VERSION 5.8 ;
BUSBITCHARS "[]" ;
DIVIDERCHAR "/" ;
UNITS
    DATABASE MICRONS 1000 ;
END UNITS

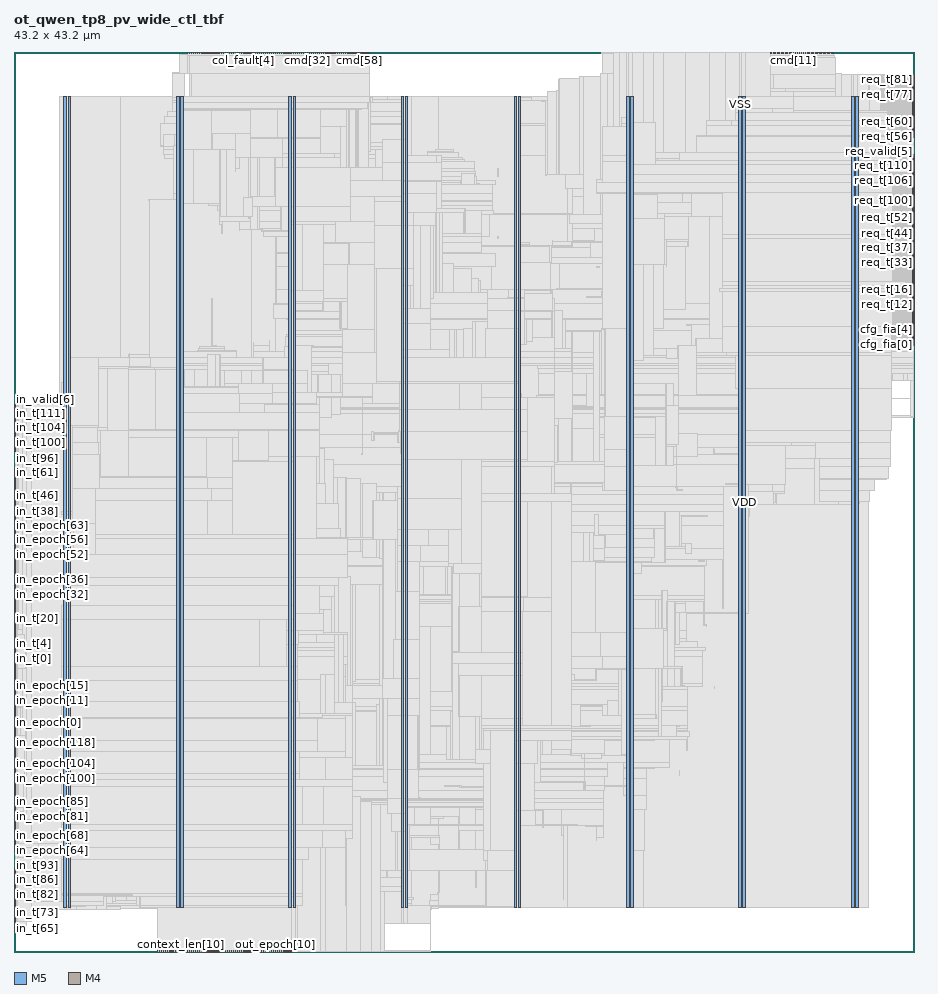
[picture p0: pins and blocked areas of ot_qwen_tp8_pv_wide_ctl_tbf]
MACRO ot_qwen_tp8_pv_wide_ctl_tbf
  FOREIGN ot_qwen_tp8_pv_wide_ctl_tbf 0 0 ;
  CLASS BLOCK ;
  SIZE 43.2 BY 43.2 ;
  PIN busy
    DIRECTION OUTPUT ;
    USE SIGNAL ;
    PORT
      LAYER M5 ;
        RECT  6.864 0 6.888 0.084 ;
    END
  END busy
  PIN cfg_fia[0]
    DIRECTION INPUT ;
    USE SIGNAL ;
    PORT
      LAYER M4 ;
        RECT  43.116 29.136 43.2 29.16 ;
    END
  END cfg_fia[0]
  PIN cfg_fia[1]
    DIRECTION INPUT ;
    USE SIGNAL ;
    PORT
      LAYER M4 ;
        RECT  43.116 29.232 43.2 29.256 ;
    END
  END cfg_fia[1]
  PIN cfg_fia[2]
    DIRECTION INPUT ;
    USE SIGNAL ;
    PORT
      LAYER M4 ;
        RECT  43.116 29.328 43.2 29.352 ;
    END
  END cfg_fia[2]
  PIN cfg_fia[3]
    DIRECTION INPUT ;
    USE SIGNAL ;
    PORT
      LAYER M4 ;
        RECT  43.116 29.424 43.2 29.448 ;
    END
  END cfg_fia[3]
  PIN cfg_fia[4]
    DIRECTION INPUT ;
    USE SIGNAL ;
    PORT
      LAYER M4 ;
        RECT  43.116 29.52 43.2 29.544 ;
    END
  END cfg_fia[4]
  PIN cfg_fia[5]
    DIRECTION INPUT ;
    USE SIGNAL ;
    PORT
      LAYER M4 ;
        RECT  43.116 29.616 43.2 29.64 ;
    END
  END cfg_fia[5]
  PIN cfg_fia[6]
    DIRECTION INPUT ;
    USE SIGNAL ;
    PORT
      LAYER M4 ;
        RECT  43.116 29.712 43.2 29.736 ;
    END
  END cfg_fia[6]
  PIN cfg_fia[7]
    DIRECTION INPUT ;
    USE SIGNAL ;
    PORT
      LAYER M4 ;
        RECT  43.116 29.808 43.2 29.832 ;
    END
  END cfg_fia[7]
  PIN clk
    DIRECTION INPUT ;
    USE SIGNAL ;
    PORT
      LAYER M5 ;
        RECT  6.96 0 6.984 0.084 ;
    END
  END clk
  PIN cmd[0]
    DIRECTION OUTPUT ;
    USE SIGNAL ;
    PORT
      LAYER M5 ;
        RECT  36.336 43.116 36.36 43.2 ;
    END
  END cmd[0]
  PIN cmd[10]
    DIRECTION OUTPUT ;
    USE SIGNAL ;
    PORT
      LAYER M5 ;
        RECT  37.296 43.116 37.32 43.2 ;
    END
  END cmd[10]
  PIN cmd[11]
    DIRECTION OUTPUT ;
    USE SIGNAL ;
    PORT
      LAYER M5 ;
        RECT  37.392 43.116 37.416 43.2 ;
    END
  END cmd[11]
  PIN cmd[12]
    DIRECTION OUTPUT ;
    USE SIGNAL ;
    PORT
      LAYER M5 ;
        RECT  37.488 43.116 37.512 43.2 ;
    END
  END cmd[12]
  PIN cmd[13]
    DIRECTION OUTPUT ;
    USE SIGNAL ;
    PORT
      LAYER M5 ;
        RECT  37.584 43.116 37.608 43.2 ;
    END
  END cmd[13]
  PIN cmd[14]
    DIRECTION OUTPUT ;
    USE SIGNAL ;
    PORT
      LAYER M5 ;
        RECT  37.68 43.116 37.704 43.2 ;
    END
  END cmd[14]
  PIN cmd[15]
    DIRECTION OUTPUT ;
    USE SIGNAL ;
    PORT
      LAYER M5 ;
        RECT  37.776 43.116 37.8 43.2 ;
    END
  END cmd[15]
  PIN cmd[16]
    DIRECTION OUTPUT ;
    USE SIGNAL ;
    PORT
      LAYER M5 ;
        RECT  37.872 43.116 37.896 43.2 ;
    END
  END cmd[16]
  PIN cmd[17]
    DIRECTION OUTPUT ;
    USE SIGNAL ;
    PORT
      LAYER M5 ;
        RECT  37.968 43.116 37.992 43.2 ;
    END
  END cmd[17]
  PIN cmd[18]
    DIRECTION OUTPUT ;
    USE SIGNAL ;
    PORT
      LAYER M5 ;
        RECT  38.064 43.116 38.088 43.2 ;
    END
  END cmd[18]
  PIN cmd[19]
    DIRECTION OUTPUT ;
    USE SIGNAL ;
    PORT
      LAYER M5 ;
        RECT  38.16 43.116 38.184 43.2 ;
    END
  END cmd[19]
  PIN cmd[1]
    DIRECTION OUTPUT ;
    USE SIGNAL ;
    PORT
      LAYER M5 ;
        RECT  36.432 43.116 36.456 43.2 ;
    END
  END cmd[1]
  PIN cmd[20]
    DIRECTION OUTPUT ;
    USE SIGNAL ;
    PORT
      LAYER M5 ;
        RECT  38.256 43.116 38.28 43.2 ;
    END
  END cmd[20]
  PIN cmd[21]
    DIRECTION OUTPUT ;
    USE SIGNAL ;
    PORT
      LAYER M5 ;
        RECT  38.352 43.116 38.376 43.2 ;
    END
  END cmd[21]
  PIN cmd[22]
    DIRECTION OUTPUT ;
    USE SIGNAL ;
    PORT
      LAYER M5 ;
        RECT  38.448 43.116 38.472 43.2 ;
    END
  END cmd[22]
  PIN cmd[23]
    DIRECTION OUTPUT ;
    USE SIGNAL ;
    PORT
      LAYER M5 ;
        RECT  38.544 43.116 38.568 43.2 ;
    END
  END cmd[23]
  PIN cmd[24]
    DIRECTION OUTPUT ;
    USE SIGNAL ;
    PORT
      LAYER M5 ;
        RECT  38.64 43.116 38.664 43.2 ;
    END
  END cmd[24]
  PIN cmd[25]
    DIRECTION OUTPUT ;
    USE SIGNAL ;
    PORT
      LAYER M5 ;
        RECT  38.736 43.116 38.76 43.2 ;
    END
  END cmd[25]
  PIN cmd[26]
    DIRECTION OUTPUT ;
    USE SIGNAL ;
    PORT
      LAYER M5 ;
        RECT  38.832 43.116 38.856 43.2 ;
    END
  END cmd[26]
  PIN cmd[27]
    DIRECTION OUTPUT ;
    USE SIGNAL ;
    PORT
      LAYER M5 ;
        RECT  38.928 43.116 38.952 43.2 ;
    END
  END cmd[27]
  PIN cmd[28]
    DIRECTION OUTPUT ;
    USE SIGNAL ;
    PORT
      LAYER M5 ;
        RECT  39.024 43.116 39.048 43.2 ;
    END
  END cmd[28]
  PIN cmd[29]
    DIRECTION OUTPUT ;
    USE SIGNAL ;
    PORT
      LAYER M5 ;
        RECT  39.12 43.116 39.144 43.2 ;
    END
  END cmd[29]
  PIN cmd[2]
    DIRECTION OUTPUT ;
    USE SIGNAL ;
    PORT
      LAYER M5 ;
        RECT  36.528 43.116 36.552 43.2 ;
    END
  END cmd[2]
  PIN cmd[30]
    DIRECTION OUTPUT ;
    USE SIGNAL ;
    PORT
      LAYER M5 ;
        RECT  39.216 43.116 39.24 43.2 ;
    END
  END cmd[30]
  PIN cmd[31]
    DIRECTION OUTPUT ;
    USE SIGNAL ;
    PORT
      LAYER M5 ;
        RECT  39.312 43.116 39.336 43.2 ;
    END
  END cmd[31]
  PIN cmd[32]
    DIRECTION OUTPUT ;
    USE SIGNAL ;
    PORT
      LAYER M5 ;
        RECT  14.064 43.116 14.088 43.2 ;
    END
  END cmd[32]
  PIN cmd[33]
    DIRECTION OUTPUT ;
    USE SIGNAL ;
    PORT
      LAYER M5 ;
        RECT  14.16 43.116 14.184 43.2 ;
    END
  END cmd[33]
  PIN cmd[34]
    DIRECTION OUTPUT ;
    USE SIGNAL ;
    PORT
      LAYER M5 ;
        RECT  14.256 43.116 14.28 43.2 ;
    END
  END cmd[34]
  PIN cmd[35]
    DIRECTION OUTPUT ;
    USE SIGNAL ;
    PORT
      LAYER M5 ;
        RECT  14.352 43.116 14.376 43.2 ;
    END
  END cmd[35]
  PIN cmd[36]
    DIRECTION OUTPUT ;
    USE SIGNAL ;
    PORT
      LAYER M5 ;
        RECT  14.448 43.116 14.472 43.2 ;
    END
  END cmd[36]
  PIN cmd[37]
    DIRECTION OUTPUT ;
    USE SIGNAL ;
    PORT
      LAYER M5 ;
        RECT  14.544 43.116 14.568 43.2 ;
    END
  END cmd[37]
  PIN cmd[38]
    DIRECTION OUTPUT ;
    USE SIGNAL ;
    PORT
      LAYER M5 ;
        RECT  14.64 43.116 14.664 43.2 ;
    END
  END cmd[38]
  PIN cmd[39]
    DIRECTION OUTPUT ;
    USE SIGNAL ;
    PORT
      LAYER M5 ;
        RECT  14.736 43.116 14.76 43.2 ;
    END
  END cmd[39]
  PIN cmd[3]
    DIRECTION OUTPUT ;
    USE SIGNAL ;
    PORT
      LAYER M5 ;
        RECT  36.624 43.116 36.648 43.2 ;
    END
  END cmd[3]
  PIN cmd[40]
    DIRECTION OUTPUT ;
    USE SIGNAL ;
    PORT
      LAYER M5 ;
        RECT  14.832 43.116 14.856 43.2 ;
    END
  END cmd[40]
  PIN cmd[41]
    DIRECTION OUTPUT ;
    USE SIGNAL ;
    PORT
      LAYER M5 ;
        RECT  14.928 43.116 14.952 43.2 ;
    END
  END cmd[41]
  PIN cmd[42]
    DIRECTION OUTPUT ;
    USE SIGNAL ;
    PORT
      LAYER M5 ;
        RECT  15.024 43.116 15.048 43.2 ;
    END
  END cmd[42]
  PIN cmd[43]
    DIRECTION OUTPUT ;
    USE SIGNAL ;
    PORT
      LAYER M5 ;
        RECT  15.12 43.116 15.144 43.2 ;
    END
  END cmd[43]
  PIN cmd[44]
    DIRECTION OUTPUT ;
    USE SIGNAL ;
    PORT
      LAYER M5 ;
        RECT  15.216 43.116 15.24 43.2 ;
    END
  END cmd[44]
  PIN cmd[45]
    DIRECTION OUTPUT ;
    USE SIGNAL ;
    PORT
      LAYER M5 ;
        RECT  15.312 43.116 15.336 43.2 ;
    END
  END cmd[45]
  PIN cmd[46]
    DIRECTION OUTPUT ;
    USE SIGNAL ;
    PORT
      LAYER M5 ;
        RECT  15.408 43.116 15.432 43.2 ;
    END
  END cmd[46]
  PIN cmd[47]
    DIRECTION OUTPUT ;
    USE SIGNAL ;
    PORT
      LAYER M5 ;
        RECT  15.504 43.116 15.528 43.2 ;
    END
  END cmd[47]
  PIN cmd[48]
    DIRECTION OUTPUT ;
    USE SIGNAL ;
    PORT
      LAYER M5 ;
        RECT  15.6 43.116 15.624 43.2 ;
    END
  END cmd[48]
  PIN cmd[49]
    DIRECTION OUTPUT ;
    USE SIGNAL ;
    PORT
      LAYER M5 ;
        RECT  15.696 43.116 15.72 43.2 ;
    END
  END cmd[49]
  PIN cmd[4]
    DIRECTION OUTPUT ;
    USE SIGNAL ;
    PORT
      LAYER M5 ;
        RECT  36.72 43.116 36.744 43.2 ;
    END
  END cmd[4]
  PIN cmd[50]
    DIRECTION OUTPUT ;
    USE SIGNAL ;
    PORT
      LAYER M5 ;
        RECT  15.792 43.116 15.816 43.2 ;
    END
  END cmd[50]
  PIN cmd[51]
    DIRECTION OUTPUT ;
    USE SIGNAL ;
    PORT
      LAYER M5 ;
        RECT  15.888 43.116 15.912 43.2 ;
    END
  END cmd[51]
  PIN cmd[52]
    DIRECTION OUTPUT ;
    USE SIGNAL ;
    PORT
      LAYER M5 ;
        RECT  15.984 43.116 16.008 43.2 ;
    END
  END cmd[52]
  PIN cmd[53]
    DIRECTION OUTPUT ;
    USE SIGNAL ;
    PORT
      LAYER M5 ;
        RECT  16.08 43.116 16.104 43.2 ;
    END
  END cmd[53]
  PIN cmd[54]
    DIRECTION OUTPUT ;
    USE SIGNAL ;
    PORT
      LAYER M5 ;
        RECT  16.176 43.116 16.2 43.2 ;
    END
  END cmd[54]
  PIN cmd[55]
    DIRECTION OUTPUT ;
    USE SIGNAL ;
    PORT
      LAYER M5 ;
        RECT  16.272 43.116 16.296 43.2 ;
    END
  END cmd[55]
  PIN cmd[56]
    DIRECTION OUTPUT ;
    USE SIGNAL ;
    PORT
      LAYER M5 ;
        RECT  16.368 43.116 16.392 43.2 ;
    END
  END cmd[56]
  PIN cmd[57]
    DIRECTION OUTPUT ;
    USE SIGNAL ;
    PORT
      LAYER M5 ;
        RECT  16.464 43.116 16.488 43.2 ;
    END
  END cmd[57]
  PIN cmd[58]
    DIRECTION OUTPUT ;
    USE SIGNAL ;
    PORT
      LAYER M5 ;
        RECT  16.56 43.116 16.584 43.2 ;
    END
  END cmd[58]
  PIN cmd[59]
    DIRECTION OUTPUT ;
    USE SIGNAL ;
    PORT
      LAYER M5 ;
        RECT  16.656 43.116 16.68 43.2 ;
    END
  END cmd[59]
  PIN cmd[5]
    DIRECTION OUTPUT ;
    USE SIGNAL ;
    PORT
      LAYER M5 ;
        RECT  36.816 43.116 36.84 43.2 ;
    END
  END cmd[5]
  PIN cmd[6]
    DIRECTION OUTPUT ;
    USE SIGNAL ;
    PORT
      LAYER M5 ;
        RECT  36.912 43.116 36.936 43.2 ;
    END
  END cmd[6]
  PIN cmd[7]
    DIRECTION OUTPUT ;
    USE SIGNAL ;
    PORT
      LAYER M5 ;
        RECT  37.008 43.116 37.032 43.2 ;
    END
  END cmd[7]
  PIN cmd[8]
    DIRECTION OUTPUT ;
    USE SIGNAL ;
    PORT
      LAYER M5 ;
        RECT  37.104 43.116 37.128 43.2 ;
    END
  END cmd[8]
  PIN cmd[9]
    DIRECTION OUTPUT ;
    USE SIGNAL ;
    PORT
      LAYER M5 ;
        RECT  37.2 43.116 37.224 43.2 ;
    END
  END cmd[9]
  PIN col_fault[0]
    DIRECTION INPUT ;
    USE SIGNAL ;
    PORT
      LAYER M5 ;
        RECT  16.752 43.116 16.776 43.2 ;
    END
  END col_fault[0]
  PIN col_fault[10]
    DIRECTION INPUT ;
    USE SIGNAL ;
    PORT
      LAYER M5 ;
        RECT  11.568 43.116 11.592 43.2 ;
    END
  END col_fault[10]
  PIN col_fault[11]
    DIRECTION INPUT ;
    USE SIGNAL ;
    PORT
      LAYER M5 ;
        RECT  11.664 43.116 11.688 43.2 ;
    END
  END col_fault[11]
  PIN col_fault[12]
    DIRECTION INPUT ;
    USE SIGNAL ;
    PORT
      LAYER M5 ;
        RECT  11.76 43.116 11.784 43.2 ;
    END
  END col_fault[12]
  PIN col_fault[13]
    DIRECTION INPUT ;
    USE SIGNAL ;
    PORT
      LAYER M5 ;
        RECT  11.856 43.116 11.88 43.2 ;
    END
  END col_fault[13]
  PIN col_fault[14]
    DIRECTION INPUT ;
    USE SIGNAL ;
    PORT
      LAYER M5 ;
        RECT  11.952 43.116 11.976 43.2 ;
    END
  END col_fault[14]
  PIN col_fault[15]
    DIRECTION INPUT ;
    USE SIGNAL ;
    PORT
      LAYER M5 ;
        RECT  12.048 43.116 12.072 43.2 ;
    END
  END col_fault[15]
  PIN col_fault[16]
    DIRECTION INPUT ;
    USE SIGNAL ;
    PORT
      LAYER M5 ;
        RECT  12.144 43.116 12.168 43.2 ;
    END
  END col_fault[16]
  PIN col_fault[17]
    DIRECTION INPUT ;
    USE SIGNAL ;
    PORT
      LAYER M5 ;
        RECT  12.24 43.116 12.264 43.2 ;
    END
  END col_fault[17]
  PIN col_fault[18]
    DIRECTION INPUT ;
    USE SIGNAL ;
    PORT
      LAYER M5 ;
        RECT  12.336 43.116 12.36 43.2 ;
    END
  END col_fault[18]
  PIN col_fault[19]
    DIRECTION INPUT ;
    USE SIGNAL ;
    PORT
      LAYER M5 ;
        RECT  12.432 43.116 12.456 43.2 ;
    END
  END col_fault[19]
  PIN col_fault[1]
    DIRECTION INPUT ;
    USE SIGNAL ;
    PORT
      LAYER M5 ;
        RECT  16.848 43.116 16.872 43.2 ;
    END
  END col_fault[1]
  PIN col_fault[20]
    DIRECTION INPUT ;
    USE SIGNAL ;
    PORT
      LAYER M5 ;
        RECT  12.528 43.116 12.552 43.2 ;
    END
  END col_fault[20]
  PIN col_fault[21]
    DIRECTION INPUT ;
    USE SIGNAL ;
    PORT
      LAYER M5 ;
        RECT  12.624 43.116 12.648 43.2 ;
    END
  END col_fault[21]
  PIN col_fault[22]
    DIRECTION INPUT ;
    USE SIGNAL ;
    PORT
      LAYER M5 ;
        RECT  12.72 43.116 12.744 43.2 ;
    END
  END col_fault[22]
  PIN col_fault[23]
    DIRECTION INPUT ;
    USE SIGNAL ;
    PORT
      LAYER M5 ;
        RECT  12.816 43.116 12.84 43.2 ;
    END
  END col_fault[23]
  PIN col_fault[24]
    DIRECTION INPUT ;
    USE SIGNAL ;
    PORT
      LAYER M5 ;
        RECT  12.912 43.116 12.936 43.2 ;
    END
  END col_fault[24]
  PIN col_fault[25]
    DIRECTION INPUT ;
    USE SIGNAL ;
    PORT
      LAYER M5 ;
        RECT  13.008 43.116 13.032 43.2 ;
    END
  END col_fault[25]
  PIN col_fault[26]
    DIRECTION INPUT ;
    USE SIGNAL ;
    PORT
      LAYER M5 ;
        RECT  13.104 43.116 13.128 43.2 ;
    END
  END col_fault[26]
  PIN col_fault[27]
    DIRECTION INPUT ;
    USE SIGNAL ;
    PORT
      LAYER M5 ;
        RECT  13.2 43.116 13.224 43.2 ;
    END
  END col_fault[27]
  PIN col_fault[28]
    DIRECTION INPUT ;
    USE SIGNAL ;
    PORT
      LAYER M5 ;
        RECT  13.296 43.116 13.32 43.2 ;
    END
  END col_fault[28]
  PIN col_fault[29]
    DIRECTION INPUT ;
    USE SIGNAL ;
    PORT
      LAYER M5 ;
        RECT  13.392 43.116 13.416 43.2 ;
    END
  END col_fault[29]
  PIN col_fault[2]
    DIRECTION INPUT ;
    USE SIGNAL ;
    PORT
      LAYER M5 ;
        RECT  16.944 43.116 16.968 43.2 ;
    END
  END col_fault[2]
  PIN col_fault[30]
    DIRECTION INPUT ;
    USE SIGNAL ;
    PORT
      LAYER M5 ;
        RECT  13.488 43.116 13.512 43.2 ;
    END
  END col_fault[30]
  PIN col_fault[31]
    DIRECTION INPUT ;
    USE SIGNAL ;
    PORT
      LAYER M5 ;
        RECT  13.584 43.116 13.608 43.2 ;
    END
  END col_fault[31]
  PIN col_fault[3]
    DIRECTION INPUT ;
    USE SIGNAL ;
    PORT
      LAYER M5 ;
        RECT  17.04 43.116 17.064 43.2 ;
    END
  END col_fault[3]
  PIN col_fault[4]
    DIRECTION INPUT ;
    USE SIGNAL ;
    PORT
      LAYER M5 ;
        RECT  10.992 43.116 11.016 43.2 ;
    END
  END col_fault[4]
  PIN col_fault[5]
    DIRECTION INPUT ;
    USE SIGNAL ;
    PORT
      LAYER M5 ;
        RECT  11.088 43.116 11.112 43.2 ;
    END
  END col_fault[5]
  PIN col_fault[6]
    DIRECTION INPUT ;
    USE SIGNAL ;
    PORT
      LAYER M5 ;
        RECT  11.184 43.116 11.208 43.2 ;
    END
  END col_fault[6]
  PIN col_fault[7]
    DIRECTION INPUT ;
    USE SIGNAL ;
    PORT
      LAYER M5 ;
        RECT  11.28 43.116 11.304 43.2 ;
    END
  END col_fault[7]
  PIN col_fault[8]
    DIRECTION INPUT ;
    USE SIGNAL ;
    PORT
      LAYER M5 ;
        RECT  11.376 43.116 11.4 43.2 ;
    END
  END col_fault[8]
  PIN col_fault[9]
    DIRECTION INPUT ;
    USE SIGNAL ;
    PORT
      LAYER M5 ;
        RECT  11.472 43.116 11.496 43.2 ;
    END
  END col_fault[9]
  PIN col_valid[0]
    DIRECTION INPUT ;
    USE SIGNAL ;
    PORT
      LAYER M5 ;
        RECT  13.68 43.116 13.704 43.2 ;
    END
  END col_valid[0]
  PIN col_valid[10]
    DIRECTION INPUT ;
    USE SIGNAL ;
    PORT
      LAYER M5 ;
        RECT  8.88 43.116 8.904 43.2 ;
    END
  END col_valid[10]
  PIN col_valid[11]
    DIRECTION INPUT ;
    USE SIGNAL ;
    PORT
      LAYER M5 ;
        RECT  8.976 43.116 9 43.2 ;
    END
  END col_valid[11]
  PIN col_valid[12]
    DIRECTION INPUT ;
    USE SIGNAL ;
    PORT
      LAYER M5 ;
        RECT  9.072 43.116 9.096 43.2 ;
    END
  END col_valid[12]
  PIN col_valid[13]
    DIRECTION INPUT ;
    USE SIGNAL ;
    PORT
      LAYER M5 ;
        RECT  9.168 43.116 9.192 43.2 ;
    END
  END col_valid[13]
  PIN col_valid[14]
    DIRECTION INPUT ;
    USE SIGNAL ;
    PORT
      LAYER M5 ;
        RECT  9.264 43.116 9.288 43.2 ;
    END
  END col_valid[14]
  PIN col_valid[15]
    DIRECTION INPUT ;
    USE SIGNAL ;
    PORT
      LAYER M5 ;
        RECT  9.36 43.116 9.384 43.2 ;
    END
  END col_valid[15]
  PIN col_valid[16]
    DIRECTION INPUT ;
    USE SIGNAL ;
    PORT
      LAYER M5 ;
        RECT  9.456 43.116 9.48 43.2 ;
    END
  END col_valid[16]
  PIN col_valid[17]
    DIRECTION INPUT ;
    USE SIGNAL ;
    PORT
      LAYER M5 ;
        RECT  9.552 43.116 9.576 43.2 ;
    END
  END col_valid[17]
  PIN col_valid[18]
    DIRECTION INPUT ;
    USE SIGNAL ;
    PORT
      LAYER M5 ;
        RECT  9.648 43.116 9.672 43.2 ;
    END
  END col_valid[18]
  PIN col_valid[19]
    DIRECTION INPUT ;
    USE SIGNAL ;
    PORT
      LAYER M5 ;
        RECT  9.744 43.116 9.768 43.2 ;
    END
  END col_valid[19]
  PIN col_valid[1]
    DIRECTION INPUT ;
    USE SIGNAL ;
    PORT
      LAYER M5 ;
        RECT  13.776 43.116 13.8 43.2 ;
    END
  END col_valid[1]
  PIN col_valid[20]
    DIRECTION INPUT ;
    USE SIGNAL ;
    PORT
      LAYER M5 ;
        RECT  9.84 43.116 9.864 43.2 ;
    END
  END col_valid[20]
  PIN col_valid[21]
    DIRECTION INPUT ;
    USE SIGNAL ;
    PORT
      LAYER M5 ;
        RECT  9.936 43.116 9.96 43.2 ;
    END
  END col_valid[21]
  PIN col_valid[22]
    DIRECTION INPUT ;
    USE SIGNAL ;
    PORT
      LAYER M5 ;
        RECT  10.032 43.116 10.056 43.2 ;
    END
  END col_valid[22]
  PIN col_valid[23]
    DIRECTION INPUT ;
    USE SIGNAL ;
    PORT
      LAYER M5 ;
        RECT  10.128 43.116 10.152 43.2 ;
    END
  END col_valid[23]
  PIN col_valid[24]
    DIRECTION INPUT ;
    USE SIGNAL ;
    PORT
      LAYER M5 ;
        RECT  10.224 43.116 10.248 43.2 ;
    END
  END col_valid[24]
  PIN col_valid[25]
    DIRECTION INPUT ;
    USE SIGNAL ;
    PORT
      LAYER M5 ;
        RECT  10.32 43.116 10.344 43.2 ;
    END
  END col_valid[25]
  PIN col_valid[26]
    DIRECTION INPUT ;
    USE SIGNAL ;
    PORT
      LAYER M5 ;
        RECT  10.416 43.116 10.44 43.2 ;
    END
  END col_valid[26]
  PIN col_valid[27]
    DIRECTION INPUT ;
    USE SIGNAL ;
    PORT
      LAYER M5 ;
        RECT  10.512 43.116 10.536 43.2 ;
    END
  END col_valid[27]
  PIN col_valid[28]
    DIRECTION INPUT ;
    USE SIGNAL ;
    PORT
      LAYER M5 ;
        RECT  10.608 43.116 10.632 43.2 ;
    END
  END col_valid[28]
  PIN col_valid[29]
    DIRECTION INPUT ;
    USE SIGNAL ;
    PORT
      LAYER M5 ;
        RECT  10.704 43.116 10.728 43.2 ;
    END
  END col_valid[29]
  PIN col_valid[2]
    DIRECTION INPUT ;
    USE SIGNAL ;
    PORT
      LAYER M5 ;
        RECT  13.872 43.116 13.896 43.2 ;
    END
  END col_valid[2]
  PIN col_valid[30]
    DIRECTION INPUT ;
    USE SIGNAL ;
    PORT
      LAYER M5 ;
        RECT  10.8 43.116 10.824 43.2 ;
    END
  END col_valid[30]
  PIN col_valid[31]
    DIRECTION INPUT ;
    USE SIGNAL ;
    PORT
      LAYER M5 ;
        RECT  10.896 43.116 10.92 43.2 ;
    END
  END col_valid[31]
  PIN col_valid[3]
    DIRECTION INPUT ;
    USE SIGNAL ;
    PORT
      LAYER M5 ;
        RECT  13.968 43.116 13.992 43.2 ;
    END
  END col_valid[3]
  PIN col_valid[4]
    DIRECTION INPUT ;
    USE SIGNAL ;
    PORT
      LAYER M5 ;
        RECT  8.304 43.116 8.328 43.2 ;
    END
  END col_valid[4]
  PIN col_valid[5]
    DIRECTION INPUT ;
    USE SIGNAL ;
    PORT
      LAYER M5 ;
        RECT  8.4 43.116 8.424 43.2 ;
    END
  END col_valid[5]
  PIN col_valid[6]
    DIRECTION INPUT ;
    USE SIGNAL ;
    PORT
      LAYER M5 ;
        RECT  8.496 43.116 8.52 43.2 ;
    END
  END col_valid[6]
  PIN col_valid[7]
    DIRECTION INPUT ;
    USE SIGNAL ;
    PORT
      LAYER M5 ;
        RECT  8.592 43.116 8.616 43.2 ;
    END
  END col_valid[7]
  PIN col_valid[8]
    DIRECTION INPUT ;
    USE SIGNAL ;
    PORT
      LAYER M5 ;
        RECT  8.688 43.116 8.712 43.2 ;
    END
  END col_valid[8]
  PIN col_valid[9]
    DIRECTION INPUT ;
    USE SIGNAL ;
    PORT
      LAYER M5 ;
        RECT  8.784 43.116 8.808 43.2 ;
    END
  END col_valid[9]
  PIN context_len[0]
    DIRECTION INPUT ;
    USE SIGNAL ;
    PORT
      LAYER M5 ;
        RECT  7.056 0 7.08 0.084 ;
    END
  END context_len[0]
  PIN context_len[10]
    DIRECTION INPUT ;
    USE SIGNAL ;
    PORT
      LAYER M5 ;
        RECT  8.016 0 8.04 0.084 ;
    END
  END context_len[10]
  PIN context_len[11]
    DIRECTION INPUT ;
    USE SIGNAL ;
    PORT
      LAYER M5 ;
        RECT  8.112 0 8.136 0.084 ;
    END
  END context_len[11]
  PIN context_len[12]
    DIRECTION INPUT ;
    USE SIGNAL ;
    PORT
      LAYER M5 ;
        RECT  8.208 0 8.232 0.084 ;
    END
  END context_len[12]
  PIN context_len[13]
    DIRECTION INPUT ;
    USE SIGNAL ;
    PORT
      LAYER M5 ;
        RECT  8.304 0 8.328 0.084 ;
    END
  END context_len[13]
  PIN context_len[1]
    DIRECTION INPUT ;
    USE SIGNAL ;
    PORT
      LAYER M5 ;
        RECT  7.152 0 7.176 0.084 ;
    END
  END context_len[1]
  PIN context_len[2]
    DIRECTION INPUT ;
    USE SIGNAL ;
    PORT
      LAYER M5 ;
        RECT  7.248 0 7.272 0.084 ;
    END
  END context_len[2]
  PIN context_len[3]
    DIRECTION INPUT ;
    USE SIGNAL ;
    PORT
      LAYER M5 ;
        RECT  7.344 0 7.368 0.084 ;
    END
  END context_len[3]
  PIN context_len[4]
    DIRECTION INPUT ;
    USE SIGNAL ;
    PORT
      LAYER M5 ;
        RECT  7.44 0 7.464 0.084 ;
    END
  END context_len[4]
  PIN context_len[5]
    DIRECTION INPUT ;
    USE SIGNAL ;
    PORT
      LAYER M5 ;
        RECT  7.536 0 7.56 0.084 ;
    END
  END context_len[5]
  PIN context_len[6]
    DIRECTION INPUT ;
    USE SIGNAL ;
    PORT
      LAYER M5 ;
        RECT  7.632 0 7.656 0.084 ;
    END
  END context_len[6]
  PIN context_len[7]
    DIRECTION INPUT ;
    USE SIGNAL ;
    PORT
      LAYER M5 ;
        RECT  7.728 0 7.752 0.084 ;
    END
  END context_len[7]
  PIN context_len[8]
    DIRECTION INPUT ;
    USE SIGNAL ;
    PORT
      LAYER M5 ;
        RECT  7.824 0 7.848 0.084 ;
    END
  END context_len[8]
  PIN context_len[9]
    DIRECTION INPUT ;
    USE SIGNAL ;
    PORT
      LAYER M5 ;
        RECT  7.92 0 7.944 0.084 ;
    END
  END context_len[9]
  PIN epoch[0]
    DIRECTION INPUT ;
    USE SIGNAL ;
    PORT
      LAYER M5 ;
        RECT  8.4 0 8.424 0.084 ;
    END
  END epoch[0]
  PIN epoch[10]
    DIRECTION INPUT ;
    USE SIGNAL ;
    PORT
      LAYER M5 ;
        RECT  9.36 0 9.384 0.084 ;
    END
  END epoch[10]
  PIN epoch[11]
    DIRECTION INPUT ;
    USE SIGNAL ;
    PORT
      LAYER M5 ;
        RECT  9.456 0 9.48 0.084 ;
    END
  END epoch[11]
  PIN epoch[12]
    DIRECTION INPUT ;
    USE SIGNAL ;
    PORT
      LAYER M5 ;
        RECT  9.552 0 9.576 0.084 ;
    END
  END epoch[12]
  PIN epoch[13]
    DIRECTION INPUT ;
    USE SIGNAL ;
    PORT
      LAYER M5 ;
        RECT  9.648 0 9.672 0.084 ;
    END
  END epoch[13]
  PIN epoch[14]
    DIRECTION INPUT ;
    USE SIGNAL ;
    PORT
      LAYER M5 ;
        RECT  9.744 0 9.768 0.084 ;
    END
  END epoch[14]
  PIN epoch[15]
    DIRECTION INPUT ;
    USE SIGNAL ;
    PORT
      LAYER M5 ;
        RECT  9.84 0 9.864 0.084 ;
    END
  END epoch[15]
  PIN epoch[1]
    DIRECTION INPUT ;
    USE SIGNAL ;
    PORT
      LAYER M5 ;
        RECT  8.496 0 8.52 0.084 ;
    END
  END epoch[1]
  PIN epoch[2]
    DIRECTION INPUT ;
    USE SIGNAL ;
    PORT
      LAYER M5 ;
        RECT  8.592 0 8.616 0.084 ;
    END
  END epoch[2]
  PIN epoch[3]
    DIRECTION INPUT ;
    USE SIGNAL ;
    PORT
      LAYER M5 ;
        RECT  8.688 0 8.712 0.084 ;
    END
  END epoch[3]
  PIN epoch[4]
    DIRECTION INPUT ;
    USE SIGNAL ;
    PORT
      LAYER M5 ;
        RECT  8.784 0 8.808 0.084 ;
    END
  END epoch[4]
  PIN epoch[5]
    DIRECTION INPUT ;
    USE SIGNAL ;
    PORT
      LAYER M5 ;
        RECT  8.88 0 8.904 0.084 ;
    END
  END epoch[5]
  PIN epoch[6]
    DIRECTION INPUT ;
    USE SIGNAL ;
    PORT
      LAYER M5 ;
        RECT  8.976 0 9 0.084 ;
    END
  END epoch[6]
  PIN epoch[7]
    DIRECTION INPUT ;
    USE SIGNAL ;
    PORT
      LAYER M5 ;
        RECT  9.072 0 9.096 0.084 ;
    END
  END epoch[7]
  PIN epoch[8]
    DIRECTION INPUT ;
    USE SIGNAL ;
    PORT
      LAYER M5 ;
        RECT  9.168 0 9.192 0.084 ;
    END
  END epoch[8]
  PIN epoch[9]
    DIRECTION INPUT ;
    USE SIGNAL ;
    PORT
      LAYER M5 ;
        RECT  9.264 0 9.288 0.084 ;
    END
  END epoch[9]
  PIN fault
    DIRECTION OUTPUT ;
    USE SIGNAL ;
    PORT
      LAYER M5 ;
        RECT  9.936 0 9.96 0.084 ;
    END
  END fault
  PIN in_epoch[0]
    DIRECTION INPUT ;
    USE SIGNAL ;
    PORT
      LAYER M4 ;
        RECT  0 10.992 0.084 11.016 ;
    END
  END in_epoch[0]
  PIN in_epoch[100]
    DIRECTION INPUT ;
    USE SIGNAL ;
    PORT
      LAYER M4 ;
        RECT  0 8.304 0.084 8.328 ;
    END
  END in_epoch[100]
  PIN in_epoch[101]
    DIRECTION INPUT ;
    USE SIGNAL ;
    PORT
      LAYER M4 ;
        RECT  0 8.4 0.084 8.424 ;
    END
  END in_epoch[101]
  PIN in_epoch[102]
    DIRECTION INPUT ;
    USE SIGNAL ;
    PORT
      LAYER M4 ;
        RECT  0 8.496 0.084 8.52 ;
    END
  END in_epoch[102]
  PIN in_epoch[103]
    DIRECTION INPUT ;
    USE SIGNAL ;
    PORT
      LAYER M4 ;
        RECT  0 8.592 0.084 8.616 ;
    END
  END in_epoch[103]
  PIN in_epoch[104]
    DIRECTION INPUT ;
    USE SIGNAL ;
    PORT
      LAYER M4 ;
        RECT  0 8.688 0.084 8.712 ;
    END
  END in_epoch[104]
  PIN in_epoch[105]
    DIRECTION INPUT ;
    USE SIGNAL ;
    PORT
      LAYER M4 ;
        RECT  0 8.784 0.084 8.808 ;
    END
  END in_epoch[105]
  PIN in_epoch[106]
    DIRECTION INPUT ;
    USE SIGNAL ;
    PORT
      LAYER M4 ;
        RECT  0 8.88 0.084 8.904 ;
    END
  END in_epoch[106]
  PIN in_epoch[107]
    DIRECTION INPUT ;
    USE SIGNAL ;
    PORT
      LAYER M4 ;
        RECT  0 8.976 0.084 9 ;
    END
  END in_epoch[107]
  PIN in_epoch[108]
    DIRECTION INPUT ;
    USE SIGNAL ;
    PORT
      LAYER M4 ;
        RECT  0 9.072 0.084 9.096 ;
    END
  END in_epoch[108]
  PIN in_epoch[109]
    DIRECTION INPUT ;
    USE SIGNAL ;
    PORT
      LAYER M4 ;
        RECT  0 9.168 0.084 9.192 ;
    END
  END in_epoch[109]
  PIN in_epoch[10]
    DIRECTION INPUT ;
    USE SIGNAL ;
    PORT
      LAYER M4 ;
        RECT  0 11.952 0.084 11.976 ;
    END
  END in_epoch[10]
  PIN in_epoch[110]
    DIRECTION INPUT ;
    USE SIGNAL ;
    PORT
      LAYER M4 ;
        RECT  0 9.264 0.084 9.288 ;
    END
  END in_epoch[110]
  PIN in_epoch[111]
    DIRECTION INPUT ;
    USE SIGNAL ;
    PORT
      LAYER M4 ;
        RECT  0 9.36 0.084 9.384 ;
    END
  END in_epoch[111]
  PIN in_epoch[112]
    DIRECTION INPUT ;
    USE SIGNAL ;
    PORT
      LAYER M4 ;
        RECT  0 9.456 0.084 9.48 ;
    END
  END in_epoch[112]
  PIN in_epoch[113]
    DIRECTION INPUT ;
    USE SIGNAL ;
    PORT
      LAYER M4 ;
        RECT  0 9.552 0.084 9.576 ;
    END
  END in_epoch[113]
  PIN in_epoch[114]
    DIRECTION INPUT ;
    USE SIGNAL ;
    PORT
      LAYER M4 ;
        RECT  0 9.648 0.084 9.672 ;
    END
  END in_epoch[114]
  PIN in_epoch[115]
    DIRECTION INPUT ;
    USE SIGNAL ;
    PORT
      LAYER M4 ;
        RECT  0 9.744 0.084 9.768 ;
    END
  END in_epoch[115]
  PIN in_epoch[116]
    DIRECTION INPUT ;
    USE SIGNAL ;
    PORT
      LAYER M4 ;
        RECT  0 9.84 0.084 9.864 ;
    END
  END in_epoch[116]
  PIN in_epoch[117]
    DIRECTION INPUT ;
    USE SIGNAL ;
    PORT
      LAYER M4 ;
        RECT  0 9.936 0.084 9.96 ;
    END
  END in_epoch[117]
  PIN in_epoch[118]
    DIRECTION INPUT ;
    USE SIGNAL ;
    PORT
      LAYER M4 ;
        RECT  0 10.032 0.084 10.056 ;
    END
  END in_epoch[118]
  PIN in_epoch[119]
    DIRECTION INPUT ;
    USE SIGNAL ;
    PORT
      LAYER M4 ;
        RECT  0 10.128 0.084 10.152 ;
    END
  END in_epoch[119]
  PIN in_epoch[11]
    DIRECTION INPUT ;
    USE SIGNAL ;
    PORT
      LAYER M4 ;
        RECT  0 12.048 0.084 12.072 ;
    END
  END in_epoch[11]
  PIN in_epoch[120]
    DIRECTION INPUT ;
    USE SIGNAL ;
    PORT
      LAYER M4 ;
        RECT  0 10.224 0.084 10.248 ;
    END
  END in_epoch[120]
  PIN in_epoch[121]
    DIRECTION INPUT ;
    USE SIGNAL ;
    PORT
      LAYER M4 ;
        RECT  0 10.32 0.084 10.344 ;
    END
  END in_epoch[121]
  PIN in_epoch[122]
    DIRECTION INPUT ;
    USE SIGNAL ;
    PORT
      LAYER M4 ;
        RECT  0 10.416 0.084 10.44 ;
    END
  END in_epoch[122]
  PIN in_epoch[123]
    DIRECTION INPUT ;
    USE SIGNAL ;
    PORT
      LAYER M4 ;
        RECT  0 10.512 0.084 10.536 ;
    END
  END in_epoch[123]
  PIN in_epoch[124]
    DIRECTION INPUT ;
    USE SIGNAL ;
    PORT
      LAYER M4 ;
        RECT  0 10.608 0.084 10.632 ;
    END
  END in_epoch[124]
  PIN in_epoch[125]
    DIRECTION INPUT ;
    USE SIGNAL ;
    PORT
      LAYER M4 ;
        RECT  0 10.704 0.084 10.728 ;
    END
  END in_epoch[125]
  PIN in_epoch[126]
    DIRECTION INPUT ;
    USE SIGNAL ;
    PORT
      LAYER M4 ;
        RECT  0 10.8 0.084 10.824 ;
    END
  END in_epoch[126]
  PIN in_epoch[127]
    DIRECTION INPUT ;
    USE SIGNAL ;
    PORT
      LAYER M4 ;
        RECT  0 10.896 0.084 10.92 ;
    END
  END in_epoch[127]
  PIN in_epoch[12]
    DIRECTION INPUT ;
    USE SIGNAL ;
    PORT
      LAYER M4 ;
        RECT  0 12.144 0.084 12.168 ;
    END
  END in_epoch[12]
  PIN in_epoch[13]
    DIRECTION INPUT ;
    USE SIGNAL ;
    PORT
      LAYER M4 ;
        RECT  0 12.24 0.084 12.264 ;
    END
  END in_epoch[13]
  PIN in_epoch[14]
    DIRECTION INPUT ;
    USE SIGNAL ;
    PORT
      LAYER M4 ;
        RECT  0 12.336 0.084 12.36 ;
    END
  END in_epoch[14]
  PIN in_epoch[15]
    DIRECTION INPUT ;
    USE SIGNAL ;
    PORT
      LAYER M4 ;
        RECT  0 12.432 0.084 12.456 ;
    END
  END in_epoch[15]
  PIN in_epoch[16]
    DIRECTION INPUT ;
    USE SIGNAL ;
    PORT
      LAYER M4 ;
        RECT  0 12.528 0.084 12.552 ;
    END
  END in_epoch[16]
  PIN in_epoch[17]
    DIRECTION INPUT ;
    USE SIGNAL ;
    PORT
      LAYER M4 ;
        RECT  0 12.624 0.084 12.648 ;
    END
  END in_epoch[17]
  PIN in_epoch[18]
    DIRECTION INPUT ;
    USE SIGNAL ;
    PORT
      LAYER M4 ;
        RECT  0 12.72 0.084 12.744 ;
    END
  END in_epoch[18]
  PIN in_epoch[19]
    DIRECTION INPUT ;
    USE SIGNAL ;
    PORT
      LAYER M4 ;
        RECT  0 12.816 0.084 12.84 ;
    END
  END in_epoch[19]
  PIN in_epoch[1]
    DIRECTION INPUT ;
    USE SIGNAL ;
    PORT
      LAYER M4 ;
        RECT  0 11.088 0.084 11.112 ;
    END
  END in_epoch[1]
  PIN in_epoch[20]
    DIRECTION INPUT ;
    USE SIGNAL ;
    PORT
      LAYER M4 ;
        RECT  0 12.912 0.084 12.936 ;
    END
  END in_epoch[20]
  PIN in_epoch[21]
    DIRECTION INPUT ;
    USE SIGNAL ;
    PORT
      LAYER M4 ;
        RECT  0 13.008 0.084 13.032 ;
    END
  END in_epoch[21]
  PIN in_epoch[22]
    DIRECTION INPUT ;
    USE SIGNAL ;
    PORT
      LAYER M4 ;
        RECT  0 13.104 0.084 13.128 ;
    END
  END in_epoch[22]
  PIN in_epoch[23]
    DIRECTION INPUT ;
    USE SIGNAL ;
    PORT
      LAYER M4 ;
        RECT  0 13.2 0.084 13.224 ;
    END
  END in_epoch[23]
  PIN in_epoch[24]
    DIRECTION INPUT ;
    USE SIGNAL ;
    PORT
      LAYER M4 ;
        RECT  0 13.296 0.084 13.32 ;
    END
  END in_epoch[24]
  PIN in_epoch[25]
    DIRECTION INPUT ;
    USE SIGNAL ;
    PORT
      LAYER M4 ;
        RECT  0 13.392 0.084 13.416 ;
    END
  END in_epoch[25]
  PIN in_epoch[26]
    DIRECTION INPUT ;
    USE SIGNAL ;
    PORT
      LAYER M4 ;
        RECT  0 13.488 0.084 13.512 ;
    END
  END in_epoch[26]
  PIN in_epoch[27]
    DIRECTION INPUT ;
    USE SIGNAL ;
    PORT
      LAYER M4 ;
        RECT  0 13.584 0.084 13.608 ;
    END
  END in_epoch[27]
  PIN in_epoch[28]
    DIRECTION INPUT ;
    USE SIGNAL ;
    PORT
      LAYER M4 ;
        RECT  0 13.68 0.084 13.704 ;
    END
  END in_epoch[28]
  PIN in_epoch[29]
    DIRECTION INPUT ;
    USE SIGNAL ;
    PORT
      LAYER M4 ;
        RECT  0 13.776 0.084 13.8 ;
    END
  END in_epoch[29]
  PIN in_epoch[2]
    DIRECTION INPUT ;
    USE SIGNAL ;
    PORT
      LAYER M4 ;
        RECT  0 11.184 0.084 11.208 ;
    END
  END in_epoch[2]
  PIN in_epoch[30]
    DIRECTION INPUT ;
    USE SIGNAL ;
    PORT
      LAYER M4 ;
        RECT  0 13.872 0.084 13.896 ;
    END
  END in_epoch[30]
  PIN in_epoch[31]
    DIRECTION INPUT ;
    USE SIGNAL ;
    PORT
      LAYER M4 ;
        RECT  0 13.968 0.084 13.992 ;
    END
  END in_epoch[31]
  PIN in_epoch[32]
    DIRECTION INPUT ;
    USE SIGNAL ;
    PORT
      LAYER M4 ;
        RECT  0 17.136 0.084 17.16 ;
    END
  END in_epoch[32]
  PIN in_epoch[33]
    DIRECTION INPUT ;
    USE SIGNAL ;
    PORT
      LAYER M4 ;
        RECT  0 17.232 0.084 17.256 ;
    END
  END in_epoch[33]
  PIN in_epoch[34]
    DIRECTION INPUT ;
    USE SIGNAL ;
    PORT
      LAYER M4 ;
        RECT  0 17.328 0.084 17.352 ;
    END
  END in_epoch[34]
  PIN in_epoch[35]
    DIRECTION INPUT ;
    USE SIGNAL ;
    PORT
      LAYER M4 ;
        RECT  0 17.424 0.084 17.448 ;
    END
  END in_epoch[35]
  PIN in_epoch[36]
    DIRECTION INPUT ;
    USE SIGNAL ;
    PORT
      LAYER M4 ;
        RECT  0 17.52 0.084 17.544 ;
    END
  END in_epoch[36]
  PIN in_epoch[37]
    DIRECTION INPUT ;
    USE SIGNAL ;
    PORT
      LAYER M4 ;
        RECT  0 17.616 0.084 17.64 ;
    END
  END in_epoch[37]
  PIN in_epoch[38]
    DIRECTION INPUT ;
    USE SIGNAL ;
    PORT
      LAYER M4 ;
        RECT  0 17.712 0.084 17.736 ;
    END
  END in_epoch[38]
  PIN in_epoch[39]
    DIRECTION INPUT ;
    USE SIGNAL ;
    PORT
      LAYER M4 ;
        RECT  0 17.808 0.084 17.832 ;
    END
  END in_epoch[39]
  PIN in_epoch[3]
    DIRECTION INPUT ;
    USE SIGNAL ;
    PORT
      LAYER M4 ;
        RECT  0 11.28 0.084 11.304 ;
    END
  END in_epoch[3]
  PIN in_epoch[40]
    DIRECTION INPUT ;
    USE SIGNAL ;
    PORT
      LAYER M4 ;
        RECT  0 17.904 0.084 17.928 ;
    END
  END in_epoch[40]
  PIN in_epoch[41]
    DIRECTION INPUT ;
    USE SIGNAL ;
    PORT
      LAYER M4 ;
        RECT  0 18 0.084 18.024 ;
    END
  END in_epoch[41]
  PIN in_epoch[42]
    DIRECTION INPUT ;
    USE SIGNAL ;
    PORT
      LAYER M4 ;
        RECT  0 18.096 0.084 18.12 ;
    END
  END in_epoch[42]
  PIN in_epoch[43]
    DIRECTION INPUT ;
    USE SIGNAL ;
    PORT
      LAYER M4 ;
        RECT  0 18.192 0.084 18.216 ;
    END
  END in_epoch[43]
  PIN in_epoch[44]
    DIRECTION INPUT ;
    USE SIGNAL ;
    PORT
      LAYER M4 ;
        RECT  0 18.288 0.084 18.312 ;
    END
  END in_epoch[44]
  PIN in_epoch[45]
    DIRECTION INPUT ;
    USE SIGNAL ;
    PORT
      LAYER M4 ;
        RECT  0 18.384 0.084 18.408 ;
    END
  END in_epoch[45]
  PIN in_epoch[46]
    DIRECTION INPUT ;
    USE SIGNAL ;
    PORT
      LAYER M4 ;
        RECT  0 18.48 0.084 18.504 ;
    END
  END in_epoch[46]
  PIN in_epoch[47]
    DIRECTION INPUT ;
    USE SIGNAL ;
    PORT
      LAYER M4 ;
        RECT  0 18.576 0.084 18.6 ;
    END
  END in_epoch[47]
  PIN in_epoch[48]
    DIRECTION INPUT ;
    USE SIGNAL ;
    PORT
      LAYER M4 ;
        RECT  0 18.672 0.084 18.696 ;
    END
  END in_epoch[48]
  PIN in_epoch[49]
    DIRECTION INPUT ;
    USE SIGNAL ;
    PORT
      LAYER M4 ;
        RECT  0 18.768 0.084 18.792 ;
    END
  END in_epoch[49]
  PIN in_epoch[4]
    DIRECTION INPUT ;
    USE SIGNAL ;
    PORT
      LAYER M4 ;
        RECT  0 11.376 0.084 11.4 ;
    END
  END in_epoch[4]
  PIN in_epoch[50]
    DIRECTION INPUT ;
    USE SIGNAL ;
    PORT
      LAYER M4 ;
        RECT  0 18.864 0.084 18.888 ;
    END
  END in_epoch[50]
  PIN in_epoch[51]
    DIRECTION INPUT ;
    USE SIGNAL ;
    PORT
      LAYER M4 ;
        RECT  0 18.96 0.084 18.984 ;
    END
  END in_epoch[51]
  PIN in_epoch[52]
    DIRECTION INPUT ;
    USE SIGNAL ;
    PORT
      LAYER M4 ;
        RECT  0 19.056 0.084 19.08 ;
    END
  END in_epoch[52]
  PIN in_epoch[53]
    DIRECTION INPUT ;
    USE SIGNAL ;
    PORT
      LAYER M4 ;
        RECT  0 19.152 0.084 19.176 ;
    END
  END in_epoch[53]
  PIN in_epoch[54]
    DIRECTION INPUT ;
    USE SIGNAL ;
    PORT
      LAYER M4 ;
        RECT  0 19.248 0.084 19.272 ;
    END
  END in_epoch[54]
  PIN in_epoch[55]
    DIRECTION INPUT ;
    USE SIGNAL ;
    PORT
      LAYER M4 ;
        RECT  0 19.344 0.084 19.368 ;
    END
  END in_epoch[55]
  PIN in_epoch[56]
    DIRECTION INPUT ;
    USE SIGNAL ;
    PORT
      LAYER M4 ;
        RECT  0 19.44 0.084 19.464 ;
    END
  END in_epoch[56]
  PIN in_epoch[57]
    DIRECTION INPUT ;
    USE SIGNAL ;
    PORT
      LAYER M4 ;
        RECT  0 19.536 0.084 19.56 ;
    END
  END in_epoch[57]
  PIN in_epoch[58]
    DIRECTION INPUT ;
    USE SIGNAL ;
    PORT
      LAYER M4 ;
        RECT  0 19.632 0.084 19.656 ;
    END
  END in_epoch[58]
  PIN in_epoch[59]
    DIRECTION INPUT ;
    USE SIGNAL ;
    PORT
      LAYER M4 ;
        RECT  0 19.728 0.084 19.752 ;
    END
  END in_epoch[59]
  PIN in_epoch[5]
    DIRECTION INPUT ;
    USE SIGNAL ;
    PORT
      LAYER M4 ;
        RECT  0 11.472 0.084 11.496 ;
    END
  END in_epoch[5]
  PIN in_epoch[60]
    DIRECTION INPUT ;
    USE SIGNAL ;
    PORT
      LAYER M4 ;
        RECT  0 19.824 0.084 19.848 ;
    END
  END in_epoch[60]
  PIN in_epoch[61]
    DIRECTION INPUT ;
    USE SIGNAL ;
    PORT
      LAYER M4 ;
        RECT  0 19.92 0.084 19.944 ;
    END
  END in_epoch[61]
  PIN in_epoch[62]
    DIRECTION INPUT ;
    USE SIGNAL ;
    PORT
      LAYER M4 ;
        RECT  0 20.016 0.084 20.04 ;
    END
  END in_epoch[62]
  PIN in_epoch[63]
    DIRECTION INPUT ;
    USE SIGNAL ;
    PORT
      LAYER M4 ;
        RECT  0 20.112 0.084 20.136 ;
    END
  END in_epoch[63]
  PIN in_epoch[64]
    DIRECTION INPUT ;
    USE SIGNAL ;
    PORT
      LAYER M4 ;
        RECT  0 4.848 0.084 4.872 ;
    END
  END in_epoch[64]
  PIN in_epoch[65]
    DIRECTION INPUT ;
    USE SIGNAL ;
    PORT
      LAYER M4 ;
        RECT  0 4.944 0.084 4.968 ;
    END
  END in_epoch[65]
  PIN in_epoch[66]
    DIRECTION INPUT ;
    USE SIGNAL ;
    PORT
      LAYER M4 ;
        RECT  0 5.04 0.084 5.064 ;
    END
  END in_epoch[66]
  PIN in_epoch[67]
    DIRECTION INPUT ;
    USE SIGNAL ;
    PORT
      LAYER M4 ;
        RECT  0 5.136 0.084 5.16 ;
    END
  END in_epoch[67]
  PIN in_epoch[68]
    DIRECTION INPUT ;
    USE SIGNAL ;
    PORT
      LAYER M4 ;
        RECT  0 5.232 0.084 5.256 ;
    END
  END in_epoch[68]
  PIN in_epoch[69]
    DIRECTION INPUT ;
    USE SIGNAL ;
    PORT
      LAYER M4 ;
        RECT  0 5.328 0.084 5.352 ;
    END
  END in_epoch[69]
  PIN in_epoch[6]
    DIRECTION INPUT ;
    USE SIGNAL ;
    PORT
      LAYER M4 ;
        RECT  0 11.568 0.084 11.592 ;
    END
  END in_epoch[6]
  PIN in_epoch[70]
    DIRECTION INPUT ;
    USE SIGNAL ;
    PORT
      LAYER M4 ;
        RECT  0 5.424 0.084 5.448 ;
    END
  END in_epoch[70]
  PIN in_epoch[71]
    DIRECTION INPUT ;
    USE SIGNAL ;
    PORT
      LAYER M4 ;
        RECT  0 5.52 0.084 5.544 ;
    END
  END in_epoch[71]
  PIN in_epoch[72]
    DIRECTION INPUT ;
    USE SIGNAL ;
    PORT
      LAYER M4 ;
        RECT  0 5.616 0.084 5.64 ;
    END
  END in_epoch[72]
  PIN in_epoch[73]
    DIRECTION INPUT ;
    USE SIGNAL ;
    PORT
      LAYER M4 ;
        RECT  0 5.712 0.084 5.736 ;
    END
  END in_epoch[73]
  PIN in_epoch[74]
    DIRECTION INPUT ;
    USE SIGNAL ;
    PORT
      LAYER M4 ;
        RECT  0 5.808 0.084 5.832 ;
    END
  END in_epoch[74]
  PIN in_epoch[75]
    DIRECTION INPUT ;
    USE SIGNAL ;
    PORT
      LAYER M4 ;
        RECT  0 5.904 0.084 5.928 ;
    END
  END in_epoch[75]
  PIN in_epoch[76]
    DIRECTION INPUT ;
    USE SIGNAL ;
    PORT
      LAYER M4 ;
        RECT  0 6 0.084 6.024 ;
    END
  END in_epoch[76]
  PIN in_epoch[77]
    DIRECTION INPUT ;
    USE SIGNAL ;
    PORT
      LAYER M4 ;
        RECT  0 6.096 0.084 6.12 ;
    END
  END in_epoch[77]
  PIN in_epoch[78]
    DIRECTION INPUT ;
    USE SIGNAL ;
    PORT
      LAYER M4 ;
        RECT  0 6.192 0.084 6.216 ;
    END
  END in_epoch[78]
  PIN in_epoch[79]
    DIRECTION INPUT ;
    USE SIGNAL ;
    PORT
      LAYER M4 ;
        RECT  0 6.288 0.084 6.312 ;
    END
  END in_epoch[79]
  PIN in_epoch[7]
    DIRECTION INPUT ;
    USE SIGNAL ;
    PORT
      LAYER M4 ;
        RECT  0 11.664 0.084 11.688 ;
    END
  END in_epoch[7]
  PIN in_epoch[80]
    DIRECTION INPUT ;
    USE SIGNAL ;
    PORT
      LAYER M4 ;
        RECT  0 6.384 0.084 6.408 ;
    END
  END in_epoch[80]
  PIN in_epoch[81]
    DIRECTION INPUT ;
    USE SIGNAL ;
    PORT
      LAYER M4 ;
        RECT  0 6.48 0.084 6.504 ;
    END
  END in_epoch[81]
  PIN in_epoch[82]
    DIRECTION INPUT ;
    USE SIGNAL ;
    PORT
      LAYER M4 ;
        RECT  0 6.576 0.084 6.6 ;
    END
  END in_epoch[82]
  PIN in_epoch[83]
    DIRECTION INPUT ;
    USE SIGNAL ;
    PORT
      LAYER M4 ;
        RECT  0 6.672 0.084 6.696 ;
    END
  END in_epoch[83]
  PIN in_epoch[84]
    DIRECTION INPUT ;
    USE SIGNAL ;
    PORT
      LAYER M4 ;
        RECT  0 6.768 0.084 6.792 ;
    END
  END in_epoch[84]
  PIN in_epoch[85]
    DIRECTION INPUT ;
    USE SIGNAL ;
    PORT
      LAYER M4 ;
        RECT  0 6.864 0.084 6.888 ;
    END
  END in_epoch[85]
  PIN in_epoch[86]
    DIRECTION INPUT ;
    USE SIGNAL ;
    PORT
      LAYER M4 ;
        RECT  0 6.96 0.084 6.984 ;
    END
  END in_epoch[86]
  PIN in_epoch[87]
    DIRECTION INPUT ;
    USE SIGNAL ;
    PORT
      LAYER M4 ;
        RECT  0 7.056 0.084 7.08 ;
    END
  END in_epoch[87]
  PIN in_epoch[88]
    DIRECTION INPUT ;
    USE SIGNAL ;
    PORT
      LAYER M4 ;
        RECT  0 7.152 0.084 7.176 ;
    END
  END in_epoch[88]
  PIN in_epoch[89]
    DIRECTION INPUT ;
    USE SIGNAL ;
    PORT
      LAYER M4 ;
        RECT  0 7.248 0.084 7.272 ;
    END
  END in_epoch[89]
  PIN in_epoch[8]
    DIRECTION INPUT ;
    USE SIGNAL ;
    PORT
      LAYER M4 ;
        RECT  0 11.76 0.084 11.784 ;
    END
  END in_epoch[8]
  PIN in_epoch[90]
    DIRECTION INPUT ;
    USE SIGNAL ;
    PORT
      LAYER M4 ;
        RECT  0 7.344 0.084 7.368 ;
    END
  END in_epoch[90]
  PIN in_epoch[91]
    DIRECTION INPUT ;
    USE SIGNAL ;
    PORT
      LAYER M4 ;
        RECT  0 7.44 0.084 7.464 ;
    END
  END in_epoch[91]
  PIN in_epoch[92]
    DIRECTION INPUT ;
    USE SIGNAL ;
    PORT
      LAYER M4 ;
        RECT  0 7.536 0.084 7.56 ;
    END
  END in_epoch[92]
  PIN in_epoch[93]
    DIRECTION INPUT ;
    USE SIGNAL ;
    PORT
      LAYER M4 ;
        RECT  0 7.632 0.084 7.656 ;
    END
  END in_epoch[93]
  PIN in_epoch[94]
    DIRECTION INPUT ;
    USE SIGNAL ;
    PORT
      LAYER M4 ;
        RECT  0 7.728 0.084 7.752 ;
    END
  END in_epoch[94]
  PIN in_epoch[95]
    DIRECTION INPUT ;
    USE SIGNAL ;
    PORT
      LAYER M4 ;
        RECT  0 7.824 0.084 7.848 ;
    END
  END in_epoch[95]
  PIN in_epoch[96]
    DIRECTION INPUT ;
    USE SIGNAL ;
    PORT
      LAYER M4 ;
        RECT  0 7.92 0.084 7.944 ;
    END
  END in_epoch[96]
  PIN in_epoch[97]
    DIRECTION INPUT ;
    USE SIGNAL ;
    PORT
      LAYER M4 ;
        RECT  0 8.016 0.084 8.04 ;
    END
  END in_epoch[97]
  PIN in_epoch[98]
    DIRECTION INPUT ;
    USE SIGNAL ;
    PORT
      LAYER M4 ;
        RECT  0 8.112 0.084 8.136 ;
    END
  END in_epoch[98]
  PIN in_epoch[99]
    DIRECTION INPUT ;
    USE SIGNAL ;
    PORT
      LAYER M4 ;
        RECT  0 8.208 0.084 8.232 ;
    END
  END in_epoch[99]
  PIN in_epoch[9]
    DIRECTION INPUT ;
    USE SIGNAL ;
    PORT
      LAYER M4 ;
        RECT  0 11.856 0.084 11.88 ;
    END
  END in_epoch[9]
  PIN in_t[0]
    DIRECTION INPUT ;
    USE SIGNAL ;
    PORT
      LAYER M4 ;
        RECT  0 14.064 0.084 14.088 ;
    END
  END in_t[0]
  PIN in_t[100]
    DIRECTION INPUT ;
    USE SIGNAL ;
    PORT
      LAYER M4 ;
        RECT  0 24.432 0.084 24.456 ;
    END
  END in_t[100]
  PIN in_t[101]
    DIRECTION INPUT ;
    USE SIGNAL ;
    PORT
      LAYER M4 ;
        RECT  0 24.528 0.084 24.552 ;
    END
  END in_t[101]
  PIN in_t[102]
    DIRECTION INPUT ;
    USE SIGNAL ;
    PORT
      LAYER M4 ;
        RECT  0 24.624 0.084 24.648 ;
    END
  END in_t[102]
  PIN in_t[103]
    DIRECTION INPUT ;
    USE SIGNAL ;
    PORT
      LAYER M4 ;
        RECT  0 24.72 0.084 24.744 ;
    END
  END in_t[103]
  PIN in_t[104]
    DIRECTION INPUT ;
    USE SIGNAL ;
    PORT
      LAYER M4 ;
        RECT  0 24.816 0.084 24.84 ;
    END
  END in_t[104]
  PIN in_t[105]
    DIRECTION INPUT ;
    USE SIGNAL ;
    PORT
      LAYER M4 ;
        RECT  0 24.912 0.084 24.936 ;
    END
  END in_t[105]
  PIN in_t[106]
    DIRECTION INPUT ;
    USE SIGNAL ;
    PORT
      LAYER M4 ;
        RECT  0 25.008 0.084 25.032 ;
    END
  END in_t[106]
  PIN in_t[107]
    DIRECTION INPUT ;
    USE SIGNAL ;
    PORT
      LAYER M4 ;
        RECT  0 25.104 0.084 25.128 ;
    END
  END in_t[107]
  PIN in_t[108]
    DIRECTION INPUT ;
    USE SIGNAL ;
    PORT
      LAYER M4 ;
        RECT  0 25.2 0.084 25.224 ;
    END
  END in_t[108]
  PIN in_t[109]
    DIRECTION INPUT ;
    USE SIGNAL ;
    PORT
      LAYER M4 ;
        RECT  0 25.296 0.084 25.32 ;
    END
  END in_t[109]
  PIN in_t[10]
    DIRECTION INPUT ;
    USE SIGNAL ;
    PORT
      LAYER M4 ;
        RECT  0 15.024 0.084 15.048 ;
    END
  END in_t[10]
  PIN in_t[110]
    DIRECTION INPUT ;
    USE SIGNAL ;
    PORT
      LAYER M4 ;
        RECT  0 25.392 0.084 25.416 ;
    END
  END in_t[110]
  PIN in_t[111]
    DIRECTION INPUT ;
    USE SIGNAL ;
    PORT
      LAYER M4 ;
        RECT  0 25.488 0.084 25.512 ;
    END
  END in_t[111]
  PIN in_t[11]
    DIRECTION INPUT ;
    USE SIGNAL ;
    PORT
      LAYER M4 ;
        RECT  0 15.12 0.084 15.144 ;
    END
  END in_t[11]
  PIN in_t[12]
    DIRECTION INPUT ;
    USE SIGNAL ;
    PORT
      LAYER M4 ;
        RECT  0 15.216 0.084 15.24 ;
    END
  END in_t[12]
  PIN in_t[13]
    DIRECTION INPUT ;
    USE SIGNAL ;
    PORT
      LAYER M4 ;
        RECT  0 15.312 0.084 15.336 ;
    END
  END in_t[13]
  PIN in_t[14]
    DIRECTION INPUT ;
    USE SIGNAL ;
    PORT
      LAYER M4 ;
        RECT  0 15.408 0.084 15.432 ;
    END
  END in_t[14]
  PIN in_t[15]
    DIRECTION INPUT ;
    USE SIGNAL ;
    PORT
      LAYER M4 ;
        RECT  0 15.504 0.084 15.528 ;
    END
  END in_t[15]
  PIN in_t[16]
    DIRECTION INPUT ;
    USE SIGNAL ;
    PORT
      LAYER M4 ;
        RECT  0 15.6 0.084 15.624 ;
    END
  END in_t[16]
  PIN in_t[17]
    DIRECTION INPUT ;
    USE SIGNAL ;
    PORT
      LAYER M4 ;
        RECT  0 15.696 0.084 15.72 ;
    END
  END in_t[17]
  PIN in_t[18]
    DIRECTION INPUT ;
    USE SIGNAL ;
    PORT
      LAYER M4 ;
        RECT  0 15.792 0.084 15.816 ;
    END
  END in_t[18]
  PIN in_t[19]
    DIRECTION INPUT ;
    USE SIGNAL ;
    PORT
      LAYER M4 ;
        RECT  0 15.888 0.084 15.912 ;
    END
  END in_t[19]
  PIN in_t[1]
    DIRECTION INPUT ;
    USE SIGNAL ;
    PORT
      LAYER M4 ;
        RECT  0 14.16 0.084 14.184 ;
    END
  END in_t[1]
  PIN in_t[20]
    DIRECTION INPUT ;
    USE SIGNAL ;
    PORT
      LAYER M4 ;
        RECT  0 15.984 0.084 16.008 ;
    END
  END in_t[20]
  PIN in_t[21]
    DIRECTION INPUT ;
    USE SIGNAL ;
    PORT
      LAYER M4 ;
        RECT  0 16.08 0.084 16.104 ;
    END
  END in_t[21]
  PIN in_t[22]
    DIRECTION INPUT ;
    USE SIGNAL ;
    PORT
      LAYER M4 ;
        RECT  0 16.176 0.084 16.2 ;
    END
  END in_t[22]
  PIN in_t[23]
    DIRECTION INPUT ;
    USE SIGNAL ;
    PORT
      LAYER M4 ;
        RECT  0 16.272 0.084 16.296 ;
    END
  END in_t[23]
  PIN in_t[24]
    DIRECTION INPUT ;
    USE SIGNAL ;
    PORT
      LAYER M4 ;
        RECT  0 16.368 0.084 16.392 ;
    END
  END in_t[24]
  PIN in_t[25]
    DIRECTION INPUT ;
    USE SIGNAL ;
    PORT
      LAYER M4 ;
        RECT  0 16.464 0.084 16.488 ;
    END
  END in_t[25]
  PIN in_t[26]
    DIRECTION INPUT ;
    USE SIGNAL ;
    PORT
      LAYER M4 ;
        RECT  0 16.56 0.084 16.584 ;
    END
  END in_t[26]
  PIN in_t[27]
    DIRECTION INPUT ;
    USE SIGNAL ;
    PORT
      LAYER M4 ;
        RECT  0 16.656 0.084 16.68 ;
    END
  END in_t[27]
  PIN in_t[28]
    DIRECTION INPUT ;
    USE SIGNAL ;
    PORT
      LAYER M4 ;
        RECT  0 16.752 0.084 16.776 ;
    END
  END in_t[28]
  PIN in_t[29]
    DIRECTION INPUT ;
    USE SIGNAL ;
    PORT
      LAYER M4 ;
        RECT  0 16.848 0.084 16.872 ;
    END
  END in_t[29]
  PIN in_t[2]
    DIRECTION INPUT ;
    USE SIGNAL ;
    PORT
      LAYER M4 ;
        RECT  0 14.256 0.084 14.28 ;
    END
  END in_t[2]
  PIN in_t[30]
    DIRECTION INPUT ;
    USE SIGNAL ;
    PORT
      LAYER M4 ;
        RECT  0 16.944 0.084 16.968 ;
    END
  END in_t[30]
  PIN in_t[31]
    DIRECTION INPUT ;
    USE SIGNAL ;
    PORT
      LAYER M4 ;
        RECT  0 17.04 0.084 17.064 ;
    END
  END in_t[31]
  PIN in_t[32]
    DIRECTION INPUT ;
    USE SIGNAL ;
    PORT
      LAYER M4 ;
        RECT  0 20.208 0.084 20.232 ;
    END
  END in_t[32]
  PIN in_t[33]
    DIRECTION INPUT ;
    USE SIGNAL ;
    PORT
      LAYER M4 ;
        RECT  0 20.304 0.084 20.328 ;
    END
  END in_t[33]
  PIN in_t[34]
    DIRECTION INPUT ;
    USE SIGNAL ;
    PORT
      LAYER M4 ;
        RECT  0 20.4 0.084 20.424 ;
    END
  END in_t[34]
  PIN in_t[35]
    DIRECTION INPUT ;
    USE SIGNAL ;
    PORT
      LAYER M4 ;
        RECT  0 20.496 0.084 20.52 ;
    END
  END in_t[35]
  PIN in_t[36]
    DIRECTION INPUT ;
    USE SIGNAL ;
    PORT
      LAYER M4 ;
        RECT  0 20.592 0.084 20.616 ;
    END
  END in_t[36]
  PIN in_t[37]
    DIRECTION INPUT ;
    USE SIGNAL ;
    PORT
      LAYER M4 ;
        RECT  0 20.688 0.084 20.712 ;
    END
  END in_t[37]
  PIN in_t[38]
    DIRECTION INPUT ;
    USE SIGNAL ;
    PORT
      LAYER M4 ;
        RECT  0 20.784 0.084 20.808 ;
    END
  END in_t[38]
  PIN in_t[39]
    DIRECTION INPUT ;
    USE SIGNAL ;
    PORT
      LAYER M4 ;
        RECT  0 20.88 0.084 20.904 ;
    END
  END in_t[39]
  PIN in_t[3]
    DIRECTION INPUT ;
    USE SIGNAL ;
    PORT
      LAYER M4 ;
        RECT  0 14.352 0.084 14.376 ;
    END
  END in_t[3]
  PIN in_t[40]
    DIRECTION INPUT ;
    USE SIGNAL ;
    PORT
      LAYER M4 ;
        RECT  0 20.976 0.084 21 ;
    END
  END in_t[40]
  PIN in_t[41]
    DIRECTION INPUT ;
    USE SIGNAL ;
    PORT
      LAYER M4 ;
        RECT  0 21.072 0.084 21.096 ;
    END
  END in_t[41]
  PIN in_t[42]
    DIRECTION INPUT ;
    USE SIGNAL ;
    PORT
      LAYER M4 ;
        RECT  0 21.168 0.084 21.192 ;
    END
  END in_t[42]
  PIN in_t[43]
    DIRECTION INPUT ;
    USE SIGNAL ;
    PORT
      LAYER M4 ;
        RECT  0 21.264 0.084 21.288 ;
    END
  END in_t[43]
  PIN in_t[44]
    DIRECTION INPUT ;
    USE SIGNAL ;
    PORT
      LAYER M4 ;
        RECT  0 21.36 0.084 21.384 ;
    END
  END in_t[44]
  PIN in_t[45]
    DIRECTION INPUT ;
    USE SIGNAL ;
    PORT
      LAYER M4 ;
        RECT  0 21.456 0.084 21.48 ;
    END
  END in_t[45]
  PIN in_t[46]
    DIRECTION INPUT ;
    USE SIGNAL ;
    PORT
      LAYER M4 ;
        RECT  0 21.552 0.084 21.576 ;
    END
  END in_t[46]
  PIN in_t[47]
    DIRECTION INPUT ;
    USE SIGNAL ;
    PORT
      LAYER M4 ;
        RECT  0 21.648 0.084 21.672 ;
    END
  END in_t[47]
  PIN in_t[48]
    DIRECTION INPUT ;
    USE SIGNAL ;
    PORT
      LAYER M4 ;
        RECT  0 21.744 0.084 21.768 ;
    END
  END in_t[48]
  PIN in_t[49]
    DIRECTION INPUT ;
    USE SIGNAL ;
    PORT
      LAYER M4 ;
        RECT  0 21.84 0.084 21.864 ;
    END
  END in_t[49]
  PIN in_t[4]
    DIRECTION INPUT ;
    USE SIGNAL ;
    PORT
      LAYER M4 ;
        RECT  0 14.448 0.084 14.472 ;
    END
  END in_t[4]
  PIN in_t[50]
    DIRECTION INPUT ;
    USE SIGNAL ;
    PORT
      LAYER M4 ;
        RECT  0 21.936 0.084 21.96 ;
    END
  END in_t[50]
  PIN in_t[51]
    DIRECTION INPUT ;
    USE SIGNAL ;
    PORT
      LAYER M4 ;
        RECT  0 22.032 0.084 22.056 ;
    END
  END in_t[51]
  PIN in_t[52]
    DIRECTION INPUT ;
    USE SIGNAL ;
    PORT
      LAYER M4 ;
        RECT  0 22.128 0.084 22.152 ;
    END
  END in_t[52]
  PIN in_t[53]
    DIRECTION INPUT ;
    USE SIGNAL ;
    PORT
      LAYER M4 ;
        RECT  0 22.224 0.084 22.248 ;
    END
  END in_t[53]
  PIN in_t[54]
    DIRECTION INPUT ;
    USE SIGNAL ;
    PORT
      LAYER M4 ;
        RECT  0 22.32 0.084 22.344 ;
    END
  END in_t[54]
  PIN in_t[55]
    DIRECTION INPUT ;
    USE SIGNAL ;
    PORT
      LAYER M4 ;
        RECT  0 22.416 0.084 22.44 ;
    END
  END in_t[55]
  PIN in_t[56]
    DIRECTION INPUT ;
    USE SIGNAL ;
    PORT
      LAYER M4 ;
        RECT  0 22.512 0.084 22.536 ;
    END
  END in_t[56]
  PIN in_t[57]
    DIRECTION INPUT ;
    USE SIGNAL ;
    PORT
      LAYER M4 ;
        RECT  0 22.608 0.084 22.632 ;
    END
  END in_t[57]
  PIN in_t[58]
    DIRECTION INPUT ;
    USE SIGNAL ;
    PORT
      LAYER M4 ;
        RECT  0 22.704 0.084 22.728 ;
    END
  END in_t[58]
  PIN in_t[59]
    DIRECTION INPUT ;
    USE SIGNAL ;
    PORT
      LAYER M4 ;
        RECT  0 22.8 0.084 22.824 ;
    END
  END in_t[59]
  PIN in_t[5]
    DIRECTION INPUT ;
    USE SIGNAL ;
    PORT
      LAYER M4 ;
        RECT  0 14.544 0.084 14.568 ;
    END
  END in_t[5]
  PIN in_t[60]
    DIRECTION INPUT ;
    USE SIGNAL ;
    PORT
      LAYER M4 ;
        RECT  0 22.896 0.084 22.92 ;
    END
  END in_t[60]
  PIN in_t[61]
    DIRECTION INPUT ;
    USE SIGNAL ;
    PORT
      LAYER M4 ;
        RECT  0 22.992 0.084 23.016 ;
    END
  END in_t[61]
  PIN in_t[62]
    DIRECTION INPUT ;
    USE SIGNAL ;
    PORT
      LAYER M4 ;
        RECT  0 23.088 0.084 23.112 ;
    END
  END in_t[62]
  PIN in_t[63]
    DIRECTION INPUT ;
    USE SIGNAL ;
    PORT
      LAYER M4 ;
        RECT  0 23.184 0.084 23.208 ;
    END
  END in_t[63]
  PIN in_t[64]
    DIRECTION INPUT ;
    USE SIGNAL ;
    PORT
      LAYER M4 ;
        RECT  0 1.008 0.084 1.032 ;
    END
  END in_t[64]
  PIN in_t[65]
    DIRECTION INPUT ;
    USE SIGNAL ;
    PORT
      LAYER M4 ;
        RECT  0 1.104 0.084 1.128 ;
    END
  END in_t[65]
  PIN in_t[66]
    DIRECTION INPUT ;
    USE SIGNAL ;
    PORT
      LAYER M4 ;
        RECT  0 1.2 0.084 1.224 ;
    END
  END in_t[66]
  PIN in_t[67]
    DIRECTION INPUT ;
    USE SIGNAL ;
    PORT
      LAYER M4 ;
        RECT  0 1.296 0.084 1.32 ;
    END
  END in_t[67]
  PIN in_t[68]
    DIRECTION INPUT ;
    USE SIGNAL ;
    PORT
      LAYER M4 ;
        RECT  0 1.392 0.084 1.416 ;
    END
  END in_t[68]
  PIN in_t[69]
    DIRECTION INPUT ;
    USE SIGNAL ;
    PORT
      LAYER M4 ;
        RECT  0 1.488 0.084 1.512 ;
    END
  END in_t[69]
  PIN in_t[6]
    DIRECTION INPUT ;
    USE SIGNAL ;
    PORT
      LAYER M4 ;
        RECT  0 14.64 0.084 14.664 ;
    END
  END in_t[6]
  PIN in_t[70]
    DIRECTION INPUT ;
    USE SIGNAL ;
    PORT
      LAYER M4 ;
        RECT  0 1.584 0.084 1.608 ;
    END
  END in_t[70]
  PIN in_t[71]
    DIRECTION INPUT ;
    USE SIGNAL ;
    PORT
      LAYER M4 ;
        RECT  0 1.68 0.084 1.704 ;
    END
  END in_t[71]
  PIN in_t[72]
    DIRECTION INPUT ;
    USE SIGNAL ;
    PORT
      LAYER M4 ;
        RECT  0 1.776 0.084 1.8 ;
    END
  END in_t[72]
  PIN in_t[73]
    DIRECTION INPUT ;
    USE SIGNAL ;
    PORT
      LAYER M4 ;
        RECT  0 1.872 0.084 1.896 ;
    END
  END in_t[73]
  PIN in_t[74]
    DIRECTION INPUT ;
    USE SIGNAL ;
    PORT
      LAYER M4 ;
        RECT  0 1.968 0.084 1.992 ;
    END
  END in_t[74]
  PIN in_t[75]
    DIRECTION INPUT ;
    USE SIGNAL ;
    PORT
      LAYER M4 ;
        RECT  0 2.064 0.084 2.088 ;
    END
  END in_t[75]
  PIN in_t[76]
    DIRECTION INPUT ;
    USE SIGNAL ;
    PORT
      LAYER M4 ;
        RECT  0 2.16 0.084 2.184 ;
    END
  END in_t[76]
  PIN in_t[77]
    DIRECTION INPUT ;
    USE SIGNAL ;
    PORT
      LAYER M4 ;
        RECT  0 2.256 0.084 2.28 ;
    END
  END in_t[77]
  PIN in_t[78]
    DIRECTION INPUT ;
    USE SIGNAL ;
    PORT
      LAYER M4 ;
        RECT  0 2.352 0.084 2.376 ;
    END
  END in_t[78]
  PIN in_t[79]
    DIRECTION INPUT ;
    USE SIGNAL ;
    PORT
      LAYER M4 ;
        RECT  0 2.448 0.084 2.472 ;
    END
  END in_t[79]
  PIN in_t[7]
    DIRECTION INPUT ;
    USE SIGNAL ;
    PORT
      LAYER M4 ;
        RECT  0 14.736 0.084 14.76 ;
    END
  END in_t[7]
  PIN in_t[80]
    DIRECTION INPUT ;
    USE SIGNAL ;
    PORT
      LAYER M4 ;
        RECT  0 2.544 0.084 2.568 ;
    END
  END in_t[80]
  PIN in_t[81]
    DIRECTION INPUT ;
    USE SIGNAL ;
    PORT
      LAYER M4 ;
        RECT  0 2.64 0.084 2.664 ;
    END
  END in_t[81]
  PIN in_t[82]
    DIRECTION INPUT ;
    USE SIGNAL ;
    PORT
      LAYER M4 ;
        RECT  0 2.736 0.084 2.76 ;
    END
  END in_t[82]
  PIN in_t[83]
    DIRECTION INPUT ;
    USE SIGNAL ;
    PORT
      LAYER M4 ;
        RECT  0 2.832 0.084 2.856 ;
    END
  END in_t[83]
  PIN in_t[84]
    DIRECTION INPUT ;
    USE SIGNAL ;
    PORT
      LAYER M4 ;
        RECT  0 2.928 0.084 2.952 ;
    END
  END in_t[84]
  PIN in_t[85]
    DIRECTION INPUT ;
    USE SIGNAL ;
    PORT
      LAYER M4 ;
        RECT  0 3.024 0.084 3.048 ;
    END
  END in_t[85]
  PIN in_t[86]
    DIRECTION INPUT ;
    USE SIGNAL ;
    PORT
      LAYER M4 ;
        RECT  0 3.12 0.084 3.144 ;
    END
  END in_t[86]
  PIN in_t[87]
    DIRECTION INPUT ;
    USE SIGNAL ;
    PORT
      LAYER M4 ;
        RECT  0 3.216 0.084 3.24 ;
    END
  END in_t[87]
  PIN in_t[88]
    DIRECTION INPUT ;
    USE SIGNAL ;
    PORT
      LAYER M4 ;
        RECT  0 3.312 0.084 3.336 ;
    END
  END in_t[88]
  PIN in_t[89]
    DIRECTION INPUT ;
    USE SIGNAL ;
    PORT
      LAYER M4 ;
        RECT  0 3.408 0.084 3.432 ;
    END
  END in_t[89]
  PIN in_t[8]
    DIRECTION INPUT ;
    USE SIGNAL ;
    PORT
      LAYER M4 ;
        RECT  0 14.832 0.084 14.856 ;
    END
  END in_t[8]
  PIN in_t[90]
    DIRECTION INPUT ;
    USE SIGNAL ;
    PORT
      LAYER M4 ;
        RECT  0 3.504 0.084 3.528 ;
    END
  END in_t[90]
  PIN in_t[91]
    DIRECTION INPUT ;
    USE SIGNAL ;
    PORT
      LAYER M4 ;
        RECT  0 3.6 0.084 3.624 ;
    END
  END in_t[91]
  PIN in_t[92]
    DIRECTION INPUT ;
    USE SIGNAL ;
    PORT
      LAYER M4 ;
        RECT  0 3.696 0.084 3.72 ;
    END
  END in_t[92]
  PIN in_t[93]
    DIRECTION INPUT ;
    USE SIGNAL ;
    PORT
      LAYER M4 ;
        RECT  0 3.792 0.084 3.816 ;
    END
  END in_t[93]
  PIN in_t[94]
    DIRECTION INPUT ;
    USE SIGNAL ;
    PORT
      LAYER M4 ;
        RECT  0 3.888 0.084 3.912 ;
    END
  END in_t[94]
  PIN in_t[95]
    DIRECTION INPUT ;
    USE SIGNAL ;
    PORT
      LAYER M4 ;
        RECT  0 3.984 0.084 4.008 ;
    END
  END in_t[95]
  PIN in_t[96]
    DIRECTION INPUT ;
    USE SIGNAL ;
    PORT
      LAYER M4 ;
        RECT  0 24.048 0.084 24.072 ;
    END
  END in_t[96]
  PIN in_t[97]
    DIRECTION INPUT ;
    USE SIGNAL ;
    PORT
      LAYER M4 ;
        RECT  0 24.144 0.084 24.168 ;
    END
  END in_t[97]
  PIN in_t[98]
    DIRECTION INPUT ;
    USE SIGNAL ;
    PORT
      LAYER M4 ;
        RECT  0 24.24 0.084 24.264 ;
    END
  END in_t[98]
  PIN in_t[99]
    DIRECTION INPUT ;
    USE SIGNAL ;
    PORT
      LAYER M4 ;
        RECT  0 24.336 0.084 24.36 ;
    END
  END in_t[99]
  PIN in_t[9]
    DIRECTION INPUT ;
    USE SIGNAL ;
    PORT
      LAYER M4 ;
        RECT  0 14.928 0.084 14.952 ;
    END
  END in_t[9]
  PIN in_valid[0]
    DIRECTION INPUT ;
    USE SIGNAL ;
    PORT
      LAYER M4 ;
        RECT  0 25.584 0.084 25.608 ;
    END
  END in_valid[0]
  PIN in_valid[1]
    DIRECTION INPUT ;
    USE SIGNAL ;
    PORT
      LAYER M4 ;
        RECT  0 25.68 0.084 25.704 ;
    END
  END in_valid[1]
  PIN in_valid[2]
    DIRECTION INPUT ;
    USE SIGNAL ;
    PORT
      LAYER M4 ;
        RECT  0 25.776 0.084 25.8 ;
    END
  END in_valid[2]
  PIN in_valid[3]
    DIRECTION INPUT ;
    USE SIGNAL ;
    PORT
      LAYER M4 ;
        RECT  0 25.872 0.084 25.896 ;
    END
  END in_valid[3]
  PIN in_valid[4]
    DIRECTION INPUT ;
    USE SIGNAL ;
    PORT
      LAYER M4 ;
        RECT  0 25.968 0.084 25.992 ;
    END
  END in_valid[4]
  PIN in_valid[5]
    DIRECTION INPUT ;
    USE SIGNAL ;
    PORT
      LAYER M4 ;
        RECT  0 26.064 0.084 26.088 ;
    END
  END in_valid[5]
  PIN in_valid[6]
    DIRECTION INPUT ;
    USE SIGNAL ;
    PORT
      LAYER M4 ;
        RECT  0 26.16 0.084 26.184 ;
    END
  END in_valid[6]
  PIN in_valid[7]
    DIRECTION INPUT ;
    USE SIGNAL ;
    PORT
      LAYER M4 ;
        RECT  0 26.256 0.084 26.28 ;
    END
  END in_valid[7]
  PIN out_age[0]
    DIRECTION OUTPUT ;
    USE SIGNAL ;
    PORT
      LAYER M5 ;
        RECT  10.032 0 10.056 0.084 ;
    END
  END out_age[0]
  PIN out_age[10]
    DIRECTION OUTPUT ;
    USE SIGNAL ;
    PORT
      LAYER M5 ;
        RECT  10.992 0 11.016 0.084 ;
    END
  END out_age[10]
  PIN out_age[11]
    DIRECTION OUTPUT ;
    USE SIGNAL ;
    PORT
      LAYER M5 ;
        RECT  11.088 0 11.112 0.084 ;
    END
  END out_age[11]
  PIN out_age[12]
    DIRECTION OUTPUT ;
    USE SIGNAL ;
    PORT
      LAYER M5 ;
        RECT  11.184 0 11.208 0.084 ;
    END
  END out_age[12]
  PIN out_age[13]
    DIRECTION OUTPUT ;
    USE SIGNAL ;
    PORT
      LAYER M5 ;
        RECT  11.28 0 11.304 0.084 ;
    END
  END out_age[13]
  PIN out_age[14]
    DIRECTION OUTPUT ;
    USE SIGNAL ;
    PORT
      LAYER M5 ;
        RECT  11.376 0 11.4 0.084 ;
    END
  END out_age[14]
  PIN out_age[15]
    DIRECTION OUTPUT ;
    USE SIGNAL ;
    PORT
      LAYER M5 ;
        RECT  11.472 0 11.496 0.084 ;
    END
  END out_age[15]
  PIN out_age[1]
    DIRECTION OUTPUT ;
    USE SIGNAL ;
    PORT
      LAYER M5 ;
        RECT  10.128 0 10.152 0.084 ;
    END
  END out_age[1]
  PIN out_age[2]
    DIRECTION OUTPUT ;
    USE SIGNAL ;
    PORT
      LAYER M5 ;
        RECT  10.224 0 10.248 0.084 ;
    END
  END out_age[2]
  PIN out_age[3]
    DIRECTION OUTPUT ;
    USE SIGNAL ;
    PORT
      LAYER M5 ;
        RECT  10.32 0 10.344 0.084 ;
    END
  END out_age[3]
  PIN out_age[4]
    DIRECTION OUTPUT ;
    USE SIGNAL ;
    PORT
      LAYER M5 ;
        RECT  10.416 0 10.44 0.084 ;
    END
  END out_age[4]
  PIN out_age[5]
    DIRECTION OUTPUT ;
    USE SIGNAL ;
    PORT
      LAYER M5 ;
        RECT  10.512 0 10.536 0.084 ;
    END
  END out_age[5]
  PIN out_age[6]
    DIRECTION OUTPUT ;
    USE SIGNAL ;
    PORT
      LAYER M5 ;
        RECT  10.608 0 10.632 0.084 ;
    END
  END out_age[6]
  PIN out_age[7]
    DIRECTION OUTPUT ;
    USE SIGNAL ;
    PORT
      LAYER M5 ;
        RECT  10.704 0 10.728 0.084 ;
    END
  END out_age[7]
  PIN out_age[8]
    DIRECTION OUTPUT ;
    USE SIGNAL ;
    PORT
      LAYER M5 ;
        RECT  10.8 0 10.824 0.084 ;
    END
  END out_age[8]
  PIN out_age[9]
    DIRECTION OUTPUT ;
    USE SIGNAL ;
    PORT
      LAYER M5 ;
        RECT  10.896 0 10.92 0.084 ;
    END
  END out_age[9]
  PIN out_epoch[0]
    DIRECTION OUTPUT ;
    USE SIGNAL ;
    PORT
      LAYER M5 ;
        RECT  11.568 0 11.592 0.084 ;
    END
  END out_epoch[0]
  PIN out_epoch[10]
    DIRECTION OUTPUT ;
    USE SIGNAL ;
    PORT
      LAYER M5 ;
        RECT  12.528 0 12.552 0.084 ;
    END
  END out_epoch[10]
  PIN out_epoch[11]
    DIRECTION OUTPUT ;
    USE SIGNAL ;
    PORT
      LAYER M5 ;
        RECT  12.624 0 12.648 0.084 ;
    END
  END out_epoch[11]
  PIN out_epoch[12]
    DIRECTION OUTPUT ;
    USE SIGNAL ;
    PORT
      LAYER M5 ;
        RECT  12.72 0 12.744 0.084 ;
    END
  END out_epoch[12]
  PIN out_epoch[13]
    DIRECTION OUTPUT ;
    USE SIGNAL ;
    PORT
      LAYER M5 ;
        RECT  12.816 0 12.84 0.084 ;
    END
  END out_epoch[13]
  PIN out_epoch[14]
    DIRECTION OUTPUT ;
    USE SIGNAL ;
    PORT
      LAYER M5 ;
        RECT  12.912 0 12.936 0.084 ;
    END
  END out_epoch[14]
  PIN out_epoch[15]
    DIRECTION OUTPUT ;
    USE SIGNAL ;
    PORT
      LAYER M5 ;
        RECT  13.008 0 13.032 0.084 ;
    END
  END out_epoch[15]
  PIN out_epoch[1]
    DIRECTION OUTPUT ;
    USE SIGNAL ;
    PORT
      LAYER M5 ;
        RECT  11.664 0 11.688 0.084 ;
    END
  END out_epoch[1]
  PIN out_epoch[2]
    DIRECTION OUTPUT ;
    USE SIGNAL ;
    PORT
      LAYER M5 ;
        RECT  11.76 0 11.784 0.084 ;
    END
  END out_epoch[2]
  PIN out_epoch[3]
    DIRECTION OUTPUT ;
    USE SIGNAL ;
    PORT
      LAYER M5 ;
        RECT  11.856 0 11.88 0.084 ;
    END
  END out_epoch[3]
  PIN out_epoch[4]
    DIRECTION OUTPUT ;
    USE SIGNAL ;
    PORT
      LAYER M5 ;
        RECT  11.952 0 11.976 0.084 ;
    END
  END out_epoch[4]
  PIN out_epoch[5]
    DIRECTION OUTPUT ;
    USE SIGNAL ;
    PORT
      LAYER M5 ;
        RECT  12.048 0 12.072 0.084 ;
    END
  END out_epoch[5]
  PIN out_epoch[6]
    DIRECTION OUTPUT ;
    USE SIGNAL ;
    PORT
      LAYER M5 ;
        RECT  12.144 0 12.168 0.084 ;
    END
  END out_epoch[6]
  PIN out_epoch[7]
    DIRECTION OUTPUT ;
    USE SIGNAL ;
    PORT
      LAYER M5 ;
        RECT  12.24 0 12.264 0.084 ;
    END
  END out_epoch[7]
  PIN out_epoch[8]
    DIRECTION OUTPUT ;
    USE SIGNAL ;
    PORT
      LAYER M5 ;
        RECT  12.336 0 12.36 0.084 ;
    END
  END out_epoch[8]
  PIN out_epoch[9]
    DIRECTION OUTPUT ;
    USE SIGNAL ;
    PORT
      LAYER M5 ;
        RECT  12.432 0 12.456 0.084 ;
    END
  END out_epoch[9]
  PIN pair_id
    DIRECTION INPUT ;
    USE SIGNAL ;
    PORT
      LAYER M5 ;
        RECT  13.104 0 13.128 0.084 ;
    END
  END pair_id
  PIN req_t[0]
    DIRECTION OUTPUT ;
    USE SIGNAL ;
    PORT
      LAYER M4 ;
        RECT  43.116 29.904 43.2 29.928 ;
    END
  END req_t[0]
  PIN req_t[100]
    DIRECTION OUTPUT ;
    USE SIGNAL ;
    PORT
      LAYER M4 ;
        RECT  43.116 36.432 43.2 36.456 ;
    END
  END req_t[100]
  PIN req_t[101]
    DIRECTION OUTPUT ;
    USE SIGNAL ;
    PORT
      LAYER M4 ;
        RECT  43.116 36.528 43.2 36.552 ;
    END
  END req_t[101]
  PIN req_t[102]
    DIRECTION OUTPUT ;
    USE SIGNAL ;
    PORT
      LAYER M4 ;
        RECT  43.116 36.624 43.2 36.648 ;
    END
  END req_t[102]
  PIN req_t[103]
    DIRECTION OUTPUT ;
    USE SIGNAL ;
    PORT
      LAYER M4 ;
        RECT  43.116 36.72 43.2 36.744 ;
    END
  END req_t[103]
  PIN req_t[104]
    DIRECTION OUTPUT ;
    USE SIGNAL ;
    PORT
      LAYER M4 ;
        RECT  43.116 36.816 43.2 36.84 ;
    END
  END req_t[104]
  PIN req_t[105]
    DIRECTION OUTPUT ;
    USE SIGNAL ;
    PORT
      LAYER M4 ;
        RECT  43.116 36.912 43.2 36.936 ;
    END
  END req_t[105]
  PIN req_t[106]
    DIRECTION OUTPUT ;
    USE SIGNAL ;
    PORT
      LAYER M4 ;
        RECT  43.116 37.008 43.2 37.032 ;
    END
  END req_t[106]
  PIN req_t[107]
    DIRECTION OUTPUT ;
    USE SIGNAL ;
    PORT
      LAYER M4 ;
        RECT  43.116 37.104 43.2 37.128 ;
    END
  END req_t[107]
  PIN req_t[108]
    DIRECTION OUTPUT ;
    USE SIGNAL ;
    PORT
      LAYER M4 ;
        RECT  43.116 37.2 43.2 37.224 ;
    END
  END req_t[108]
  PIN req_t[109]
    DIRECTION OUTPUT ;
    USE SIGNAL ;
    PORT
      LAYER M4 ;
        RECT  43.116 37.296 43.2 37.32 ;
    END
  END req_t[109]
  PIN req_t[10]
    DIRECTION OUTPUT ;
    USE SIGNAL ;
    PORT
      LAYER M4 ;
        RECT  43.116 30.864 43.2 30.888 ;
    END
  END req_t[10]
  PIN req_t[110]
    DIRECTION OUTPUT ;
    USE SIGNAL ;
    PORT
      LAYER M4 ;
        RECT  43.116 37.392 43.2 37.416 ;
    END
  END req_t[110]
  PIN req_t[111]
    DIRECTION OUTPUT ;
    USE SIGNAL ;
    PORT
      LAYER M4 ;
        RECT  43.116 37.488 43.2 37.512 ;
    END
  END req_t[111]
  PIN req_t[11]
    DIRECTION OUTPUT ;
    USE SIGNAL ;
    PORT
      LAYER M4 ;
        RECT  43.116 30.96 43.2 30.984 ;
    END
  END req_t[11]
  PIN req_t[12]
    DIRECTION OUTPUT ;
    USE SIGNAL ;
    PORT
      LAYER M4 ;
        RECT  43.116 31.056 43.2 31.08 ;
    END
  END req_t[12]
  PIN req_t[13]
    DIRECTION OUTPUT ;
    USE SIGNAL ;
    PORT
      LAYER M4 ;
        RECT  43.116 31.152 43.2 31.176 ;
    END
  END req_t[13]
  PIN req_t[14]
    DIRECTION OUTPUT ;
    USE SIGNAL ;
    PORT
      LAYER M4 ;
        RECT  43.116 31.248 43.2 31.272 ;
    END
  END req_t[14]
  PIN req_t[15]
    DIRECTION OUTPUT ;
    USE SIGNAL ;
    PORT
      LAYER M4 ;
        RECT  43.116 31.344 43.2 31.368 ;
    END
  END req_t[15]
  PIN req_t[16]
    DIRECTION OUTPUT ;
    USE SIGNAL ;
    PORT
      LAYER M4 ;
        RECT  43.116 31.44 43.2 31.464 ;
    END
  END req_t[16]
  PIN req_t[17]
    DIRECTION OUTPUT ;
    USE SIGNAL ;
    PORT
      LAYER M4 ;
        RECT  43.116 31.536 43.2 31.56 ;
    END
  END req_t[17]
  PIN req_t[18]
    DIRECTION OUTPUT ;
    USE SIGNAL ;
    PORT
      LAYER M4 ;
        RECT  43.116 31.632 43.2 31.656 ;
    END
  END req_t[18]
  PIN req_t[19]
    DIRECTION OUTPUT ;
    USE SIGNAL ;
    PORT
      LAYER M4 ;
        RECT  43.116 31.728 43.2 31.752 ;
    END
  END req_t[19]
  PIN req_t[1]
    DIRECTION OUTPUT ;
    USE SIGNAL ;
    PORT
      LAYER M4 ;
        RECT  43.116 30 43.2 30.024 ;
    END
  END req_t[1]
  PIN req_t[20]
    DIRECTION OUTPUT ;
    USE SIGNAL ;
    PORT
      LAYER M4 ;
        RECT  43.116 31.824 43.2 31.848 ;
    END
  END req_t[20]
  PIN req_t[21]
    DIRECTION OUTPUT ;
    USE SIGNAL ;
    PORT
      LAYER M4 ;
        RECT  43.116 31.92 43.2 31.944 ;
    END
  END req_t[21]
  PIN req_t[22]
    DIRECTION OUTPUT ;
    USE SIGNAL ;
    PORT
      LAYER M4 ;
        RECT  43.116 32.016 43.2 32.04 ;
    END
  END req_t[22]
  PIN req_t[23]
    DIRECTION OUTPUT ;
    USE SIGNAL ;
    PORT
      LAYER M4 ;
        RECT  43.116 32.112 43.2 32.136 ;
    END
  END req_t[23]
  PIN req_t[24]
    DIRECTION OUTPUT ;
    USE SIGNAL ;
    PORT
      LAYER M4 ;
        RECT  43.116 32.208 43.2 32.232 ;
    END
  END req_t[24]
  PIN req_t[25]
    DIRECTION OUTPUT ;
    USE SIGNAL ;
    PORT
      LAYER M4 ;
        RECT  43.116 32.304 43.2 32.328 ;
    END
  END req_t[25]
  PIN req_t[26]
    DIRECTION OUTPUT ;
    USE SIGNAL ;
    PORT
      LAYER M4 ;
        RECT  43.116 32.4 43.2 32.424 ;
    END
  END req_t[26]
  PIN req_t[27]
    DIRECTION OUTPUT ;
    USE SIGNAL ;
    PORT
      LAYER M4 ;
        RECT  43.116 32.496 43.2 32.52 ;
    END
  END req_t[27]
  PIN req_t[28]
    DIRECTION OUTPUT ;
    USE SIGNAL ;
    PORT
      LAYER M4 ;
        RECT  43.116 32.592 43.2 32.616 ;
    END
  END req_t[28]
  PIN req_t[29]
    DIRECTION OUTPUT ;
    USE SIGNAL ;
    PORT
      LAYER M4 ;
        RECT  43.116 32.688 43.2 32.712 ;
    END
  END req_t[29]
  PIN req_t[2]
    DIRECTION OUTPUT ;
    USE SIGNAL ;
    PORT
      LAYER M4 ;
        RECT  43.116 30.096 43.2 30.12 ;
    END
  END req_t[2]
  PIN req_t[30]
    DIRECTION OUTPUT ;
    USE SIGNAL ;
    PORT
      LAYER M4 ;
        RECT  43.116 32.784 43.2 32.808 ;
    END
  END req_t[30]
  PIN req_t[31]
    DIRECTION OUTPUT ;
    USE SIGNAL ;
    PORT
      LAYER M4 ;
        RECT  43.116 32.88 43.2 32.904 ;
    END
  END req_t[31]
  PIN req_t[32]
    DIRECTION OUTPUT ;
    USE SIGNAL ;
    PORT
      LAYER M4 ;
        RECT  43.116 32.976 43.2 33 ;
    END
  END req_t[32]
  PIN req_t[33]
    DIRECTION OUTPUT ;
    USE SIGNAL ;
    PORT
      LAYER M4 ;
        RECT  43.116 33.072 43.2 33.096 ;
    END
  END req_t[33]
  PIN req_t[34]
    DIRECTION OUTPUT ;
    USE SIGNAL ;
    PORT
      LAYER M4 ;
        RECT  43.116 33.168 43.2 33.192 ;
    END
  END req_t[34]
  PIN req_t[35]
    DIRECTION OUTPUT ;
    USE SIGNAL ;
    PORT
      LAYER M4 ;
        RECT  43.116 33.264 43.2 33.288 ;
    END
  END req_t[35]
  PIN req_t[36]
    DIRECTION OUTPUT ;
    USE SIGNAL ;
    PORT
      LAYER M4 ;
        RECT  43.116 33.36 43.2 33.384 ;
    END
  END req_t[36]
  PIN req_t[37]
    DIRECTION OUTPUT ;
    USE SIGNAL ;
    PORT
      LAYER M4 ;
        RECT  43.116 33.456 43.2 33.48 ;
    END
  END req_t[37]
  PIN req_t[38]
    DIRECTION OUTPUT ;
    USE SIGNAL ;
    PORT
      LAYER M4 ;
        RECT  43.116 33.552 43.2 33.576 ;
    END
  END req_t[38]
  PIN req_t[39]
    DIRECTION OUTPUT ;
    USE SIGNAL ;
    PORT
      LAYER M4 ;
        RECT  43.116 33.648 43.2 33.672 ;
    END
  END req_t[39]
  PIN req_t[3]
    DIRECTION OUTPUT ;
    USE SIGNAL ;
    PORT
      LAYER M4 ;
        RECT  43.116 30.192 43.2 30.216 ;
    END
  END req_t[3]
  PIN req_t[40]
    DIRECTION OUTPUT ;
    USE SIGNAL ;
    PORT
      LAYER M4 ;
        RECT  43.116 33.744 43.2 33.768 ;
    END
  END req_t[40]
  PIN req_t[41]
    DIRECTION OUTPUT ;
    USE SIGNAL ;
    PORT
      LAYER M4 ;
        RECT  43.116 33.84 43.2 33.864 ;
    END
  END req_t[41]
  PIN req_t[42]
    DIRECTION OUTPUT ;
    USE SIGNAL ;
    PORT
      LAYER M4 ;
        RECT  43.116 33.936 43.2 33.96 ;
    END
  END req_t[42]
  PIN req_t[43]
    DIRECTION OUTPUT ;
    USE SIGNAL ;
    PORT
      LAYER M4 ;
        RECT  43.116 34.032 43.2 34.056 ;
    END
  END req_t[43]
  PIN req_t[44]
    DIRECTION OUTPUT ;
    USE SIGNAL ;
    PORT
      LAYER M4 ;
        RECT  43.116 34.128 43.2 34.152 ;
    END
  END req_t[44]
  PIN req_t[45]
    DIRECTION OUTPUT ;
    USE SIGNAL ;
    PORT
      LAYER M4 ;
        RECT  43.116 34.224 43.2 34.248 ;
    END
  END req_t[45]
  PIN req_t[46]
    DIRECTION OUTPUT ;
    USE SIGNAL ;
    PORT
      LAYER M4 ;
        RECT  43.116 34.32 43.2 34.344 ;
    END
  END req_t[46]
  PIN req_t[47]
    DIRECTION OUTPUT ;
    USE SIGNAL ;
    PORT
      LAYER M4 ;
        RECT  43.116 34.416 43.2 34.44 ;
    END
  END req_t[47]
  PIN req_t[48]
    DIRECTION OUTPUT ;
    USE SIGNAL ;
    PORT
      LAYER M4 ;
        RECT  43.116 34.512 43.2 34.536 ;
    END
  END req_t[48]
  PIN req_t[49]
    DIRECTION OUTPUT ;
    USE SIGNAL ;
    PORT
      LAYER M4 ;
        RECT  43.116 34.608 43.2 34.632 ;
    END
  END req_t[49]
  PIN req_t[4]
    DIRECTION OUTPUT ;
    USE SIGNAL ;
    PORT
      LAYER M4 ;
        RECT  43.116 30.288 43.2 30.312 ;
    END
  END req_t[4]
  PIN req_t[50]
    DIRECTION OUTPUT ;
    USE SIGNAL ;
    PORT
      LAYER M4 ;
        RECT  43.116 34.704 43.2 34.728 ;
    END
  END req_t[50]
  PIN req_t[51]
    DIRECTION OUTPUT ;
    USE SIGNAL ;
    PORT
      LAYER M4 ;
        RECT  43.116 34.8 43.2 34.824 ;
    END
  END req_t[51]
  PIN req_t[52]
    DIRECTION OUTPUT ;
    USE SIGNAL ;
    PORT
      LAYER M4 ;
        RECT  43.116 34.896 43.2 34.92 ;
    END
  END req_t[52]
  PIN req_t[53]
    DIRECTION OUTPUT ;
    USE SIGNAL ;
    PORT
      LAYER M4 ;
        RECT  43.116 34.992 43.2 35.016 ;
    END
  END req_t[53]
  PIN req_t[54]
    DIRECTION OUTPUT ;
    USE SIGNAL ;
    PORT
      LAYER M4 ;
        RECT  43.116 35.088 43.2 35.112 ;
    END
  END req_t[54]
  PIN req_t[55]
    DIRECTION OUTPUT ;
    USE SIGNAL ;
    PORT
      LAYER M4 ;
        RECT  43.116 35.184 43.2 35.208 ;
    END
  END req_t[55]
  PIN req_t[56]
    DIRECTION OUTPUT ;
    USE SIGNAL ;
    PORT
      LAYER M4 ;
        RECT  43.116 39.12 43.2 39.144 ;
    END
  END req_t[56]
  PIN req_t[57]
    DIRECTION OUTPUT ;
    USE SIGNAL ;
    PORT
      LAYER M4 ;
        RECT  43.116 39.216 43.2 39.24 ;
    END
  END req_t[57]
  PIN req_t[58]
    DIRECTION OUTPUT ;
    USE SIGNAL ;
    PORT
      LAYER M4 ;
        RECT  43.116 39.312 43.2 39.336 ;
    END
  END req_t[58]
  PIN req_t[59]
    DIRECTION OUTPUT ;
    USE SIGNAL ;
    PORT
      LAYER M4 ;
        RECT  43.116 39.408 43.2 39.432 ;
    END
  END req_t[59]
  PIN req_t[5]
    DIRECTION OUTPUT ;
    USE SIGNAL ;
    PORT
      LAYER M4 ;
        RECT  43.116 30.384 43.2 30.408 ;
    END
  END req_t[5]
  PIN req_t[60]
    DIRECTION OUTPUT ;
    USE SIGNAL ;
    PORT
      LAYER M4 ;
        RECT  43.116 39.504 43.2 39.528 ;
    END
  END req_t[60]
  PIN req_t[61]
    DIRECTION OUTPUT ;
    USE SIGNAL ;
    PORT
      LAYER M4 ;
        RECT  43.116 39.6 43.2 39.624 ;
    END
  END req_t[61]
  PIN req_t[62]
    DIRECTION OUTPUT ;
    USE SIGNAL ;
    PORT
      LAYER M4 ;
        RECT  43.116 39.696 43.2 39.72 ;
    END
  END req_t[62]
  PIN req_t[63]
    DIRECTION OUTPUT ;
    USE SIGNAL ;
    PORT
      LAYER M4 ;
        RECT  43.116 39.792 43.2 39.816 ;
    END
  END req_t[63]
  PIN req_t[64]
    DIRECTION OUTPUT ;
    USE SIGNAL ;
    PORT
      LAYER M4 ;
        RECT  43.116 39.888 43.2 39.912 ;
    END
  END req_t[64]
  PIN req_t[65]
    DIRECTION OUTPUT ;
    USE SIGNAL ;
    PORT
      LAYER M4 ;
        RECT  43.116 39.984 43.2 40.008 ;
    END
  END req_t[65]
  PIN req_t[66]
    DIRECTION OUTPUT ;
    USE SIGNAL ;
    PORT
      LAYER M4 ;
        RECT  43.116 40.08 43.2 40.104 ;
    END
  END req_t[66]
  PIN req_t[67]
    DIRECTION OUTPUT ;
    USE SIGNAL ;
    PORT
      LAYER M4 ;
        RECT  43.116 40.176 43.2 40.2 ;
    END
  END req_t[67]
  PIN req_t[68]
    DIRECTION OUTPUT ;
    USE SIGNAL ;
    PORT
      LAYER M4 ;
        RECT  43.116 40.272 43.2 40.296 ;
    END
  END req_t[68]
  PIN req_t[69]
    DIRECTION OUTPUT ;
    USE SIGNAL ;
    PORT
      LAYER M4 ;
        RECT  43.116 40.368 43.2 40.392 ;
    END
  END req_t[69]
  PIN req_t[6]
    DIRECTION OUTPUT ;
    USE SIGNAL ;
    PORT
      LAYER M4 ;
        RECT  43.116 30.48 43.2 30.504 ;
    END
  END req_t[6]
  PIN req_t[70]
    DIRECTION OUTPUT ;
    USE SIGNAL ;
    PORT
      LAYER M4 ;
        RECT  43.116 40.464 43.2 40.488 ;
    END
  END req_t[70]
  PIN req_t[71]
    DIRECTION OUTPUT ;
    USE SIGNAL ;
    PORT
      LAYER M4 ;
        RECT  43.116 40.56 43.2 40.584 ;
    END
  END req_t[71]
  PIN req_t[72]
    DIRECTION OUTPUT ;
    USE SIGNAL ;
    PORT
      LAYER M4 ;
        RECT  43.116 40.656 43.2 40.68 ;
    END
  END req_t[72]
  PIN req_t[73]
    DIRECTION OUTPUT ;
    USE SIGNAL ;
    PORT
      LAYER M4 ;
        RECT  43.116 40.752 43.2 40.776 ;
    END
  END req_t[73]
  PIN req_t[74]
    DIRECTION OUTPUT ;
    USE SIGNAL ;
    PORT
      LAYER M4 ;
        RECT  43.116 40.848 43.2 40.872 ;
    END
  END req_t[74]
  PIN req_t[75]
    DIRECTION OUTPUT ;
    USE SIGNAL ;
    PORT
      LAYER M4 ;
        RECT  43.116 40.944 43.2 40.968 ;
    END
  END req_t[75]
  PIN req_t[76]
    DIRECTION OUTPUT ;
    USE SIGNAL ;
    PORT
      LAYER M4 ;
        RECT  43.116 41.04 43.2 41.064 ;
    END
  END req_t[76]
  PIN req_t[77]
    DIRECTION OUTPUT ;
    USE SIGNAL ;
    PORT
      LAYER M4 ;
        RECT  43.116 41.136 43.2 41.16 ;
    END
  END req_t[77]
  PIN req_t[78]
    DIRECTION OUTPUT ;
    USE SIGNAL ;
    PORT
      LAYER M4 ;
        RECT  43.116 41.232 43.2 41.256 ;
    END
  END req_t[78]
  PIN req_t[79]
    DIRECTION OUTPUT ;
    USE SIGNAL ;
    PORT
      LAYER M4 ;
        RECT  43.116 41.328 43.2 41.352 ;
    END
  END req_t[79]
  PIN req_t[7]
    DIRECTION OUTPUT ;
    USE SIGNAL ;
    PORT
      LAYER M4 ;
        RECT  43.116 30.576 43.2 30.6 ;
    END
  END req_t[7]
  PIN req_t[80]
    DIRECTION OUTPUT ;
    USE SIGNAL ;
    PORT
      LAYER M4 ;
        RECT  43.116 41.424 43.2 41.448 ;
    END
  END req_t[80]
  PIN req_t[81]
    DIRECTION OUTPUT ;
    USE SIGNAL ;
    PORT
      LAYER M4 ;
        RECT  43.116 41.52 43.2 41.544 ;
    END
  END req_t[81]
  PIN req_t[82]
    DIRECTION OUTPUT ;
    USE SIGNAL ;
    PORT
      LAYER M4 ;
        RECT  43.116 41.616 43.2 41.64 ;
    END
  END req_t[82]
  PIN req_t[83]
    DIRECTION OUTPUT ;
    USE SIGNAL ;
    PORT
      LAYER M4 ;
        RECT  43.116 41.712 43.2 41.736 ;
    END
  END req_t[83]
  PIN req_t[84]
    DIRECTION OUTPUT ;
    USE SIGNAL ;
    PORT
      LAYER M4 ;
        RECT  43.116 41.808 43.2 41.832 ;
    END
  END req_t[84]
  PIN req_t[85]
    DIRECTION OUTPUT ;
    USE SIGNAL ;
    PORT
      LAYER M4 ;
        RECT  43.116 41.904 43.2 41.928 ;
    END
  END req_t[85]
  PIN req_t[86]
    DIRECTION OUTPUT ;
    USE SIGNAL ;
    PORT
      LAYER M4 ;
        RECT  43.116 42 43.2 42.024 ;
    END
  END req_t[86]
  PIN req_t[87]
    DIRECTION OUTPUT ;
    USE SIGNAL ;
    PORT
      LAYER M4 ;
        RECT  43.116 42.096 43.2 42.12 ;
    END
  END req_t[87]
  PIN req_t[88]
    DIRECTION OUTPUT ;
    USE SIGNAL ;
    PORT
      LAYER M4 ;
        RECT  43.116 35.28 43.2 35.304 ;
    END
  END req_t[88]
  PIN req_t[89]
    DIRECTION OUTPUT ;
    USE SIGNAL ;
    PORT
      LAYER M4 ;
        RECT  43.116 35.376 43.2 35.4 ;
    END
  END req_t[89]
  PIN req_t[8]
    DIRECTION OUTPUT ;
    USE SIGNAL ;
    PORT
      LAYER M4 ;
        RECT  43.116 30.672 43.2 30.696 ;
    END
  END req_t[8]
  PIN req_t[90]
    DIRECTION OUTPUT ;
    USE SIGNAL ;
    PORT
      LAYER M4 ;
        RECT  43.116 35.472 43.2 35.496 ;
    END
  END req_t[90]
  PIN req_t[91]
    DIRECTION OUTPUT ;
    USE SIGNAL ;
    PORT
      LAYER M4 ;
        RECT  43.116 35.568 43.2 35.592 ;
    END
  END req_t[91]
  PIN req_t[92]
    DIRECTION OUTPUT ;
    USE SIGNAL ;
    PORT
      LAYER M4 ;
        RECT  43.116 35.664 43.2 35.688 ;
    END
  END req_t[92]
  PIN req_t[93]
    DIRECTION OUTPUT ;
    USE SIGNAL ;
    PORT
      LAYER M4 ;
        RECT  43.116 35.76 43.2 35.784 ;
    END
  END req_t[93]
  PIN req_t[94]
    DIRECTION OUTPUT ;
    USE SIGNAL ;
    PORT
      LAYER M4 ;
        RECT  43.116 35.856 43.2 35.88 ;
    END
  END req_t[94]
  PIN req_t[95]
    DIRECTION OUTPUT ;
    USE SIGNAL ;
    PORT
      LAYER M4 ;
        RECT  43.116 35.952 43.2 35.976 ;
    END
  END req_t[95]
  PIN req_t[96]
    DIRECTION OUTPUT ;
    USE SIGNAL ;
    PORT
      LAYER M4 ;
        RECT  43.116 36.048 43.2 36.072 ;
    END
  END req_t[96]
  PIN req_t[97]
    DIRECTION OUTPUT ;
    USE SIGNAL ;
    PORT
      LAYER M4 ;
        RECT  43.116 36.144 43.2 36.168 ;
    END
  END req_t[97]
  PIN req_t[98]
    DIRECTION OUTPUT ;
    USE SIGNAL ;
    PORT
      LAYER M4 ;
        RECT  43.116 36.24 43.2 36.264 ;
    END
  END req_t[98]
  PIN req_t[99]
    DIRECTION OUTPUT ;
    USE SIGNAL ;
    PORT
      LAYER M4 ;
        RECT  43.116 36.336 43.2 36.36 ;
    END
  END req_t[99]
  PIN req_t[9]
    DIRECTION OUTPUT ;
    USE SIGNAL ;
    PORT
      LAYER M4 ;
        RECT  43.116 30.768 43.2 30.792 ;
    END
  END req_t[9]
  PIN req_valid[0]
    DIRECTION OUTPUT ;
    USE SIGNAL ;
    PORT
      LAYER M4 ;
        RECT  43.116 37.584 43.2 37.608 ;
    END
  END req_valid[0]
  PIN req_valid[1]
    DIRECTION OUTPUT ;
    USE SIGNAL ;
    PORT
      LAYER M4 ;
        RECT  43.116 37.68 43.2 37.704 ;
    END
  END req_valid[1]
  PIN req_valid[2]
    DIRECTION OUTPUT ;
    USE SIGNAL ;
    PORT
      LAYER M4 ;
        RECT  43.116 37.776 43.2 37.8 ;
    END
  END req_valid[2]
  PIN req_valid[3]
    DIRECTION OUTPUT ;
    USE SIGNAL ;
    PORT
      LAYER M4 ;
        RECT  43.116 37.872 43.2 37.896 ;
    END
  END req_valid[3]
  PIN req_valid[4]
    DIRECTION OUTPUT ;
    USE SIGNAL ;
    PORT
      LAYER M4 ;
        RECT  43.116 37.968 43.2 37.992 ;
    END
  END req_valid[4]
  PIN req_valid[5]
    DIRECTION OUTPUT ;
    USE SIGNAL ;
    PORT
      LAYER M4 ;
        RECT  43.116 38.064 43.2 38.088 ;
    END
  END req_valid[5]
  PIN req_valid[6]
    DIRECTION OUTPUT ;
    USE SIGNAL ;
    PORT
      LAYER M4 ;
        RECT  43.116 38.16 43.2 38.184 ;
    END
  END req_valid[6]
  PIN req_valid[7]
    DIRECTION OUTPUT ;
    USE SIGNAL ;
    PORT
      LAYER M4 ;
        RECT  43.116 38.256 43.2 38.28 ;
    END
  END req_valid[7]
  PIN rst_n
    DIRECTION INPUT ;
    USE SIGNAL ;
    PORT
      LAYER M5 ;
        RECT  13.2 0 13.224 0.084 ;
    END
  END rst_n
  PIN start
    DIRECTION INPUT ;
    USE SIGNAL ;
    PORT
      LAYER M5 ;
        RECT  13.296 0 13.32 0.084 ;
    END
  END start
  PIN VDD
    DIRECTION INOUT ;
    USE POWER ;
    PORT
      LAYER M5 ;
        RECT  40.392 2.151 40.512 41.049 ;
        RECT  34.992 2.151 35.112 41.049 ;
        RECT  29.592 2.151 29.712 41.049 ;
        RECT  24.192 2.151 24.312 41.049 ;
        RECT  18.792 2.151 18.912 41.049 ;
        RECT  13.392 2.151 13.512 41.049 ;
        RECT  7.992 2.151 8.112 41.049 ;
        RECT  2.592 2.151 2.712 41.049 ;
    END
  END VDD
  PIN VSS
    DIRECTION INOUT ;
    USE GROUND ;
    PORT
      LAYER M5 ;
        RECT  40.2 2.137 40.32 41.063 ;
        RECT  34.8 2.137 34.92 41.063 ;
        RECT  29.4 2.137 29.52 41.063 ;
        RECT  24 2.137 24.12 41.063 ;
        RECT  18.6 2.137 18.72 41.063 ;
        RECT  13.2 2.137 13.32 41.063 ;
        RECT  7.8 2.137 7.92 41.063 ;
        RECT  2.4 2.137 2.52 41.063 ;
    END
  END VSS
  # OT_OBS_CLOSED layer=M5 d_um=1.536 added=160
  OBS
    LAYER RVTN ;
     RECT  2.16 2.16 41.04 2.295 ;
     RECT  2.16 2.565 41.04 2.835 ;
     RECT  2.16 3.105 41.04 3.375 ;
     RECT  2.16 3.645 41.04 3.915 ;
     RECT  2.16 4.185 41.04 4.455 ;
     RECT  2.16 4.725 41.04 4.995 ;
     RECT  2.16 5.265 41.04 5.535 ;
     RECT  2.16 5.805 41.04 6.075 ;
     RECT  2.16 6.345 41.04 6.615 ;
     RECT  2.16 6.885 41.04 7.155 ;
     RECT  2.16 7.425 41.04 7.695 ;
     RECT  2.16 7.965 41.04 8.235 ;
     RECT  2.16 8.505 41.04 8.775 ;
     RECT  2.16 9.045 41.04 9.315 ;
     RECT  2.16 9.585 41.04 9.855 ;
     RECT  2.16 10.125 41.04 10.395 ;
     RECT  2.16 10.665 41.04 10.935 ;
     RECT  2.16 11.205 41.04 11.475 ;
     RECT  2.16 11.745 41.04 12.015 ;
     RECT  2.16 12.285 41.04 12.555 ;
     RECT  2.16 12.825 41.04 13.095 ;
     RECT  2.16 13.365 41.04 13.635 ;
     RECT  2.16 13.905 41.04 14.175 ;
     RECT  2.16 14.445 41.04 14.715 ;
     RECT  2.16 14.985 41.04 15.255 ;
     RECT  2.16 15.525 41.04 15.795 ;
     RECT  2.16 16.065 41.04 16.335 ;
     RECT  2.16 16.605 41.04 16.875 ;
     RECT  2.16 17.145 41.04 17.415 ;
     RECT  2.16 17.685 41.04 17.955 ;
     RECT  2.16 18.225 41.04 18.495 ;
     RECT  2.16 18.765 41.04 19.035 ;
     RECT  2.16 19.305 41.04 19.575 ;
     RECT  2.16 19.845 41.04 20.115 ;
     RECT  2.16 20.385 41.04 20.655 ;
     RECT  2.16 20.925 41.04 21.195 ;
     RECT  2.16 21.465 41.04 21.735 ;
     RECT  2.16 22.005 41.04 22.275 ;
     RECT  2.16 22.545 41.04 22.815 ;
     RECT  2.16 23.085 41.04 23.355 ;
     RECT  2.16 23.625 41.04 23.895 ;
     RECT  2.16 24.165 41.04 24.435 ;
     RECT  2.16 24.705 41.04 24.975 ;
     RECT  2.16 25.245 41.04 25.515 ;
     RECT  2.16 25.785 41.04 26.055 ;
     RECT  2.16 26.325 41.04 26.595 ;
     RECT  2.16 26.865 41.04 27.135 ;
     RECT  2.16 27.405 41.04 27.675 ;
     RECT  2.16 27.945 41.04 28.215 ;
     RECT  2.16 28.485 41.04 28.755 ;
     RECT  2.16 29.025 41.04 29.295 ;
     RECT  2.16 29.565 41.04 29.835 ;
     RECT  2.16 30.105 41.04 30.375 ;
     RECT  2.16 30.645 41.04 30.915 ;
     RECT  2.16 31.185 41.04 31.455 ;
     RECT  2.16 31.725 41.04 31.995 ;
     RECT  2.16 32.265 41.04 32.535 ;
     RECT  2.16 32.805 41.04 33.075 ;
     RECT  2.16 33.345 41.04 33.615 ;
     RECT  2.16 33.885 41.04 34.155 ;
     RECT  2.16 34.425 41.04 34.695 ;
     RECT  2.16 34.965 41.04 35.235 ;
     RECT  2.16 35.505 41.04 35.775 ;
     RECT  2.16 36.045 41.04 36.315 ;
     RECT  2.16 36.585 41.04 36.855 ;
     RECT  2.16 37.125 41.04 37.395 ;
     RECT  2.16 37.665 41.04 37.935 ;
     RECT  2.16 38.205 41.04 38.475 ;
     RECT  2.16 38.745 41.04 39.015 ;
     RECT  2.16 39.285 41.04 39.555 ;
     RECT  2.16 39.825 41.04 40.095 ;
     RECT  2.16 40.365 41.04 40.635 ;
     RECT  2.16 40.905 41.04 41.04 ;
    LAYER RVTP ;
     RECT  2.16 2.295 41.04 2.565 ;
     RECT  2.16 2.835 41.04 3.105 ;
     RECT  2.16 3.375 41.04 3.645 ;
     RECT  2.16 3.915 41.04 4.185 ;
     RECT  2.16 4.455 41.04 4.725 ;
     RECT  2.16 4.995 41.04 5.265 ;
     RECT  2.16 5.535 41.04 5.805 ;
     RECT  2.16 6.075 41.04 6.345 ;
     RECT  2.16 6.615 41.04 6.885 ;
     RECT  2.16 7.155 41.04 7.425 ;
     RECT  2.16 7.695 41.04 7.965 ;
     RECT  2.16 8.235 41.04 8.505 ;
     RECT  2.16 8.775 41.04 9.045 ;
     RECT  2.16 9.315 41.04 9.585 ;
     RECT  2.16 9.855 41.04 10.125 ;
     RECT  2.16 10.395 41.04 10.665 ;
     RECT  2.16 10.935 41.04 11.205 ;
     RECT  2.16 11.475 41.04 11.745 ;
     RECT  2.16 12.015 41.04 12.285 ;
     RECT  2.16 12.555 41.04 12.825 ;
     RECT  2.16 13.095 41.04 13.365 ;
     RECT  2.16 13.635 41.04 13.905 ;
     RECT  2.16 14.175 41.04 14.445 ;
     RECT  2.16 14.715 41.04 14.985 ;
     RECT  2.16 15.255 41.04 15.525 ;
     RECT  2.16 15.795 41.04 16.065 ;
     RECT  2.16 16.335 41.04 16.605 ;
     RECT  2.16 16.875 41.04 17.145 ;
     RECT  2.16 17.415 41.04 17.685 ;
     RECT  2.16 17.955 41.04 18.225 ;
     RECT  2.16 18.495 41.04 18.765 ;
     RECT  2.16 19.035 41.04 19.305 ;
     RECT  2.16 19.575 41.04 19.845 ;
     RECT  2.16 20.115 41.04 20.385 ;
     RECT  2.16 20.655 41.04 20.925 ;
     RECT  2.16 21.195 41.04 21.465 ;
     RECT  2.16 21.735 41.04 22.005 ;
     RECT  2.16 22.275 41.04 22.545 ;
     RECT  2.16 22.815 41.04 23.085 ;
     RECT  2.16 23.355 41.04 23.625 ;
     RECT  2.16 23.895 41.04 24.165 ;
     RECT  2.16 24.435 41.04 24.705 ;
     RECT  2.16 24.975 41.04 25.245 ;
     RECT  2.16 25.515 41.04 25.785 ;
     RECT  2.16 26.055 41.04 26.325 ;
     RECT  2.16 26.595 41.04 26.865 ;
     RECT  2.16 27.135 41.04 27.405 ;
     RECT  2.16 27.675 41.04 27.945 ;
     RECT  2.16 28.215 41.04 28.485 ;
     RECT  2.16 28.755 41.04 29.025 ;
     RECT  2.16 29.295 41.04 29.565 ;
     RECT  2.16 29.835 41.04 30.105 ;
     RECT  2.16 30.375 41.04 30.645 ;
     RECT  2.16 30.915 41.04 31.185 ;
     RECT  2.16 31.455 41.04 31.725 ;
     RECT  2.16 31.995 41.04 32.265 ;
     RECT  2.16 32.535 41.04 32.805 ;
     RECT  2.16 33.075 41.04 33.345 ;
     RECT  2.16 33.615 41.04 33.885 ;
     RECT  2.16 34.155 41.04 34.425 ;
     RECT  2.16 34.695 41.04 34.965 ;
     RECT  2.16 35.235 41.04 35.505 ;
     RECT  2.16 35.775 41.04 36.045 ;
     RECT  2.16 36.315 41.04 36.585 ;
     RECT  2.16 36.855 41.04 37.125 ;
     RECT  2.16 37.395 41.04 37.665 ;
     RECT  2.16 37.935 41.04 38.205 ;
     RECT  2.16 38.475 41.04 38.745 ;
     RECT  2.16 39.015 41.04 39.285 ;
     RECT  2.16 39.555 41.04 39.825 ;
     RECT  2.16 40.095 41.04 40.365 ;
     RECT  2.16 40.635 41.04 40.905 ;
    LAYER M1 ;
     RECT  2.16 2.151 41.04 41.049 ;
    LAYER M2 ;
     RECT  0.103 17.082 0.139 17.1 ;
     RECT  0.139 2.772 0.175 2.934 ;
     RECT  0.139 10.17 0.211 10.188 ;
     RECT  0.103 14.958 0.211 14.976 ;
     RECT  0.103 5.976 0.239 5.994 ;
     RECT  0.211 9.936 0.247 10.188 ;
     RECT  0.247 9.936 0.347 10.386 ;
     RECT  0.103 24.714 0.347 24.732 ;
     RECT  0.211 14.652 0.383 14.976 ;
     RECT  0.103 7.236 0.499 7.254 ;
     RECT  0.247 8.586 0.535 8.604 ;
     RECT  0.175 2.538 0.563 2.934 ;
     RECT  0.563 2.916 0.707 2.934 ;
     RECT  0.139 17.082 1.147 17.478 ;
     RECT  0.535 21.24 1.147 21.258 ;
     RECT  0.535 15.3 1.363 15.318 ;
     RECT  1.147 21.132 1.363 21.258 ;
     RECT  1.147 5.238 1.687 5.256 ;
     RECT  0.499 7.236 1.723 7.416 ;
     RECT  0.535 8.28 1.723 8.604 ;
     RECT  0.103 12.024 1.723 13.086 ;
     RECT  0.103 18.774 1.723 18.792 ;
     RECT  1.723 18.54 1.759 18.792 ;
     RECT  1.363 21.132 2.155 21.798 ;
     RECT  0.103 22.59 2.155 22.608 ;
     RECT  2.155 2.808 2.16 2.826 ;
     RECT  0.103 3.996 2.16 4.014 ;
     RECT  1.687 5.238 2.16 5.598 ;
     RECT  0.535 6.354 2.16 6.372 ;
     RECT  1.723 7.236 2.16 8.604 ;
     RECT  1.399 9.36 2.16 9.378 ;
     RECT  0.347 10.17 2.16 10.386 ;
     RECT  1.723 11.556 2.16 13.086 ;
     RECT  1.363 14.76 2.16 15.318 ;
     RECT  1.147 16.92 2.16 17.478 ;
     RECT  1.759 18.306 2.16 18.792 ;
     RECT  2.155 21.132 2.16 22.608 ;
     RECT  0.535 23.67 2.16 23.688 ;
     RECT  2.16 2.151 2.731 41.049 ;
     RECT  2.731 2.034 5.135 41.049 ;
     RECT  5.135 2.106 11.407 41.049 ;
     RECT  11.407 1.422 12.559 41.049 ;
     RECT  12.559 0.846 16.475 41.049 ;
     RECT  16.475 1.422 17.915 41.049 ;
     RECT  17.915 2.07 19.067 41.049 ;
     RECT  19.067 2.106 20.363 41.049 ;
     RECT  20.363 2.151 26.563 41.049 ;
     RECT  26.167 41.886 26.563 41.904 ;
     RECT  26.563 2.151 30.199 41.904 ;
     RECT  30.199 2.151 41.04 41.94 ;
     RECT  41.04 23.796 41.135 34.722 ;
     RECT  41.135 33.12 41.351 34.452 ;
     RECT  41.351 34.362 41.459 34.38 ;
     RECT  41.135 23.796 41.531 32.364 ;
     RECT  41.531 23.796 41.603 25.74 ;
     RECT  41.603 23.796 41.855 24.804 ;
     RECT  41.855 23.796 41.927 23.814 ;
     RECT  41.855 24.786 41.999 24.804 ;
     RECT  41.351 33.12 41.999 33.138 ;
     RECT  41.531 26.568 42.035 32.364 ;
     RECT  41.603 25.596 42.107 25.74 ;
     RECT  41.04 40.536 42.143 41.94 ;
     RECT  42.035 27.414 42.179 32.364 ;
     RECT  41.04 39.762 42.179 39.78 ;
     RECT  42.143 40.95 42.179 41.94 ;
     RECT  42.179 30.816 42.215 32.364 ;
     RECT  42.179 27.414 42.719 30.06 ;
     RECT  42.215 31.77 42.727 32.364 ;
     RECT  42.719 29.844 42.791 30.06 ;
     RECT  42.727 31.77 42.835 32.49 ;
     RECT  42.215 30.816 42.863 30.942 ;
     RECT  42.791 29.844 42.899 29.898 ;
     RECT  42.719 27.414 42.935 28.98 ;
     RECT  42.935 27.756 42.971 28.98 ;
     RECT  42.691 34.506 42.979 34.524 ;
     RECT  42.971 27.756 43.007 28.044 ;
     RECT  42.863 30.852 43.007 30.942 ;
     RECT  42.835 31.77 43.007 32.679 ;
     RECT  42.979 34.506 43.043 34.686 ;
     RECT  42.979 38.826 43.051 38.844 ;
     RECT  42.107 25.641 43.079 25.74 ;
     RECT  42.971 28.881 43.079 28.98 ;
     RECT  43.007 30.852 43.079 30.87 ;
     RECT  42.899 29.88 43.115 29.898 ;
     RECT  43.007 32.346 43.115 32.679 ;
     RECT  43.051 38.754 43.115 38.844 ;
     RECT  42.179 41.076 43.115 41.94 ;
     RECT  42.035 26.568 43.151 26.586 ;
     RECT  43.007 27.756 43.151 27.864 ;
     RECT  43.043 34.668 43.151 34.686 ;
     RECT  43.051 35.442 43.151 35.46 ;
     RECT  43.115 38.754 43.151 38.772 ;
     RECT  43.079 25.641 43.187 25.659 ;
     RECT  43.115 41.796 43.187 41.814 ;
    LAYER M3 ;
     RECT  10.62 0.043 10.638 0.091 ;
     RECT  13.032 0.043 13.05 0.091 ;
     RECT  8.28 0.091 8.298 0.139 ;
     RECT  16.776 0.091 16.794 0.139 ;
     RECT  8.28 0.139 8.442 0.187 ;
     RECT  13.032 0.091 13.482 0.187 ;
     RECT  10.62 0.091 10.854 0.221 ;
     RECT  10.836 0.221 10.854 0.235 ;
     RECT  13.032 0.187 13.698 0.235 ;
     RECT  8.28 0.187 8.514 0.269 ;
     RECT  10.836 0.235 11.214 0.269 ;
     RECT  11.196 0.269 11.214 0.283 ;
     RECT  8.424 0.269 8.514 0.317 ;
     RECT  8.496 0.317 8.514 0.365 ;
     RECT  16.776 0.139 16.866 0.841 ;
     RECT  16.452 0.841 16.866 0.859 ;
     RECT  17.748 0.811 17.766 0.859 ;
     RECT  14.976 0.379 14.994 1.147 ;
     RECT  12.42 0.235 13.698 1.175 ;
     RECT  19.98 0.043 19.998 1.387 ;
     RECT  16.452 0.859 17.766 1.417 ;
     RECT  11.196 0.283 11.43 1.723 ;
     RECT  8.136 1.675 8.154 1.771 ;
     RECT  9.108 1.723 9.558 1.771 ;
     RECT  8.136 1.771 9.774 1.819 ;
     RECT  10.728 1.723 11.646 1.819 ;
     RECT  12.42 1.175 13.554 1.957 ;
     RECT  7.056 1.723 7.074 1.963 ;
     RECT  8.136 1.819 11.646 1.963 ;
     RECT  5.112 2.029 5.13 2.059 ;
     RECT  19.944 1.387 19.998 2.059 ;
     RECT  14.724 1.147 14.994 2.065 ;
     RECT  16.452 1.417 17.91 2.065 ;
     RECT  7.056 1.963 11.646 2.101 ;
     RECT  19.044 2.065 19.062 2.101 ;
     RECT  19.944 2.059 20.034 2.101 ;
     RECT  2.736 2.029 2.754 2.143 ;
     RECT  14.724 2.065 17.91 2.143 ;
     RECT  18.828 2.101 19.062 2.143 ;
     RECT  2.415 2.143 2.754 2.155 ;
     RECT  2.304 2.155 2.754 2.191 ;
     RECT  4.392 2.059 5.13 2.191 ;
     RECT  6.048 2.101 11.646 2.191 ;
     RECT  12.42 1.957 13.95 2.191 ;
     RECT  14.724 2.143 19.062 2.191 ;
     RECT  2.304 2.191 5.13 2.227 ;
     RECT  6.048 2.191 19.062 2.227 ;
     RECT  2.304 2.227 19.062 2.335 ;
     RECT  0.108 1.963 0.126 2.347 ;
     RECT  24.015 2.143 24.105 2.413 ;
     RECT  29.415 2.143 29.505 2.413 ;
     RECT  34.815 2.143 34.905 2.413 ;
     RECT  40.215 2.143 40.305 2.413 ;
     RECT  19.944 2.101 20.358 2.489 ;
     RECT  2.304 2.335 19.098 2.533 ;
     RECT  2.304 2.533 19.17 2.633 ;
     RECT  2.304 2.633 18.897 2.683 ;
     RECT  0.108 2.347 0.558 2.731 ;
     RECT  2.232 2.683 18.897 2.731 ;
     RECT  19.98 2.489 20.358 2.759 ;
     RECT  2.16 2.731 18.897 2.831 ;
     RECT  20.34 2.759 20.358 2.839 ;
     RECT  20.34 2.839 20.43 2.867 ;
     RECT  0.108 2.731 0.594 2.911 ;
     RECT  2.232 2.831 18.897 3.137 ;
     RECT  0.108 2.911 0.702 3.163 ;
     RECT  0.108 3.163 1.17 3.341 ;
     RECT  2.304 3.137 18.897 3.569 ;
     RECT  0.108 3.341 0.342 3.917 ;
     RECT  1.152 3.341 1.17 3.991 ;
     RECT  2.304 3.569 17.874 3.991 ;
     RECT  0.108 3.917 0.162 4.019 ;
     RECT  0.144 4.019 0.162 4.493 ;
     RECT  1.152 3.991 17.874 4.657 ;
     RECT  18.615 3.569 18.897 4.657 ;
     RECT  22.176 3.109 22.194 4.801 ;
     RECT  29.415 2.413 29.697 4.891 ;
     RECT  20.412 2.867 20.43 5.161 ;
     RECT  1.152 4.657 18.897 5.261 ;
     RECT  1.404 5.261 18.897 5.464 ;
     RECT  1.404 5.464 18.99 5.503 ;
     RECT  19.98 5.161 20.43 5.503 ;
     RECT  27.936 5.341 27.954 5.503 ;
     RECT  1.404 5.503 20.43 5.603 ;
     RECT  26.352 2.533 26.37 5.611 ;
     RECT  21.348 4.765 21.366 5.845 ;
     RECT  22.176 4.801 22.698 5.845 ;
     RECT  0.144 5.323 0.162 5.851 ;
     RECT  0.144 5.851 0.234 5.899 ;
     RECT  0.144 5.899 0.342 5.971 ;
     RECT  27.936 5.503 28.278 6.007 ;
     RECT  0.108 5.971 0.342 6.029 ;
     RECT  26.28 5.611 26.37 6.091 ;
     RECT  27.432 6.007 28.278 6.091 ;
     RECT  1.404 5.603 20.358 6.107 ;
     RECT  21.348 5.845 22.698 6.107 ;
     RECT  19.98 6.107 20.358 6.385 ;
     RECT  19.98 6.385 20.466 6.421 ;
     RECT  19.98 6.421 20.61 6.511 ;
     RECT  21.348 6.107 21.366 6.511 ;
     RECT  24.015 2.413 24.297 6.781 ;
     RECT  25.38 5.971 25.398 6.781 ;
     RECT  24.015 6.781 25.398 6.817 ;
     RECT  26.28 6.091 28.278 6.817 ;
     RECT  22.176 6.107 22.698 6.853 ;
     RECT  29.415 4.891 30.258 6.853 ;
     RECT  1.404 6.107 19.242 6.925 ;
     RECT  19.98 6.511 21.366 6.925 ;
     RECT  22.176 6.853 22.842 6.925 ;
     RECT  0.54 6.349 0.558 6.955 ;
     RECT  1.404 6.925 22.842 6.961 ;
     RECT  0.216 6.955 0.558 7.147 ;
     RECT  0.108 7.147 0.558 7.195 ;
     RECT  1.404 6.961 22.914 7.195 ;
     RECT  24.015 6.817 28.278 7.195 ;
     RECT  0.108 7.195 22.914 7.259 ;
     RECT  0.18 7.259 22.914 7.321 ;
     RECT  0.18 7.321 22.95 7.357 ;
     RECT  23.94 7.195 28.278 7.357 ;
     RECT  0.18 7.357 28.278 7.373 ;
     RECT  0.18 7.373 0.558 7.421 ;
     RECT  0.468 7.421 0.558 7.469 ;
     RECT  29.415 6.853 30.366 7.501 ;
     RECT  1.404 7.373 28.278 7.735 ;
     RECT  0.468 7.469 0.522 7.853 ;
     RECT  29.268 7.501 30.366 8.311 ;
     RECT  1.404 7.735 28.35 8.401 ;
     RECT  0.54 8.275 0.558 8.581 ;
     RECT  31.932 8.473 31.95 8.699 ;
     RECT  0.252 8.581 0.558 8.731 ;
     RECT  1.404 8.401 28.494 8.765 ;
     RECT  2.268 8.765 28.494 8.807 ;
     RECT  29.232 8.311 30.366 8.815 ;
     RECT  29.232 8.815 30.762 8.851 ;
     RECT  2.304 8.807 28.494 9.085 ;
     RECT  29.232 8.851 31.446 9.085 ;
     RECT  0.18 8.731 0.558 9.293 ;
     RECT  1.404 8.765 1.422 9.383 ;
     RECT  0.18 9.293 0.342 9.547 ;
     RECT  0.108 9.547 0.342 10.027 ;
     RECT  0.108 10.027 0.378 10.166 ;
     RECT  2.304 9.085 31.446 10.201 ;
     RECT  32.292 9.661 32.31 10.201 ;
     RECT  2.304 10.201 32.31 10.363 ;
     RECT  2.304 10.363 32.418 10.589 ;
     RECT  2.304 10.589 32.346 10.651 ;
     RECT  2.268 10.651 32.346 10.747 ;
     RECT  1.728 10.747 32.346 10.859 ;
     RECT  0.108 10.166 0.342 11.179 ;
     RECT  0.108 11.179 0.378 11.309 ;
     RECT  1.728 10.859 32.31 11.579 ;
     RECT  2.232 11.579 32.31 11.777 ;
     RECT  0.108 11.309 0.342 11.981 ;
     RECT  2.34 11.777 32.31 12.619 ;
     RECT  33.624 12.631 33.642 12.749 ;
     RECT  2.304 12.619 32.31 12.757 ;
     RECT  2.304 12.757 33.066 12.901 ;
     RECT  0.108 11.981 0.126 13.229 ;
     RECT  0.144 13.675 0.162 14.059 ;
     RECT  2.268 12.901 33.066 14.207 ;
     RECT  2.304 14.207 33.066 14.485 ;
     RECT  2.304 14.485 33.174 14.639 ;
     RECT  1.368 12.235 1.386 14.783 ;
     RECT  2.304 14.639 32.814 14.909 ;
     RECT  0.144 14.059 0.378 14.923 ;
     RECT  0.108 14.923 0.378 14.981 ;
     RECT  2.304 14.909 32.274 15.067 ;
     RECT  0.18 14.981 0.378 15.295 ;
     RECT  0.18 15.295 0.558 15.437 ;
     RECT  1.764 15.067 32.274 15.491 ;
     RECT  33.228 15.601 33.246 15.691 ;
     RECT  33.12 15.691 33.246 15.719 ;
     RECT  0.18 15.437 0.342 15.787 ;
     RECT  0.144 15.787 0.342 15.821 ;
     RECT  0.144 15.821 0.234 15.917 ;
     RECT  0.144 15.917 0.162 15.965 ;
     RECT  1.764 15.491 32.238 16.747 ;
     RECT  1.728 16.747 32.238 16.807 ;
     RECT  33.12 15.719 33.138 16.807 ;
     RECT  1.728 16.807 33.138 16.915 ;
     RECT  0.108 17.077 0.126 17.083 ;
     RECT  1.152 16.915 33.138 17.117 ;
     RECT  0.108 17.083 0.162 17.645 ;
     RECT  0.144 17.645 0.162 18.379 ;
     RECT  1.728 17.117 33.138 18.527 ;
     RECT  1.728 18.527 27.774 18.563 ;
     RECT  28.512 18.527 33.138 18.571 ;
     RECT  0.144 18.379 0.342 18.769 ;
     RECT  28.512 18.571 33.246 18.841 ;
     RECT  34.02 16.501 34.038 18.841 ;
     RECT  0.108 18.769 0.342 18.989 ;
     RECT  0.108 18.989 0.234 19.181 ;
     RECT  0.108 19.181 0.162 19.277 ;
     RECT  2.304 18.563 27.774 19.345 ;
     RECT  28.512 18.841 34.038 19.345 ;
     RECT  1.152 19.339 1.17 19.819 ;
     RECT  0.144 19.277 0.162 19.949 ;
     RECT  0.216 19.963 0.234 20.011 ;
     RECT  0.216 20.011 0.342 20.141 ;
     RECT  1.152 19.819 1.386 20.491 ;
     RECT  2.304 19.345 34.038 20.491 ;
     RECT  34.815 2.413 35.097 20.893 ;
     RECT  0.324 20.141 0.342 20.909 ;
     RECT  1.152 20.491 34.038 21.155 ;
     RECT  1.368 21.155 34.038 21.497 ;
     RECT  40.215 2.413 40.497 21.499 ;
     RECT  40.104 21.499 40.497 21.541 ;
     RECT  39.456 21.541 40.59 21.595 ;
     RECT  38.808 21.595 40.59 21.631 ;
     RECT  38.808 21.631 40.986 21.677 ;
     RECT  1.368 21.497 1.386 21.803 ;
     RECT  2.16 21.497 34.038 21.965 ;
     RECT  0.54 21.235 0.558 22.061 ;
     RECT  39.06 21.677 40.986 22.109 ;
     RECT  38.268 22.081 38.286 22.157 ;
     RECT  39.06 22.109 39.078 22.205 ;
     RECT  39.888 22.109 40.986 22.205 ;
     RECT  2.232 21.965 34.038 22.351 ;
     RECT  34.815 20.893 35.298 22.351 ;
     RECT  0.144 22.267 0.162 22.445 ;
     RECT  38.772 22.747 38.79 22.784 ;
     RECT  0.108 22.585 0.126 23.021 ;
     RECT  38.808 23.161 39.15 23.323 ;
     RECT  39.924 22.205 40.986 23.323 ;
     RECT  2.232 22.351 35.298 23.387 ;
     RECT  38.808 23.323 40.986 23.701 ;
     RECT  38.412 23.701 40.986 23.971 ;
     RECT  2.304 23.387 35.298 24.205 ;
     RECT  0.54 23.665 0.558 24.235 ;
     RECT  38.268 23.971 40.986 24.241 ;
     RECT  0.54 24.235 1.17 24.413 ;
     RECT  0.54 24.413 0.558 24.461 ;
     RECT  41.904 23.791 41.922 24.475 ;
     RECT  38.196 24.241 40.986 24.601 ;
     RECT  0.324 24.523 0.342 24.619 ;
     RECT  0.108 24.619 0.342 24.737 ;
     RECT  0.18 24.737 0.342 24.749 ;
     RECT  38.052 24.601 40.986 24.781 ;
     RECT  41.832 24.475 41.922 24.781 ;
     RECT  2.268 24.205 35.298 24.845 ;
     RECT  38.016 24.781 40.986 24.943 ;
     RECT  41.832 24.781 41.994 24.943 ;
     RECT  0.18 24.749 0.198 25.085 ;
     RECT  36.792 21.541 36.81 25.213 ;
     RECT  36.684 25.213 36.81 25.285 ;
     RECT  38.016 24.943 41.994 25.555 ;
     RECT  37.908 25.555 41.994 25.591 ;
     RECT  43.164 25.636 43.182 25.717 ;
     RECT  2.304 24.845 35.298 25.867 ;
     RECT  2.268 25.867 35.298 26.023 ;
     RECT  36.468 25.285 36.81 26.023 ;
     RECT  37.908 25.591 42.102 26.023 ;
     RECT  0.324 25.675 0.342 26.059 ;
     RECT  2.268 26.023 35.73 26.087 ;
     RECT  0.144 26.059 0.342 26.093 ;
     RECT  2.304 26.087 35.73 26.123 ;
     RECT  0.144 26.093 0.162 26.237 ;
     RECT  25.092 26.123 35.73 26.699 ;
     RECT  25.164 26.699 35.73 26.761 ;
     RECT  36.468 26.023 42.102 26.761 ;
     RECT  2.304 26.123 24.354 26.789 ;
     RECT  2.304 26.789 24.297 27.329 ;
     RECT  2.415 27.329 24.297 27.365 ;
     RECT  43.056 25.717 43.182 27.409 ;
     RECT  25.164 26.761 42.102 27.751 ;
     RECT  42.912 27.409 43.182 27.751 ;
     RECT  2.415 27.365 15.102 27.869 ;
     RECT  2.415 27.869 2.754 27.917 ;
     RECT  3.564 27.869 4.194 27.941 ;
     RECT  25.164 27.751 43.182 27.985 ;
     RECT  3.672 27.941 4.194 28.049 ;
     RECT  4.032 28.049 4.194 28.139 ;
     RECT  4.968 27.869 15.102 28.139 ;
     RECT  15.84 27.365 24.297 28.147 ;
     RECT  25.128 27.985 43.182 28.147 ;
     RECT  4.032 28.139 4.05 28.175 ;
     RECT  5.544 28.139 15.102 28.175 ;
     RECT  7.776 28.175 15.102 28.247 ;
     RECT  7.815 28.247 15.102 28.255 ;
     RECT  15.84 28.147 43.182 28.255 ;
     RECT  5.544 28.175 6.786 28.409 ;
     RECT  7.815 28.255 43.182 28.553 ;
     RECT  5.544 28.409 5.706 28.679 ;
     RECT  6.48 28.409 6.498 28.679 ;
     RECT  5.544 28.679 5.562 28.715 ;
     RECT  7.815 28.553 10.674 28.823 ;
     RECT  11.484 28.553 43.182 28.823 ;
     RECT  12.996 28.823 43.182 28.829 ;
     RECT  8.82 28.823 10.674 28.859 ;
     RECT  8.856 28.859 10.098 28.949 ;
     RECT  12.996 28.829 17.406 29.021 ;
     RECT  8.892 28.949 10.098 29.057 ;
     RECT  12.996 29.021 17.334 29.057 ;
     RECT  12.996 29.057 17.082 29.069 ;
     RECT  9.504 29.057 9.702 29.093 ;
     RECT  11.484 28.823 12.258 29.129 ;
     RECT  11.484 29.129 11.502 29.255 ;
     RECT  12.24 29.129 12.258 29.363 ;
     RECT  13.032 29.069 17.082 29.525 ;
     RECT  13.068 29.525 17.082 29.633 ;
     RECT  13.176 29.633 17.082 29.839 ;
     RECT  18.144 28.829 43.182 29.839 ;
     RECT  13.176 29.839 43.182 30.379 ;
     RECT  13.068 30.379 43.182 30.415 ;
     RECT  12.456 30.415 43.182 31.145 ;
     RECT  9.504 29.093 9.522 31.379 ;
     RECT  12.6 31.145 43.182 31.793 ;
     RECT  12.6 31.793 23.274 31.805 ;
     RECT  24.015 31.793 43.182 31.805 ;
     RECT  26.028 31.805 43.182 31.829 ;
     RECT  24.015 31.805 25.218 31.901 ;
     RECT  24.015 31.901 25.146 31.919 ;
     RECT  12.6 31.805 22.914 32.881 ;
     RECT  26.172 31.829 43.182 33.067 ;
     RECT  25.704 33.067 43.182 33.341 ;
     RECT  12.6 32.881 23.13 33.539 ;
     RECT  12.6 33.539 22.446 33.581 ;
     RECT  28.512 33.341 43.182 33.611 ;
     RECT  28.62 33.611 43.182 33.683 ;
     RECT  25.704 33.341 27.666 33.809 ;
     RECT  24.015 31.919 24.297 33.961 ;
     RECT  17.1 33.581 22.446 34.079 ;
     RECT  24.015 33.961 24.75 34.079 ;
     RECT  25.848 33.809 27.666 34.115 ;
     RECT  25.848 34.115 25.866 34.151 ;
     RECT  26.784 34.115 27.666 34.159 ;
     RECT  23.22 34.231 23.238 34.349 ;
     RECT  12.6 33.581 16.362 34.357 ;
     RECT  17.676 34.079 22.446 34.357 ;
     RECT  11.952 34.357 16.362 34.591 ;
     RECT  10.8 34.627 10.818 34.699 ;
     RECT  11.88 34.591 16.362 34.699 ;
     RECT  26.784 34.159 27.846 34.735 ;
     RECT  28.656 33.683 43.182 34.735 ;
     RECT  9.972 34.501 9.99 34.897 ;
     RECT  26.784 34.735 43.182 34.969 ;
     RECT  9.864 34.897 9.99 35.041 ;
     RECT  10.8 34.699 16.362 35.041 ;
     RECT  26.64 34.969 43.182 35.453 ;
     RECT  17.676 34.357 22.842 35.563 ;
     RECT  9.864 35.041 16.938 35.581 ;
     RECT  9.792 35.581 16.938 35.815 ;
     RECT  17.676 35.563 22.986 35.815 ;
     RECT  9.792 35.815 22.986 35.851 ;
     RECT  7.815 28.823 8.097 35.947 ;
     RECT  7.815 35.947 8.19 36.013 ;
     RECT  9.36 35.851 22.986 36.013 ;
     RECT  7.815 36.013 22.986 36.091 ;
     RECT  26.856 35.453 43.182 36.235 ;
     RECT  7.74 36.091 22.986 36.419 ;
     RECT  7.74 36.419 17.73 36.461 ;
     RECT  26.82 36.235 43.182 36.661 ;
     RECT  7.812 36.461 17.73 36.689 ;
     RECT  18.615 36.419 22.986 36.823 ;
     RECT  18.615 36.823 23.094 37.049 ;
     RECT  7.812 36.689 17.622 37.085 ;
     RECT  7.812 37.085 17.55 37.091 ;
     RECT  7.812 37.091 17.334 37.133 ;
     RECT  18.615 37.049 22.194 37.235 ;
     RECT  25.524 37.291 25.542 37.373 ;
     RECT  18.615 37.235 22.158 37.463 ;
     RECT  18.615 37.463 22.122 37.589 ;
     RECT  23.22 37.201 23.238 37.589 ;
     RECT  18.615 37.589 22.086 37.931 ;
     RECT  26.496 36.661 43.182 37.997 ;
     RECT  26.496 37.997 42.21 38.011 ;
     RECT  18.615 37.931 21.618 38.039 ;
     RECT  25.956 38.011 42.21 38.039 ;
     RECT  7.815 37.133 17.334 38.101 ;
     RECT  18.615 38.039 21.51 38.129 ;
     RECT  18.615 38.129 19.062 38.165 ;
     RECT  7.2 38.101 17.334 38.281 ;
     RECT  26.82 38.039 42.21 38.285 ;
     RECT  19.836 38.129 21.33 38.399 ;
     RECT  19.836 38.399 21.114 38.435 ;
     RECT  24.015 34.079 24.297 38.443 ;
     RECT  25.092 38.251 25.11 38.443 ;
     RECT  18.615 38.165 18.897 38.479 ;
     RECT  20.232 38.435 21.114 38.507 ;
     RECT  7.164 38.281 17.334 38.515 ;
     RECT  18.252 38.479 18.897 38.515 ;
     RECT  20.232 38.507 20.25 38.543 ;
     RECT  21.096 38.507 21.114 38.543 ;
     RECT  24.015 38.443 25.11 38.551 ;
     RECT  25.956 38.039 26.046 38.551 ;
     RECT  7.164 38.515 18.897 38.683 ;
     RECT  43.092 37.997 43.182 38.749 ;
     RECT  24.015 38.551 26.046 38.821 ;
     RECT  26.82 38.285 41.994 38.821 ;
     RECT  43.056 38.749 43.182 38.821 ;
     RECT  24.015 38.821 41.994 39.499 ;
     RECT  7.02 38.683 18.897 39.785 ;
     RECT  24.015 39.499 42.174 39.785 ;
     RECT  7.2 39.785 18.897 40.091 ;
     RECT  7.38 40.091 18.897 40.361 ;
     RECT  42.984 38.821 43.182 40.459 ;
     RECT  42.912 40.459 43.182 40.589 ;
     RECT  2.415 27.917 2.697 40.787 ;
     RECT  7.632 40.361 18.897 40.787 ;
     RECT  7.632 40.787 18.705 40.865 ;
     RECT  24.015 39.785 42.138 40.865 ;
     RECT  24.015 40.865 31.518 40.877 ;
     RECT  32.292 40.865 42.138 40.877 ;
     RECT  18 40.865 18.705 40.925 ;
     RECT  32.292 40.877 40.305 40.925 ;
     RECT  41.328 40.877 42.138 40.936 ;
     RECT  32.292 40.925 36.738 40.937 ;
     RECT  34.632 40.937 36.738 40.973 ;
     RECT  37.584 40.925 40.305 40.973 ;
     RECT  41.328 40.936 42.174 40.973 ;
     RECT  36.612 40.973 36.738 40.979 ;
     RECT  24.015 40.877 24.822 41.009 ;
     RECT  32.292 40.937 33.786 41.009 ;
     RECT  34.632 40.973 34.905 41.009 ;
     RECT  7.632 40.865 17.19 41.021 ;
     RECT  2.415 40.787 2.505 41.057 ;
     RECT  18.615 40.925 18.705 41.057 ;
     RECT  24.015 41.009 24.105 41.057 ;
     RECT  34.815 41.009 34.905 41.057 ;
     RECT  39.024 40.973 40.305 41.057 ;
     RECT  12.6 41.021 16.83 41.069 ;
     RECT  25.632 40.877 31.518 41.099 ;
     RECT  10.332 41.021 11.358 41.117 ;
     RECT  32.76 41.009 33.174 41.135 ;
     RECT  39.024 41.057 39.69 41.135 ;
     RECT  12.6 41.069 15.966 41.165 ;
     RECT  35.784 40.973 35.802 41.207 ;
     RECT  12.6 41.165 13.194 41.213 ;
     RECT  25.632 41.099 30.942 41.309 ;
     RECT  26.028 41.309 30.942 41.357 ;
     RECT  41.328 40.973 41.922 41.357 ;
     RECT  26.136 41.357 30.942 41.477 ;
     RECT  27.144 41.477 30.942 41.549 ;
     RECT  29.664 41.549 30.942 41.597 ;
     RECT  42.984 40.589 43.182 41.611 ;
     RECT  27.144 41.549 28.818 41.639 ;
     RECT  10.332 41.117 10.35 41.645 ;
     RECT  13.932 41.165 15.966 41.645 ;
     RECT  37.584 40.973 37.602 41.645 ;
     RECT  36.72 40.979 36.738 41.741 ;
     RECT  42.912 41.611 43.182 41.741 ;
     RECT  32.76 41.135 32.778 41.747 ;
     RECT  42.984 41.741 43.182 41.819 ;
     RECT  26.136 41.477 26.226 41.885 ;
     RECT  26.172 41.885 26.226 41.909 ;
     RECT  26.208 41.909 26.226 41.933 ;
     RECT  42.984 41.819 43.11 41.945 ;
     RECT  27.144 41.639 27.342 41.981 ;
     RECT  27.144 41.981 27.162 42.029 ;
     RECT  42.984 41.945 43.002 42.029 ;
     RECT  41.328 41.357 41.346 42.125 ;
     RECT  14.328 41.645 15.966 42.173 ;
     RECT  16.812 41.069 16.83 42.173 ;
     RECT  28.152 41.639 28.818 42.173 ;
     RECT  39.672 41.135 39.69 42.173 ;
     RECT  7.632 41.021 8.19 42.221 ;
     RECT  12.6 41.213 12.618 42.221 ;
     RECT  36.504 41.881 36.522 42.221 ;
     RECT  7.956 42.221 8.19 42.269 ;
     RECT  29.664 41.597 30.834 42.989 ;
     RECT  29.664 42.989 30.15 43.037 ;
     RECT  7.956 42.269 7.974 43.085 ;
     RECT  15.948 42.173 15.966 43.085 ;
     RECT  30.132 43.037 30.15 43.085 ;
     RECT  28.224 42.173 28.818 43.133 ;
     RECT  36.648 43.003 36.666 43.133 ;
     RECT  28.224 43.133 28.242 43.181 ;
     RECT  38.52 43.051 38.538 43.181 ;
    LAYER M4 ;
     RECT  0.084 1.008 0.179 1.032 ;
     RECT  0.06 1.032 0.179 1.104 ;
     RECT  0.084 1.104 0.179 1.128 ;
     RECT  0.06 1.128 0.179 1.2 ;
     RECT  0.084 1.2 0.179 1.224 ;
     RECT  0.06 1.224 0.179 1.296 ;
     RECT  0.084 1.296 0.179 1.32 ;
     RECT  0.06 1.32 0.179 1.392 ;
     RECT  0.084 1.392 0.179 1.416 ;
     RECT  0.06 1.416 0.179 1.488 ;
     RECT  0.084 1.488 0.179 1.512 ;
     RECT  0.06 1.512 0.179 1.584 ;
     RECT  0.084 1.584 0.179 1.608 ;
     RECT  0.06 1.608 0.179 1.68 ;
     RECT  0.084 1.68 0.179 1.704 ;
     RECT  0.06 1.704 0.179 1.776 ;
     RECT  0.084 1.776 0.179 1.8 ;
     RECT  0.06 1.8 0.179 1.872 ;
     RECT  0.084 1.872 0.179 1.896 ;
     RECT  0.06 1.896 0.179 1.968 ;
     RECT  0.084 1.968 0.179 1.992 ;
     RECT  0.06 1.992 0.179 2.064 ;
     RECT  0.084 2.064 0.179 2.088 ;
     RECT  0.06 2.088 0.179 2.16 ;
     RECT  0.084 2.16 0.179 2.184 ;
     RECT  0.06 2.184 0.179 2.256 ;
     RECT  0.084 2.256 0.179 2.28 ;
     RECT  0.06 2.28 0.179 2.352 ;
     RECT  0.084 2.352 0.179 2.376 ;
     RECT  0.06 2.376 0.179 2.448 ;
     RECT  0.084 2.448 0.179 2.472 ;
     RECT  0.06 2.472 0.179 2.544 ;
     RECT  0.084 2.544 0.179 2.568 ;
     RECT  0.06 2.568 0.179 2.64 ;
     RECT  0.084 2.64 0.179 2.664 ;
     RECT  0.06 2.664 0.179 2.736 ;
     RECT  0.084 2.736 0.179 2.76 ;
     RECT  0.06 2.76 0.179 2.832 ;
     RECT  0.084 2.832 0.179 2.856 ;
     RECT  0.06 2.856 0.179 2.928 ;
     RECT  0.084 2.928 0.179 2.952 ;
     RECT  0.06 2.952 0.179 3.024 ;
     RECT  0.084 3.024 0.179 3.048 ;
     RECT  0.06 3.048 0.179 3.12 ;
     RECT  0.084 3.12 0.179 3.144 ;
     RECT  0.06 3.144 0.179 3.216 ;
     RECT  0.084 3.216 0.179 3.24 ;
     RECT  0.06 3.24 0.179 3.312 ;
     RECT  0.084 3.312 0.179 3.336 ;
     RECT  0.06 3.336 0.179 3.408 ;
     RECT  0.084 3.408 0.179 3.432 ;
     RECT  0.06 3.432 0.179 3.504 ;
     RECT  0.084 3.504 0.179 3.528 ;
     RECT  0.06 3.528 0.179 3.6 ;
     RECT  0.084 3.6 0.179 3.624 ;
     RECT  0.06 3.624 0.179 3.696 ;
     RECT  0.084 3.696 0.179 3.72 ;
     RECT  0.06 3.72 0.179 3.792 ;
     RECT  0.084 3.792 0.179 3.816 ;
     RECT  0.06 3.816 0.179 3.888 ;
     RECT  0.084 3.888 0.179 3.912 ;
     RECT  0.06 3.912 0.179 3.984 ;
     RECT  0.084 3.984 0.179 4.008 ;
     RECT  0.06 4.008 0.179 4.848 ;
     RECT  0.084 4.848 0.179 4.872 ;
     RECT  0.06 4.872 0.179 4.944 ;
     RECT  0.084 4.944 0.179 4.968 ;
     RECT  0.06 4.968 0.179 5.04 ;
     RECT  0.084 5.04 0.179 5.064 ;
     RECT  0.06 5.064 0.179 5.136 ;
     RECT  0.084 5.136 0.179 5.16 ;
     RECT  0.06 5.16 0.179 5.232 ;
     RECT  0.084 5.232 0.179 5.256 ;
     RECT  0.06 5.256 0.179 5.328 ;
     RECT  0.084 5.328 0.179 5.352 ;
     RECT  0.06 5.352 0.179 5.424 ;
     RECT  0.084 5.424 0.179 5.448 ;
     RECT  0.06 5.448 0.179 5.52 ;
     RECT  0.084 5.52 0.179 5.544 ;
     RECT  0.06 5.544 0.179 5.616 ;
     RECT  0.084 5.616 0.179 5.64 ;
     RECT  0.06 5.64 0.179 5.712 ;
     RECT  0.084 5.712 0.179 5.736 ;
     RECT  0.06 5.736 0.179 5.808 ;
     RECT  0.084 5.808 0.179 5.832 ;
     RECT  0.06 5.832 0.179 5.904 ;
     RECT  0.084 5.904 0.179 5.928 ;
     RECT  0.06 5.928 0.179 6 ;
     RECT  0.084 6 0.179 6.024 ;
     RECT  0.06 6.024 0.179 6.096 ;
     RECT  0.084 6.096 0.179 6.12 ;
     RECT  0.06 6.12 0.179 6.192 ;
     RECT  0.084 6.192 0.179 6.216 ;
     RECT  0.06 6.216 0.179 6.288 ;
     RECT  0.084 6.288 0.179 6.312 ;
     RECT  0.06 6.312 0.179 6.384 ;
     RECT  0.084 6.384 0.179 6.408 ;
     RECT  0.06 6.408 0.179 6.48 ;
     RECT  0.084 6.48 0.179 6.504 ;
     RECT  0.06 6.504 0.179 6.576 ;
     RECT  0.084 6.576 0.179 6.6 ;
     RECT  0.06 6.6 0.179 6.672 ;
     RECT  0.084 6.672 0.179 6.696 ;
     RECT  0.06 6.696 0.179 6.768 ;
     RECT  0.084 6.768 0.179 6.792 ;
     RECT  0.06 6.792 0.179 6.864 ;
     RECT  0.084 6.864 0.179 6.888 ;
     RECT  0.06 6.888 0.179 6.96 ;
     RECT  0.084 6.96 0.179 6.984 ;
     RECT  0.06 6.984 0.179 7.056 ;
     RECT  0.084 7.056 0.179 7.08 ;
     RECT  0.06 7.08 0.179 7.152 ;
     RECT  0.084 7.152 0.179 7.176 ;
     RECT  0.06 7.176 0.179 7.248 ;
     RECT  0.084 7.248 0.179 7.272 ;
     RECT  0.06 7.272 0.179 7.344 ;
     RECT  0.084 7.344 0.179 7.368 ;
     RECT  0.06 7.368 0.179 7.44 ;
     RECT  0.084 7.44 0.179 7.464 ;
     RECT  0.06 7.464 0.179 7.536 ;
     RECT  0.084 7.536 0.179 7.56 ;
     RECT  0.06 7.56 0.179 7.632 ;
     RECT  0.084 7.632 0.179 7.656 ;
     RECT  0.06 7.656 0.179 7.728 ;
     RECT  0.084 7.728 0.179 7.752 ;
     RECT  0.06 7.752 0.179 7.824 ;
     RECT  0.084 7.824 0.179 7.848 ;
     RECT  0.06 7.848 0.179 7.92 ;
     RECT  0.084 7.92 0.179 7.944 ;
     RECT  0.06 7.944 0.179 8.016 ;
     RECT  0.084 8.016 0.179 8.04 ;
     RECT  0.06 8.04 0.179 8.112 ;
     RECT  0.084 8.112 0.179 8.136 ;
     RECT  0.06 8.136 0.179 8.208 ;
     RECT  0.084 8.208 0.179 8.232 ;
     RECT  0.06 8.232 0.179 8.304 ;
     RECT  0.084 8.304 0.179 8.328 ;
     RECT  0.06 8.328 0.179 8.4 ;
     RECT  0.084 8.4 0.179 8.424 ;
     RECT  0.06 8.424 0.179 8.496 ;
     RECT  0.084 8.496 0.179 8.52 ;
     RECT  0.06 8.52 0.179 8.592 ;
     RECT  0.084 8.592 0.179 8.616 ;
     RECT  0.06 8.616 0.179 8.688 ;
     RECT  0.084 8.688 0.179 8.712 ;
     RECT  0.06 8.712 0.179 8.784 ;
     RECT  0.084 8.784 0.179 8.808 ;
     RECT  0.06 8.808 0.179 8.88 ;
     RECT  0.084 8.88 0.179 8.904 ;
     RECT  0.06 8.904 0.179 8.976 ;
     RECT  0.084 8.976 0.179 9 ;
     RECT  0.06 9 0.179 9.072 ;
     RECT  0.084 9.072 0.179 9.096 ;
     RECT  0.06 9.096 0.179 9.168 ;
     RECT  0.084 9.168 0.179 9.192 ;
     RECT  0.06 9.192 0.179 9.264 ;
     RECT  0.084 9.264 0.179 9.288 ;
     RECT  0.06 9.288 0.179 9.36 ;
     RECT  0.084 9.36 0.179 9.384 ;
     RECT  0.06 9.384 0.179 9.456 ;
     RECT  0.084 9.456 0.179 9.48 ;
     RECT  0.06 9.48 0.179 9.552 ;
     RECT  0.084 9.552 0.179 9.576 ;
     RECT  0.06 9.576 0.179 9.648 ;
     RECT  0.084 9.648 0.179 9.672 ;
     RECT  0.06 9.672 0.179 9.744 ;
     RECT  0.084 9.744 0.179 9.768 ;
     RECT  0.06 9.768 0.179 9.84 ;
     RECT  0.084 9.84 0.179 9.864 ;
     RECT  0.06 9.864 0.179 9.936 ;
     RECT  0.084 9.936 0.179 9.96 ;
     RECT  0.06 9.96 0.179 10.032 ;
     RECT  0.084 10.032 0.179 10.056 ;
     RECT  0.06 10.056 0.179 10.128 ;
     RECT  0.084 10.128 0.179 10.152 ;
     RECT  0.06 10.152 0.179 10.224 ;
     RECT  0.084 10.224 0.179 10.248 ;
     RECT  0.06 10.248 0.179 10.32 ;
     RECT  0.084 10.32 0.179 10.344 ;
     RECT  0.06 10.344 0.179 10.416 ;
     RECT  0.084 10.416 0.179 10.44 ;
     RECT  0.06 10.44 0.179 10.512 ;
     RECT  0.084 10.512 0.179 10.536 ;
     RECT  0.06 10.536 0.179 10.608 ;
     RECT  0.084 10.608 0.179 10.632 ;
     RECT  0.06 10.632 0.179 10.704 ;
     RECT  0.084 10.704 0.179 10.728 ;
     RECT  0.06 10.728 0.179 10.8 ;
     RECT  0.084 10.8 0.179 10.824 ;
     RECT  0.06 10.824 0.179 10.896 ;
     RECT  0.084 10.896 0.179 10.92 ;
     RECT  0.06 10.92 0.179 10.992 ;
     RECT  0.084 10.992 0.179 11.016 ;
     RECT  0.06 11.016 0.179 11.088 ;
     RECT  0.084 11.088 0.179 11.112 ;
     RECT  0.06 11.112 0.179 11.184 ;
     RECT  0.084 11.184 0.179 11.208 ;
     RECT  0.06 11.208 0.179 11.28 ;
     RECT  0.084 11.28 0.179 11.304 ;
     RECT  0.06 11.304 0.179 11.376 ;
     RECT  0.084 11.376 0.179 11.4 ;
     RECT  0.06 11.4 0.179 11.472 ;
     RECT  0.084 11.472 0.179 11.496 ;
     RECT  0.06 11.496 0.179 11.568 ;
     RECT  0.084 11.568 0.179 11.592 ;
     RECT  0.06 11.592 0.179 11.664 ;
     RECT  0.084 11.664 0.179 11.688 ;
     RECT  0.06 11.688 0.179 11.76 ;
     RECT  0.084 11.76 0.179 11.784 ;
     RECT  0.06 11.784 0.179 11.856 ;
     RECT  0.084 11.856 0.179 11.88 ;
     RECT  0.06 11.88 0.179 11.952 ;
     RECT  0.084 11.952 0.179 11.976 ;
     RECT  0.06 11.976 0.179 12.048 ;
     RECT  0.084 12.048 0.179 12.072 ;
     RECT  0.06 12.072 0.179 12.144 ;
     RECT  0.084 12.144 0.179 12.168 ;
     RECT  0.06 12.168 0.179 12.24 ;
     RECT  0.084 12.24 0.179 12.264 ;
     RECT  0.06 12.264 0.179 12.336 ;
     RECT  0.084 12.336 0.179 12.36 ;
     RECT  0.06 12.36 0.179 12.432 ;
     RECT  0.084 12.432 0.179 12.456 ;
     RECT  0.06 12.456 0.179 12.528 ;
     RECT  0.084 12.528 0.179 12.552 ;
     RECT  0.06 12.552 0.179 12.624 ;
     RECT  0.084 12.624 0.179 12.648 ;
     RECT  0.06 12.648 0.179 12.72 ;
     RECT  0.084 12.72 0.179 12.744 ;
     RECT  0.06 12.744 0.179 12.816 ;
     RECT  0.084 12.816 0.179 12.84 ;
     RECT  0.06 12.84 0.179 12.912 ;
     RECT  0.084 12.912 0.179 12.936 ;
     RECT  0.06 12.936 0.179 13.008 ;
     RECT  0.084 13.008 0.179 13.032 ;
     RECT  0.06 13.032 0.179 13.104 ;
     RECT  0.084 13.104 0.179 13.128 ;
     RECT  0.06 13.128 0.179 13.2 ;
     RECT  0.084 13.2 0.179 13.224 ;
     RECT  0.06 13.224 0.179 13.296 ;
     RECT  0.084 13.296 0.179 13.32 ;
     RECT  0.06 13.32 0.179 13.392 ;
     RECT  0.084 13.392 0.179 13.416 ;
     RECT  0.06 13.416 0.179 13.488 ;
     RECT  0.084 13.488 0.179 13.512 ;
     RECT  0.06 13.512 0.179 13.584 ;
     RECT  0.084 13.584 0.179 13.608 ;
     RECT  0.06 13.608 0.179 13.68 ;
     RECT  0.084 13.68 0.179 13.704 ;
     RECT  0.06 13.704 0.179 13.776 ;
     RECT  0.084 13.776 0.179 13.8 ;
     RECT  0.06 13.8 0.179 13.872 ;
     RECT  0.084 13.872 0.179 13.896 ;
     RECT  0.06 13.896 0.179 13.968 ;
     RECT  0.084 13.968 0.179 13.992 ;
     RECT  0.06 13.992 0.179 14.064 ;
     RECT  0.084 14.064 0.179 14.088 ;
     RECT  0.06 14.088 0.179 14.16 ;
     RECT  0.084 14.16 0.179 14.184 ;
     RECT  0.06 14.184 0.179 14.256 ;
     RECT  0.084 14.256 0.179 14.28 ;
     RECT  0.06 14.28 0.179 14.352 ;
     RECT  0.084 14.352 0.179 14.376 ;
     RECT  0.06 14.376 0.179 14.448 ;
     RECT  0.084 14.448 0.179 14.472 ;
     RECT  0.06 14.472 0.179 14.544 ;
     RECT  0.084 14.544 0.179 14.568 ;
     RECT  0.06 14.568 0.179 14.64 ;
     RECT  0.084 14.64 0.179 14.664 ;
     RECT  0.06 14.664 0.179 14.736 ;
     RECT  0.084 14.736 0.179 14.76 ;
     RECT  0.06 14.76 0.179 14.832 ;
     RECT  0.084 14.832 0.179 14.856 ;
     RECT  0.06 14.856 0.179 14.928 ;
     RECT  0.084 14.928 0.179 14.952 ;
     RECT  0.06 14.952 0.179 15.024 ;
     RECT  0.084 15.024 0.179 15.048 ;
     RECT  0.06 15.048 0.179 15.12 ;
     RECT  0.084 15.12 0.179 15.144 ;
     RECT  0.06 15.144 0.179 15.216 ;
     RECT  0.084 15.216 0.179 15.24 ;
     RECT  0.06 15.24 0.179 15.312 ;
     RECT  0.084 15.312 0.179 15.336 ;
     RECT  0.06 15.336 0.179 15.408 ;
     RECT  0.084 15.408 0.179 15.432 ;
     RECT  0.06 15.432 0.179 15.504 ;
     RECT  0.084 15.504 0.179 15.528 ;
     RECT  0.06 15.528 0.179 15.6 ;
     RECT  0.084 15.6 0.179 15.624 ;
     RECT  0.06 15.624 0.179 15.696 ;
     RECT  0.084 15.696 0.179 15.72 ;
     RECT  0.06 15.72 0.179 15.792 ;
     RECT  0.084 15.792 0.179 15.816 ;
     RECT  0.06 15.816 0.179 15.888 ;
     RECT  0.084 15.888 0.179 15.912 ;
     RECT  0.06 15.912 0.179 15.984 ;
     RECT  0.084 15.984 0.179 16.008 ;
     RECT  0.06 16.008 0.179 16.08 ;
     RECT  0.084 16.08 0.179 16.104 ;
     RECT  0.06 16.104 0.179 16.176 ;
     RECT  0.084 16.176 0.179 16.2 ;
     RECT  0.06 16.2 0.179 16.272 ;
     RECT  0.084 16.272 0.179 16.296 ;
     RECT  0.06 16.296 0.179 16.368 ;
     RECT  0.084 16.368 0.179 16.392 ;
     RECT  0.06 16.392 0.179 16.464 ;
     RECT  0.084 16.464 0.179 16.488 ;
     RECT  0.06 16.488 0.179 16.56 ;
     RECT  0.084 16.56 0.179 16.584 ;
     RECT  0.06 16.584 0.179 16.656 ;
     RECT  0.084 16.656 0.179 16.68 ;
     RECT  0.06 16.68 0.179 16.752 ;
     RECT  0.084 16.752 0.179 16.776 ;
     RECT  0.06 16.776 0.179 16.848 ;
     RECT  0.084 16.848 0.179 16.872 ;
     RECT  0.06 16.872 0.179 16.944 ;
     RECT  0.084 16.944 0.179 16.968 ;
     RECT  0.06 16.968 0.179 17.04 ;
     RECT  0.084 17.04 0.179 17.064 ;
     RECT  0.06 17.064 0.179 17.136 ;
     RECT  0.084 17.136 0.179 17.16 ;
     RECT  0.06 17.16 0.179 17.232 ;
     RECT  0.084 17.232 0.179 17.256 ;
     RECT  0.06 17.256 0.179 17.328 ;
     RECT  0.084 17.328 0.179 17.352 ;
     RECT  0.06 17.352 0.179 17.424 ;
     RECT  0.084 17.424 0.179 17.448 ;
     RECT  0.06 17.448 0.179 17.52 ;
     RECT  0.084 17.52 0.179 17.544 ;
     RECT  0.06 17.544 0.179 17.616 ;
     RECT  0.084 17.616 0.179 17.64 ;
     RECT  0.06 17.64 0.179 17.712 ;
     RECT  0.084 17.712 0.179 17.736 ;
     RECT  0.06 17.736 0.179 17.808 ;
     RECT  0.084 17.808 0.179 17.832 ;
     RECT  0.06 17.832 0.179 17.904 ;
     RECT  0.084 17.904 0.179 17.928 ;
     RECT  0.06 17.928 0.179 18 ;
     RECT  0.084 18 0.179 18.024 ;
     RECT  0.06 18.024 0.179 18.096 ;
     RECT  0.084 18.096 0.179 18.12 ;
     RECT  0.06 18.12 0.179 18.192 ;
     RECT  0.084 18.192 0.179 18.216 ;
     RECT  0.06 18.216 0.179 18.288 ;
     RECT  0.084 18.288 0.179 18.312 ;
     RECT  0.06 18.312 0.179 18.384 ;
     RECT  0.084 18.384 0.179 18.408 ;
     RECT  0.06 18.408 0.179 18.48 ;
     RECT  0.084 18.48 0.179 18.504 ;
     RECT  0.06 18.504 0.179 18.576 ;
     RECT  0.084 18.576 0.179 18.6 ;
     RECT  0.06 18.6 0.179 18.672 ;
     RECT  0.084 18.672 0.179 18.696 ;
     RECT  0.06 18.696 0.179 18.768 ;
     RECT  0.084 18.768 0.179 18.792 ;
     RECT  0.06 18.792 0.179 18.864 ;
     RECT  0.084 18.864 0.179 18.888 ;
     RECT  0.06 18.888 0.179 18.96 ;
     RECT  0.084 18.96 0.179 18.984 ;
     RECT  0.06 18.984 0.179 19.056 ;
     RECT  0.084 19.056 0.179 19.08 ;
     RECT  0.06 19.08 0.179 19.152 ;
     RECT  0.084 19.152 0.179 19.176 ;
     RECT  0.06 19.176 0.179 19.248 ;
     RECT  0.084 19.248 0.179 19.272 ;
     RECT  0.06 19.272 0.179 19.344 ;
     RECT  0.084 19.344 0.179 19.368 ;
     RECT  0.06 19.368 0.179 19.44 ;
     RECT  0.084 19.44 0.179 19.464 ;
     RECT  0.06 19.464 0.179 19.536 ;
     RECT  0.084 19.536 0.179 19.56 ;
     RECT  0.06 19.56 0.179 19.632 ;
     RECT  0.084 19.632 0.179 19.656 ;
     RECT  0.06 19.656 0.179 19.728 ;
     RECT  0.084 19.728 0.179 19.752 ;
     RECT  0.06 19.752 0.179 19.824 ;
     RECT  0.084 19.824 0.179 19.848 ;
     RECT  0.06 19.848 0.179 19.92 ;
     RECT  0.084 19.92 0.179 19.944 ;
     RECT  0.06 19.944 0.179 20.016 ;
     RECT  0.084 20.016 0.179 20.04 ;
     RECT  0.06 20.04 0.179 20.112 ;
     RECT  0.084 20.112 0.179 20.136 ;
     RECT  0.06 20.136 0.179 20.208 ;
     RECT  0.084 20.208 0.179 20.232 ;
     RECT  0.06 20.232 0.179 20.304 ;
     RECT  0.084 20.304 0.179 20.328 ;
     RECT  0.06 20.328 0.179 20.4 ;
     RECT  0.084 20.4 0.179 20.424 ;
     RECT  0.06 20.424 0.179 20.496 ;
     RECT  0.084 20.496 0.179 20.52 ;
     RECT  0.06 20.52 0.179 20.592 ;
     RECT  0.084 20.592 0.179 20.616 ;
     RECT  0.06 20.616 0.179 20.688 ;
     RECT  0.084 20.688 0.179 20.712 ;
     RECT  0.06 20.712 0.179 20.784 ;
     RECT  0.084 20.784 0.179 20.808 ;
     RECT  0.06 20.808 0.179 20.88 ;
     RECT  0.084 20.88 0.179 20.904 ;
     RECT  0.06 20.904 0.179 20.976 ;
     RECT  0.084 20.976 0.179 21 ;
     RECT  0.06 21 0.179 21.072 ;
     RECT  0.084 21.072 0.179 21.096 ;
     RECT  0.06 21.096 0.179 21.168 ;
     RECT  0.084 21.168 0.179 21.192 ;
     RECT  0.06 21.192 0.179 21.264 ;
     RECT  0.084 21.264 0.179 21.288 ;
     RECT  0.06 21.288 0.179 21.36 ;
     RECT  0.084 21.36 0.179 21.384 ;
     RECT  0.06 21.384 0.179 21.456 ;
     RECT  0.084 21.456 0.179 21.48 ;
     RECT  0.06 21.48 0.179 21.552 ;
     RECT  0.084 21.552 0.179 21.576 ;
     RECT  0.06 21.576 0.179 21.648 ;
     RECT  0.084 21.648 0.179 21.672 ;
     RECT  0.06 21.672 0.179 21.744 ;
     RECT  0.084 21.744 0.179 21.768 ;
     RECT  0.06 21.768 0.179 21.84 ;
     RECT  0.084 21.84 0.179 21.864 ;
     RECT  0.06 21.864 0.179 21.936 ;
     RECT  0.084 21.936 0.179 21.96 ;
     RECT  0.06 21.96 0.179 22.032 ;
     RECT  0.084 22.032 0.179 22.056 ;
     RECT  0.06 22.056 0.179 22.128 ;
     RECT  0.084 22.128 0.179 22.152 ;
     RECT  0.06 22.152 0.179 22.224 ;
     RECT  0.084 22.224 0.179 22.248 ;
     RECT  0.06 22.248 0.179 22.32 ;
     RECT  0.084 22.32 0.179 22.344 ;
     RECT  0.06 22.344 0.179 22.416 ;
     RECT  0.084 22.416 0.179 22.44 ;
     RECT  0.06 22.44 0.179 22.512 ;
     RECT  0.084 22.512 0.179 22.536 ;
     RECT  0.06 22.536 0.179 22.608 ;
     RECT  0.084 22.608 0.179 22.632 ;
     RECT  0.06 22.632 0.179 22.704 ;
     RECT  0.084 22.704 0.179 22.728 ;
     RECT  0.06 22.728 0.179 22.8 ;
     RECT  0.084 22.8 0.179 22.824 ;
     RECT  0.06 22.824 0.179 22.896 ;
     RECT  0.084 22.896 0.179 22.92 ;
     RECT  0.06 22.92 0.179 22.992 ;
     RECT  0.084 22.992 0.179 23.016 ;
     RECT  0.06 23.016 0.179 23.088 ;
     RECT  0.084 23.088 0.179 23.112 ;
     RECT  0.06 23.112 0.179 23.184 ;
     RECT  0.084 23.184 0.179 23.208 ;
     RECT  0.06 23.208 0.179 24.048 ;
     RECT  0.084 24.048 0.179 24.072 ;
     RECT  0.06 24.072 0.179 24.144 ;
     RECT  0.084 24.144 0.179 24.168 ;
     RECT  0.06 24.168 0.179 24.24 ;
     RECT  0.084 24.24 0.179 24.264 ;
     RECT  0.06 24.264 0.179 24.336 ;
     RECT  0.084 24.336 0.179 24.36 ;
     RECT  0.06 24.36 0.179 24.432 ;
     RECT  0.084 24.432 0.179 24.456 ;
     RECT  0.06 24.456 0.179 24.528 ;
     RECT  0.084 24.528 0.179 24.552 ;
     RECT  0.06 24.552 0.179 24.624 ;
     RECT  0.084 24.624 0.179 24.648 ;
     RECT  0.06 24.648 0.179 24.72 ;
     RECT  0.084 24.72 0.179 24.744 ;
     RECT  0.06 24.744 0.179 24.816 ;
     RECT  0.084 24.816 0.179 24.84 ;
     RECT  0.06 24.84 0.179 24.912 ;
     RECT  0.084 24.912 0.179 24.936 ;
     RECT  0.06 24.936 0.179 25.008 ;
     RECT  0.084 25.008 0.179 25.032 ;
     RECT  0.06 25.032 0.179 25.104 ;
     RECT  0.084 25.104 0.179 25.128 ;
     RECT  0.06 25.128 0.179 25.2 ;
     RECT  0.084 25.2 0.179 25.224 ;
     RECT  0.06 25.224 0.179 25.296 ;
     RECT  0.084 25.296 0.179 25.32 ;
     RECT  0.06 25.32 0.179 25.392 ;
     RECT  0.084 25.392 0.179 25.416 ;
     RECT  0.06 25.416 0.179 25.488 ;
     RECT  0.084 25.488 0.179 25.512 ;
     RECT  0.06 25.512 0.179 25.584 ;
     RECT  0.084 25.584 0.179 25.608 ;
     RECT  0.06 25.608 0.179 25.68 ;
     RECT  0.084 25.68 0.179 25.704 ;
     RECT  0.06 25.704 0.179 25.776 ;
     RECT  0.084 25.776 0.179 25.8 ;
     RECT  0.06 25.8 0.179 25.872 ;
     RECT  0.084 25.872 0.179 25.896 ;
     RECT  0.06 25.896 0.179 25.968 ;
     RECT  0.084 25.968 0.179 25.992 ;
     RECT  0.06 25.992 0.179 26.064 ;
     RECT  0.084 26.064 0.179 26.088 ;
     RECT  0.06 26.088 0.179 26.16 ;
     RECT  0.084 26.16 0.179 26.184 ;
     RECT  0.06 26.184 0.179 26.256 ;
     RECT  0.084 26.256 0.179 26.28 ;
     RECT  0.179 1.104 0.227 26.28 ;
     RECT  0.227 1.2 0.419 26.28 ;
     RECT  0.419 1.296 0.611 26.28 ;
     RECT  0.611 1.488 0.851 26.28 ;
     RECT  0.851 2.064 2.408 26.28 ;
     RECT  2.408 2.064 2.512 41.052 ;
     RECT  2.512 2.064 2.704 40.782 ;
     RECT  2.704 2.064 3.017 27.912 ;
     RECT  3.017 22.224 3.269 27.912 ;
     RECT  3.017 2.064 3.971 21.192 ;
     RECT  3.269 26.208 4.021 27.912 ;
     RECT  3.269 22.224 4.025 25.176 ;
     RECT  3.971 20.496 4.165 21.192 ;
     RECT  4.025 22.224 4.165 23.976 ;
     RECT  4.021 26.208 4.177 28.536 ;
     RECT  3.971 2.064 4.421 19.512 ;
     RECT  4.421 2.352 4.709 19.512 ;
     RECT  4.709 2.448 4.889 19.512 ;
     RECT  4.025 25.056 4.925 25.176 ;
     RECT  4.165 20.496 5.065 23.976 ;
     RECT  4.177 26.544 5.353 28.536 ;
     RECT  5.353 26.496 5.389 28.536 ;
     RECT  4.889 2.496 5.413 19.512 ;
     RECT  5.065 20.496 5.413 24.792 ;
     RECT  5.389 26.16 5.509 28.536 ;
     RECT  5.509 26.16 5.596 28.68 ;
     RECT  5.413 2.496 5.893 24.792 ;
     RECT  5.596 26.16 5.893 28.536 ;
     RECT  5.893 2.256 6.029 28.536 ;
     RECT  6.029 2.16 6.563 28.536 ;
     RECT  6.563 2.16 6.755 28.056 ;
     RECT  6.755 2.16 6.803 27.96 ;
     RECT  6.803 2.16 7.045 27.528 ;
     RECT  7.009 38.688 7.189 38.712 ;
     RECT  6.469 36.096 7.669 36.12 ;
     RECT  7.189 38.688 7.693 39.24 ;
     RECT  7.045 1.728 7.808 27.528 ;
     RECT  7.669 36.096 7.808 37.128 ;
     RECT  7.693 38.4 7.808 39.24 ;
     RECT  7.808 1.728 7.912 41.052 ;
     RECT  7.621 42.192 7.945 42.216 ;
     RECT  7.912 1.728 8.005 41.016 ;
     RECT  7.333 0.144 8.101 0.168 ;
     RECT  8.005 1.68 8.104 41.016 ;
     RECT  8.104 1.68 8.165 27.96 ;
     RECT  8.101 0.144 8.242 0.312 ;
     RECT  7.945 42.192 8.339 43.08 ;
     RECT  8.242 0.096 8.341 0.312 ;
     RECT  8.341 0.096 8.353 0.36 ;
     RECT  8.339 42.192 8.435 43.032 ;
     RECT  8.353 0.144 8.525 0.36 ;
     RECT  8.435 42.24 8.627 43.032 ;
     RECT  8.104 35.952 8.633 39.24 ;
     RECT  8.165 1.728 8.669 27.96 ;
     RECT  8.525 0.144 8.915 0.312 ;
     RECT  8.915 0.144 9.059 0.168 ;
     RECT  8.669 23.904 9.277 27.96 ;
     RECT  8.627 43.008 9.539 43.032 ;
     RECT  8.104 40.416 9.541 41.016 ;
     RECT  8.669 1.728 9.605 22.776 ;
     RECT  9.605 20.016 9.673 22.776 ;
     RECT  9.277 23.904 9.673 28.68 ;
     RECT  8.633 35.952 9.853 38.856 ;
     RECT  9.673 20.016 9.875 28.68 ;
     RECT  9.875 20.16 9.893 28.68 ;
     RECT  9.541 39.888 9.893 41.016 ;
     RECT  9.853 35.328 9.917 38.856 ;
     RECT  9.917 35.328 10.181 39.336 ;
     RECT  9.893 40.464 10.321 41.016 ;
     RECT  10.213 0.096 10.405 0.12 ;
     RECT  10.405 0.096 10.565 0.168 ;
     RECT  10.565 0.096 10.609 0.216 ;
     RECT  10.609 0.048 10.825 0.216 ;
     RECT  9.605 1.728 10.865 18.984 ;
     RECT  10.825 0.048 10.885 0.264 ;
     RECT  9.893 20.16 10.937 27.912 ;
     RECT  10.937 20.16 10.969 20.184 ;
     RECT  10.321 40.464 11.027 41.64 ;
     RECT  10.181 35.328 11.269 38.76 ;
     RECT  10.865 1.728 11.297 18.024 ;
     RECT  11.077 43.008 11.363 43.032 ;
     RECT  11.269 35.232 11.365 38.76 ;
     RECT  10.937 21.264 11.411 27.912 ;
     RECT  10.969 19.248 11.477 20.184 ;
     RECT  11.027 40.464 11.507 41.112 ;
     RECT  11.365 34.704 11.689 38.76 ;
     RECT  11.477 19.392 11.801 20.184 ;
     RECT  11.689 34.704 11.801 38.808 ;
     RECT  10.885 0.048 11.845 0.312 ;
     RECT  11.411 23.184 11.941 27.912 ;
     RECT  11.801 34.704 11.941 34.728 ;
     RECT  11.297 1.728 11.987 17.784 ;
     RECT  11.801 19.968 12.089 20.184 ;
     RECT  11.987 1.728 12.133 2.76 ;
     RECT  11.845 0.048 12.229 0.408 ;
     RECT  12.229 0.048 12.325 0.456 ;
     RECT  12.133 1.44 12.325 2.76 ;
     RECT  11.801 35.808 12.481 38.808 ;
     RECT  11.987 3.84 12.517 17.784 ;
     RECT  12.089 20.16 12.517 20.184 ;
     RECT  11.411 21.264 12.517 22.2 ;
     RECT  12.517 20.16 12.589 22.2 ;
     RECT  11.941 23.184 12.589 28.536 ;
     RECT  12.481 35.808 12.613 39.048 ;
     RECT  11.941 34.656 12.769 34.728 ;
     RECT  12.613 35.808 12.769 39.144 ;
     RECT  12.769 34.656 12.853 39.144 ;
     RECT  11.507 40.464 12.853 41.016 ;
     RECT  12.589 20.16 12.985 28.536 ;
     RECT  12.853 34.656 13.165 41.016 ;
     RECT  12.325 0.048 13.208 2.76 ;
     RECT  12.517 3.84 13.208 18.024 ;
     RECT  12.985 20.16 13.208 29.064 ;
     RECT  12.445 31.104 13.208 31.128 ;
     RECT  13.165 34.656 13.208 41.208 ;
     RECT  12.589 42.192 13.285 42.216 ;
     RECT  13.285 42.192 13.381 42.84 ;
     RECT  13.208 0.048 13.504 41.208 ;
     RECT  13.504 19.824 13.529 29.112 ;
     RECT  13.381 42.192 13.573 42.936 ;
     RECT  13.504 0.048 13.619 16.296 ;
     RECT  13.619 14.784 13.673 16.296 ;
     RECT  13.504 31.776 13.859 31.8 ;
     RECT  13.504 32.928 13.859 32.952 ;
     RECT  13.504 34.224 13.921 41.208 ;
     RECT  13.573 42.192 13.921 43.032 ;
     RECT  13.921 34.224 13.955 43.032 ;
     RECT  13.529 19.824 14.033 20.664 ;
     RECT  13.955 34.224 14.099 42.216 ;
     RECT  13.529 21.744 14.285 29.112 ;
     RECT  14.285 29.04 14.321 29.112 ;
     RECT  14.321 29.088 14.393 29.112 ;
     RECT  13.673 14.88 14.497 16.296 ;
     RECT  13.504 17.28 14.497 18.216 ;
     RECT  14.285 21.744 14.569 27.72 ;
     RECT  14.569 21.456 14.609 27.72 ;
     RECT  13.619 0.048 14.713 13.08 ;
     RECT  13.504 30.768 14.821 30.792 ;
     RECT  14.78 32.208 14.821 32.232 ;
     RECT  14.099 34.224 14.821 42.168 ;
     RECT  14.821 30.768 14.867 32.232 ;
     RECT  14.609 21.456 14.897 24.168 ;
     RECT  14.713 0.048 14.963 13.32 ;
     RECT  14.821 33.552 15.041 42.168 ;
     RECT  15.041 33.552 15.181 41.016 ;
     RECT  14.609 25.68 15.257 27.72 ;
     RECT  14.897 21.456 15.329 23.64 ;
     RECT  14.033 19.824 15.349 20.328 ;
     RECT  15.329 21.456 15.349 22.776 ;
     RECT  14.963 8.976 15.397 13.32 ;
     RECT  14.497 14.88 15.397 18.216 ;
     RECT  15.349 19.344 15.541 22.776 ;
     RECT  15.397 8.976 15.587 18.216 ;
     RECT  14.867 30.768 15.644 31.464 ;
     RECT  15.257 25.824 15.653 27.72 ;
     RECT  15.644 29.952 15.685 31.464 ;
     RECT  15.041 42.144 15.685 42.168 ;
     RECT  15.653 26.64 15.865 27.72 ;
     RECT  15.541 19.296 15.901 22.776 ;
     RECT  15.685 29.856 15.973 31.464 ;
     RECT  15.181 32.928 15.973 41.016 ;
     RECT  14.963 0.048 15.977 7.992 ;
     RECT  15.901 19.248 15.977 22.776 ;
     RECT  15.685 42.144 15.977 43.08 ;
     RECT  15.865 26.64 16.012 28.44 ;
     RECT  15.973 29.856 16.057 41.016 ;
     RECT  16.057 30.72 16.115 41.016 ;
     RECT  15.587 8.976 16.157 18.024 ;
     RECT  16.012 28.416 16.189 28.44 ;
     RECT  16.157 8.976 16.259 17.64 ;
     RECT  16.259 8.976 16.373 11.976 ;
     RECT  16.259 13.008 16.373 17.64 ;
     RECT  16.115 34.896 16.373 41.016 ;
     RECT  16.373 35.088 16.433 41.016 ;
     RECT  16.115 30.72 16.445 33.576 ;
     RECT  16.433 35.088 16.445 41.064 ;
     RECT  16.445 37.248 16.481 41.064 ;
     RECT  16.481 37.44 16.517 41.064 ;
     RECT  16.445 30.72 16.589 33.48 ;
     RECT  15.977 0.048 16.625 7.464 ;
     RECT  15.977 19.248 16.625 22.728 ;
     RECT  16.625 19.248 16.729 22.488 ;
     RECT  16.657 23.904 16.741 23.928 ;
     RECT  15.977 42.144 16.841 42.168 ;
     RECT  16.445 35.088 16.949 36.264 ;
     RECT  16.589 30.768 17.021 33.48 ;
     RECT  16.517 37.44 17.021 41.016 ;
     RECT  16.012 26.64 17.053 27.144 ;
     RECT  17.021 38.448 17.093 41.016 ;
     RECT  16.189 28.416 17.125 29.64 ;
     RECT  17.093 38.448 17.129 39.72 ;
     RECT  16.625 0.048 17.165 7.224 ;
     RECT  17.053 26.352 17.173 27.144 ;
     RECT  17.125 28.224 17.173 29.64 ;
     RECT  17.093 40.8 17.201 41.016 ;
     RECT  17.161 24.576 17.273 24.984 ;
     RECT  17.273 24.576 17.309 24.936 ;
     RECT  16.949 35.856 17.315 36.264 ;
     RECT  16.373 8.976 17.377 11.544 ;
     RECT  16.729 18.96 17.381 22.488 ;
     RECT  17.377 8.976 17.521 11.88 ;
     RECT  16.373 13.104 17.521 17.64 ;
     RECT  17.381 18.96 17.521 22.056 ;
     RECT  17.021 37.44 17.521 37.464 ;
     RECT  17.165 0.048 17.597 7.08 ;
     RECT  17.021 30.864 17.621 33.48 ;
     RECT  17.521 8.976 17.665 17.64 ;
     RECT  17.521 18.912 17.665 22.056 ;
     RECT  17.665 8.976 17.737 22.056 ;
     RECT  17.597 0.048 17.777 2.904 ;
     RECT  17.621 30.864 18.044 33.672 ;
     RECT  17.953 34.752 18.044 34.776 ;
     RECT  18.044 30.864 18.085 34.776 ;
     RECT  17.315 35.856 18.085 36.024 ;
     RECT  17.597 3.936 18.313 7.08 ;
     RECT  17.737 8.16 18.313 22.056 ;
     RECT  17.309 24.912 18.385 24.936 ;
     RECT  18.313 3.936 18.421 22.056 ;
     RECT  18.385 24.48 18.469 24.936 ;
     RECT  18.469 24.48 18.529 25.032 ;
     RECT  17.777 1.392 18.608 2.904 ;
     RECT  18.421 3.936 18.608 22.344 ;
     RECT  18.529 23.952 18.608 25.032 ;
     RECT  17.173 26.352 18.608 29.64 ;
     RECT  18.085 30.864 18.608 36.024 ;
     RECT  17.521 37.056 18.608 37.464 ;
     RECT  17.129 38.88 18.608 39.72 ;
     RECT  17.201 40.8 18.608 40.92 ;
     RECT  18.608 1.392 18.712 41.052 ;
     RECT  18.712 1.392 18.904 40.782 ;
     RECT  18.904 23.952 18.965 38.136 ;
     RECT  18.904 3.936 19.001 6.12 ;
     RECT  18.904 7.392 19.253 22.968 ;
     RECT  19.253 7.392 19.289 16.008 ;
     RECT  18.965 35.856 19.331 38.136 ;
     RECT  19.289 7.392 19.427 15.624 ;
     RECT  19.427 8.736 19.468 15.624 ;
     RECT  19.427 7.392 19.505 7.416 ;
     RECT  18.965 23.952 19.505 34.872 ;
     RECT  19.253 17.184 19.657 22.968 ;
     RECT  19.505 23.952 19.685 29.784 ;
     RECT  19.685 24.48 19.721 29.784 ;
     RECT  19.657 20.928 19.957 22.968 ;
     RECT  18.904 1.392 19.973 2.232 ;
     RECT  19.468 9.504 19.973 15.624 ;
     RECT  19.505 30.864 20.003 34.872 ;
     RECT  17.777 0.048 20.009 0.072 ;
     RECT  19.973 2.064 20.045 2.232 ;
     RECT  20.003 31.392 20.153 34.872 ;
     RECT  19.331 38.112 20.221 38.136 ;
     RECT  20.221 38.112 20.225 38.232 ;
     RECT  20.153 31.68 20.245 34.872 ;
     RECT  19.331 35.856 20.245 36.984 ;
     RECT  20.245 31.68 20.297 36.984 ;
     RECT  20.297 31.68 20.441 35.88 ;
     RECT  20.297 36.96 20.485 36.984 ;
     RECT  20.225 38.208 20.531 38.232 ;
     RECT  19.721 24.768 20.533 29.784 ;
     RECT  20.441 31.68 20.585 35.544 ;
     RECT  19.657 17.184 20.732 19.56 ;
     RECT  19.957 20.928 20.732 23.304 ;
     RECT  19.973 9.504 20.761 10.824 ;
     RECT  20.732 17.184 20.819 23.304 ;
     RECT  20.819 20.832 20.869 23.304 ;
     RECT  20.533 24.768 20.869 29.88 ;
     RECT  20.761 9.264 20.941 10.824 ;
     RECT  19.973 12.528 21.013 15.624 ;
     RECT  20.819 17.184 21.013 19.848 ;
     RECT  20.941 9.264 21.049 11.544 ;
     RECT  21.013 12.528 21.049 19.848 ;
     RECT  20.585 31.68 21.089 33.048 ;
     RECT  20.869 20.832 21.161 29.88 ;
     RECT  21.161 20.88 21.233 29.88 ;
     RECT  20.653 7.968 21.373 7.992 ;
     RECT  21.049 9.264 21.377 19.848 ;
     RECT  20.485 36.96 21.409 37.032 ;
     RECT  21.409 36.864 21.481 37.032 ;
     RECT  21.373 7.92 21.485 7.992 ;
     RECT  21.233 25.632 21.553 29.88 ;
     RECT  21.233 20.88 21.557 24.504 ;
     RECT  20.585 34.512 21.596 35.544 ;
     RECT  21.596 34.512 21.683 35.688 ;
     RECT  21.089 31.68 21.953 32.808 ;
     RECT  21.553 25.632 21.985 29.928 ;
     RECT  21.985 25.632 22.025 30.264 ;
     RECT  21.481 36.864 22.097 37.368 ;
     RECT  22.025 27.072 22.133 30.264 ;
     RECT  22.025 25.632 22.163 26.04 ;
     RECT  21.377 9.264 22.165 11.88 ;
     RECT  21.557 23.376 22.201 24.504 ;
     RECT  22.097 36.864 22.205 37.224 ;
     RECT  22.201 23.376 22.259 25.608 ;
     RECT  21.953 31.68 22.313 32.328 ;
     RECT  22.205 36.864 22.349 36.888 ;
     RECT  22.165 9.072 22.364 11.88 ;
     RECT  21.377 13.104 22.364 19.848 ;
     RECT  22.259 24.528 22.385 25.608 ;
     RECT  22.313 31.68 22.385 32.232 ;
     RECT  21.683 34.512 22.417 35.592 ;
     RECT  22.364 9.072 22.451 19.848 ;
     RECT  22.417 33.888 22.457 35.592 ;
     RECT  21.485 7.92 22.597 7.944 ;
     RECT  22.451 9.072 22.597 11.16 ;
     RECT  21.557 20.88 22.633 22.248 ;
     RECT  22.259 23.376 22.633 23.4 ;
     RECT  20.045 2.208 22.691 2.232 ;
     RECT  22.597 7.92 22.7 11.16 ;
     RECT  19.001 3.936 22.739 4.92 ;
     RECT  22.385 31.68 22.741 31.8 ;
     RECT  22.7 7.392 22.787 11.16 ;
     RECT  22.451 13.056 22.853 19.848 ;
     RECT  22.739 4.896 22.883 4.92 ;
     RECT  22.457 35.424 22.997 35.592 ;
     RECT  22.853 18.24 23.221 19.848 ;
     RECT  22.633 20.88 23.221 23.4 ;
     RECT  23.221 18.24 23.389 23.4 ;
     RECT  22.133 27.312 23.557 30.264 ;
     RECT  23.389 18.24 23.605 23.88 ;
     RECT  22.385 24.864 23.605 25.608 ;
     RECT  23.557 26.832 23.641 30.36 ;
     RECT  23.641 26.592 23.749 30.36 ;
     RECT  22.741 31.344 23.749 31.8 ;
     RECT  22.853 13.056 23.857 17.064 ;
     RECT  19.001 6.096 24.008 6.12 ;
     RECT  22.787 7.92 24.008 11.16 ;
     RECT  23.857 12.576 24.008 17.064 ;
     RECT  23.605 18.24 24.008 25.608 ;
     RECT  23.749 26.592 24.008 31.8 ;
     RECT  22.457 33.888 24.008 33.912 ;
     RECT  22.997 35.424 24.008 35.448 ;
     RECT  24.008 2.148 24.112 41.052 ;
     RECT  24.112 2.418 24.304 40.782 ;
     RECT  24.304 12.48 24.419 19.848 ;
     RECT  24.304 29.184 24.515 31.896 ;
     RECT  24.515 29.184 24.581 30.36 ;
     RECT  24.419 12.48 24.653 17.064 ;
     RECT  24.653 17.04 24.659 17.064 ;
     RECT  24.304 26.592 24.659 26.616 ;
     RECT  24.653 12.48 24.797 15.624 ;
     RECT  24.581 29.328 24.869 30.36 ;
     RECT  24.304 6.096 25.021 6.84 ;
     RECT  24.419 18.144 25.121 19.848 ;
     RECT  24.304 20.832 25.129 25.128 ;
     RECT  24.515 31.392 25.229 31.896 ;
     RECT  24.304 8.16 25.265 11.16 ;
     RECT  25.265 9.504 25.369 11.16 ;
     RECT  24.797 13.056 25.481 15.624 ;
     RECT  24.304 38.256 25.513 39.672 ;
     RECT  25.333 40.848 25.513 40.872 ;
     RECT  25.513 37.344 25.621 40.872 ;
     RECT  24.304 33.888 25.693 33.912 ;
     RECT  25.693 33.072 25.777 33.912 ;
     RECT  25.481 14.352 25.805 15.624 ;
     RECT  25.369 9.504 25.811 11.976 ;
     RECT  24.869 29.52 25.813 30.36 ;
     RECT  25.229 31.392 25.813 31.8 ;
     RECT  25.813 29.52 25.841 31.8 ;
     RECT  25.841 29.52 25.859 31.608 ;
     RECT  25.129 22.512 25.909 25.128 ;
     RECT  25.859 29.52 25.945 31.368 ;
     RECT  25.909 22.512 25.955 25.272 ;
     RECT  25.945 28.992 25.957 31.368 ;
     RECT  25.621 37.344 26.017 41.304 ;
     RECT  25.121 18.768 26.089 19.56 ;
     RECT  25.129 20.832 26.089 20.856 ;
     RECT  25.955 23.52 26.093 25.272 ;
     RECT  26.093 23.568 26.125 25.272 ;
     RECT  26.017 37.344 26.125 41.352 ;
     RECT  26.125 37.344 26.197 41.88 ;
     RECT  25.957 28.992 26.345 30.792 ;
     RECT  25.811 10.848 26.377 11.976 ;
     RECT  25.481 13.056 26.377 13.32 ;
     RECT  26.345 28.992 26.453 30.36 ;
     RECT  26.485 17.184 26.521 17.208 ;
     RECT  26.377 10.848 26.633 13.32 ;
     RECT  25.805 14.496 26.665 15.624 ;
     RECT  26.521 17.088 26.665 17.208 ;
     RECT  26.089 18.768 26.669 20.856 ;
     RECT  25.955 22.512 26.693 22.536 ;
     RECT  25.811 9.504 26.701 9.72 ;
     RECT  26.665 14.496 26.705 17.208 ;
     RECT  26.413 27.84 26.737 27.864 ;
     RECT  26.453 28.992 26.737 29.784 ;
     RECT  26.701 9.456 26.771 9.72 ;
     RECT  26.125 23.568 26.773 25.656 ;
     RECT  25.777 33.888 26.773 33.912 ;
     RECT  26.693 21.984 26.777 22.536 ;
     RECT  24.304 35.424 26.809 35.448 ;
     RECT  26.773 33.888 26.813 34.104 ;
     RECT  26.773 23.568 26.819 26.232 ;
     RECT  26.737 27.84 26.819 29.784 ;
     RECT  26.633 13.056 26.921 13.32 ;
     RECT  25.021 6.096 27.065 6.12 ;
     RECT  26.197 37.344 27.133 41.928 ;
     RECT  26.633 10.848 27.173 11.88 ;
     RECT  26.771 9.456 27.241 9.528 ;
     RECT  26.669 18.768 27.313 20.136 ;
     RECT  26.809 35.424 27.313 36.264 ;
     RECT  27.133 37.344 27.313 42.024 ;
     RECT  25.265 8.16 27.349 8.184 ;
     RECT  27.349 7.776 27.453 8.184 ;
     RECT  26.819 26.208 27.457 26.232 ;
     RECT  27.457 26.208 27.493 26.808 ;
     RECT  27.313 18.24 27.637 20.136 ;
     RECT  27.173 10.848 27.677 10.872 ;
     RECT  26.819 23.568 27.817 25.128 ;
     RECT  27.493 26.208 27.817 27.768 ;
     RECT  26.819 28.8 27.817 29.784 ;
     RECT  27.637 17.472 27.821 20.136 ;
     RECT  27.821 20.016 27.853 20.136 ;
     RECT  26.705 14.496 27.889 16.296 ;
     RECT  26.921 13.056 27.925 13.08 ;
     RECT  27.889 14.448 27.925 16.296 ;
     RECT  27.925 13.056 27.965 16.296 ;
     RECT  27.853 20.016 28.073 21 ;
     RECT  27.817 23.568 28.109 29.784 ;
     RECT  27.961 32.88 28.109 32.904 ;
     RECT  27.313 35.424 28.141 42.024 ;
     RECT  28.109 26.784 28.213 29.784 ;
     RECT  27.457 31.44 28.213 31.464 ;
     RECT  27.241 9.312 28.217 9.528 ;
     RECT  27.173 11.856 28.249 11.88 ;
     RECT  26.777 22.512 28.268 22.536 ;
     RECT  27.965 13.584 28.316 16.296 ;
     RECT  28.268 22.176 28.355 22.536 ;
     RECT  28.217 9.456 28.357 9.528 ;
     RECT  28.316 13.584 28.357 16.392 ;
     RECT  27.821 17.472 28.357 18.792 ;
     RECT  27.453 7.776 28.361 7.992 ;
     RECT  28.073 20.016 28.403 20.04 ;
     RECT  28.357 13.584 28.425 18.792 ;
     RECT  28.213 26.784 28.425 29.928 ;
     RECT  28.355 22.512 28.453 22.536 ;
     RECT  28.109 23.568 28.453 24.696 ;
     RECT  28.249 11.376 28.465 11.88 ;
     RECT  28.141 35.424 28.465 42.168 ;
     RECT  28.213 31.44 28.501 31.704 ;
     RECT  26.813 34.08 28.645 34.104 ;
     RECT  28.465 35.232 28.789 42.168 ;
     RECT  28.213 43.152 28.789 43.176 ;
     RECT  28.645 34.08 28.825 34.152 ;
     RECT  28.501 31.344 28.969 31.704 ;
     RECT  28.465 11.376 29.005 12.072 ;
     RECT  28.425 13.584 29.005 17.496 ;
     RECT  28.425 18.48 29.077 18.792 ;
     RECT  28.825 33.648 29.077 34.152 ;
     RECT  28.789 35.232 29.077 43.176 ;
     RECT  28.357 9.456 29.269 10.152 ;
     RECT  28.361 7.968 29.408 7.992 ;
     RECT  29.269 9.456 29.408 10.2 ;
     RECT  29.005 11.376 29.408 17.496 ;
     RECT  29.077 18.48 29.408 19.416 ;
     RECT  28.453 22.512 29.408 24.696 ;
     RECT  28.109 25.68 29.408 25.704 ;
     RECT  28.425 26.784 29.408 29.544 ;
     RECT  28.969 31.2 29.408 31.704 ;
     RECT  29.077 33.648 29.408 43.176 ;
     RECT  29.408 2.148 29.512 43.176 ;
     RECT  29.512 2.418 29.704 43.176 ;
     RECT  29.704 18.192 30.125 20.328 ;
     RECT  29.704 28.416 30.233 43.176 ;
     RECT  30.233 28.656 30.701 43.176 ;
     RECT  29.704 10.176 30.737 10.2 ;
     RECT  29.704 11.376 30.769 16.92 ;
     RECT  29.704 23.376 30.769 24.696 ;
     RECT  29.704 25.68 30.769 25.704 ;
     RECT  30.769 11.232 30.949 16.92 ;
     RECT  30.949 10.368 31.057 16.92 ;
     RECT  31.057 10.368 31.097 17.352 ;
     RECT  31.097 12.048 31.133 17.352 ;
     RECT  30.701 29.952 31.169 43.176 ;
     RECT  30.125 18.72 31.237 20.328 ;
     RECT  31.237 18.72 31.277 21.144 ;
     RECT  30.769 23.376 31.285 25.704 ;
     RECT  29.704 26.784 31.285 27.288 ;
     RECT  30.701 28.656 31.309 28.968 ;
     RECT  31.285 23.376 31.331 27.288 ;
     RECT  31.133 12.768 31.385 17.352 ;
     RECT  31.331 26.208 31.637 27.288 ;
     RECT  31.331 23.376 31.673 24.888 ;
     RECT  31.637 26.208 31.673 26.232 ;
     RECT  31.637 27.264 31.673 27.288 ;
     RECT  31.385 12.768 31.709 16.824 ;
     RECT  31.709 14.784 31.745 16.824 ;
     RECT  31.765 22.32 31.777 22.344 ;
     RECT  31.097 10.368 31.817 10.872 ;
     RECT  31.309 28.512 31.849 28.968 ;
     RECT  31.777 22.176 31.852 22.344 ;
     RECT  31.849 28.512 31.889 29.112 ;
     RECT  31.817 10.848 31.925 10.872 ;
     RECT  31.745 14.784 31.925 16.296 ;
     RECT  31.277 19.488 31.925 21.144 ;
     RECT  31.925 19.488 32.033 20.952 ;
     RECT  31.709 12.768 32.077 13.704 ;
     RECT  31.852 22.176 32.105 22.2 ;
     RECT  32.077 12.768 32.177 12.792 ;
     RECT  32.033 19.488 32.245 19.608 ;
     RECT  31.169 30.864 32.249 43.176 ;
     RECT  31.925 15.456 32.285 16.296 ;
     RECT  31.889 28.8 32.497 29.112 ;
     RECT  32.281 30.096 32.497 30.12 ;
     RECT  32.245 19.152 32.537 19.608 ;
     RECT  32.677 26.736 32.771 26.76 ;
     RECT  31.673 23.808 32.789 24.888 ;
     RECT  32.857 18.768 33.149 18.792 ;
     RECT  32.033 20.928 33.293 20.952 ;
     RECT  32.497 28.8 33.397 30.12 ;
     RECT  32.249 31.152 33.397 43.176 ;
     RECT  32.789 23.904 33.581 24.216 ;
     RECT  33.581 23.904 33.617 24.12 ;
     RECT  33.397 28.8 34.165 43.176 ;
     RECT  32.285 16.272 34.808 16.296 ;
     RECT  34.153 22.464 34.808 22.488 ;
     RECT  33.617 23.904 34.808 23.928 ;
     RECT  34.645 27.072 34.808 27.096 ;
     RECT  34.165 28.656 34.808 43.176 ;
     RECT  34.808 2.148 34.912 43.176 ;
     RECT  34.912 2.418 35.104 43.176 ;
     RECT  35.104 16.272 35.267 16.296 ;
     RECT  35.104 22.464 36.277 22.488 ;
     RECT  36.277 22.464 36.373 22.776 ;
     RECT  36.373 22.128 36.421 22.776 ;
     RECT  36.421 21.504 36.613 22.776 ;
     RECT  35.104 26.64 36.901 43.176 ;
     RECT  36.901 26.256 37.177 43.176 ;
     RECT  37.285 24.336 37.573 24.36 ;
     RECT  37.573 24.336 38.252 24.504 ;
     RECT  37.177 26.112 38.252 43.176 ;
     RECT  38.252 24.336 38.339 43.176 ;
     RECT  36.613 21.504 38.401 23.208 ;
     RECT  38.339 24.336 38.401 25.032 ;
     RECT  38.339 26.112 38.549 43.176 ;
     RECT  38.549 26.112 38.593 43.08 ;
     RECT  38.593 26.112 39.011 43.032 ;
     RECT  39.011 29.232 39.395 43.032 ;
     RECT  39.395 29.232 39.443 42.936 ;
     RECT  38.401 21.504 39.589 25.032 ;
     RECT  39.011 26.112 39.589 27.912 ;
     RECT  39.443 29.232 39.701 42.168 ;
     RECT  39.589 21.504 40.208 27.912 ;
     RECT  39.701 29.232 40.208 42.12 ;
     RECT  40.208 2.148 40.312 42.12 ;
     RECT  40.312 2.418 40.504 42.12 ;
     RECT  40.504 21.648 41.075 25.08 ;
     RECT  41.075 22.176 41.315 25.08 ;
     RECT  41.315 22.704 41.411 25.08 ;
     RECT  40.504 26.208 41.507 27.912 ;
     RECT  41.507 27.888 41.555 27.912 ;
     RECT  40.504 29.424 41.605 42.12 ;
     RECT  41.411 22.704 41.891 23.352 ;
     RECT  41.507 26.208 41.939 26.808 ;
     RECT  41.891 22.752 41.987 23.352 ;
     RECT  41.939 26.208 42.035 26.232 ;
     RECT  41.987 23.328 42.083 23.352 ;
     RECT  41.411 25.056 42.131 25.08 ;
     RECT  41.605 29.136 43.116 29.16 ;
     RECT  41.605 29.16 43.164 29.232 ;
     RECT  41.605 29.232 43.116 29.256 ;
     RECT  41.605 29.256 43.164 29.328 ;
     RECT  41.605 29.328 43.116 29.352 ;
     RECT  41.605 29.352 43.164 29.424 ;
     RECT  41.605 29.424 43.116 29.448 ;
     RECT  41.605 29.448 43.164 29.52 ;
     RECT  41.605 29.52 43.116 29.544 ;
     RECT  41.605 29.544 43.164 29.616 ;
     RECT  41.605 29.616 43.116 29.64 ;
     RECT  41.605 29.64 43.164 29.712 ;
     RECT  41.605 29.712 43.116 29.736 ;
     RECT  41.605 29.736 43.164 29.808 ;
     RECT  41.605 29.808 43.116 29.832 ;
     RECT  41.605 29.832 43.164 29.904 ;
     RECT  41.605 29.904 43.116 29.928 ;
     RECT  41.605 29.928 43.164 30 ;
     RECT  41.605 30 43.116 30.024 ;
     RECT  41.605 30.024 43.164 30.096 ;
     RECT  41.605 30.096 43.116 30.12 ;
     RECT  41.605 30.12 43.164 30.192 ;
     RECT  41.605 30.192 43.116 30.216 ;
     RECT  41.605 30.216 43.164 30.288 ;
     RECT  41.605 30.288 43.116 30.312 ;
     RECT  41.605 30.312 43.164 30.384 ;
     RECT  41.605 30.384 43.116 30.408 ;
     RECT  41.605 30.408 43.164 30.48 ;
     RECT  41.605 30.48 43.116 30.504 ;
     RECT  41.605 30.504 43.164 30.576 ;
     RECT  41.605 30.576 43.116 30.6 ;
     RECT  41.605 30.6 43.164 30.672 ;
     RECT  41.605 30.672 43.116 30.696 ;
     RECT  41.605 30.696 43.164 30.768 ;
     RECT  41.605 30.768 43.116 30.792 ;
     RECT  41.605 30.792 43.164 30.864 ;
     RECT  41.605 30.864 43.116 30.888 ;
     RECT  41.605 30.888 43.164 30.96 ;
     RECT  41.605 30.96 43.116 30.984 ;
     RECT  41.605 30.984 43.164 31.056 ;
     RECT  41.605 31.056 43.116 31.08 ;
     RECT  41.605 31.08 43.164 31.152 ;
     RECT  41.605 31.152 43.116 31.176 ;
     RECT  41.605 31.176 43.164 31.248 ;
     RECT  41.605 31.248 43.116 31.272 ;
     RECT  41.605 31.272 43.164 31.344 ;
     RECT  41.605 31.344 43.116 31.368 ;
     RECT  41.605 31.368 43.164 31.44 ;
     RECT  41.605 31.44 43.116 31.464 ;
     RECT  41.605 31.464 43.164 31.536 ;
     RECT  41.605 31.536 43.116 31.56 ;
     RECT  41.605 31.56 43.164 31.632 ;
     RECT  41.605 31.632 43.116 31.656 ;
     RECT  41.605 31.656 43.164 31.728 ;
     RECT  41.605 31.728 43.116 31.752 ;
     RECT  41.605 31.752 43.164 31.824 ;
     RECT  41.605 31.824 43.116 31.848 ;
     RECT  41.605 31.848 43.164 31.92 ;
     RECT  41.605 31.92 43.116 31.944 ;
     RECT  41.605 31.944 43.164 32.016 ;
     RECT  41.605 32.016 43.116 32.04 ;
     RECT  41.605 32.04 43.164 32.112 ;
     RECT  41.605 32.112 43.116 32.136 ;
     RECT  41.605 32.136 43.164 32.208 ;
     RECT  41.605 32.208 43.116 32.232 ;
     RECT  41.605 32.232 43.164 32.304 ;
     RECT  41.605 32.304 43.116 32.328 ;
     RECT  41.605 32.328 43.164 32.4 ;
     RECT  41.605 32.4 43.116 32.424 ;
     RECT  41.605 32.424 43.164 32.496 ;
     RECT  41.605 32.496 43.116 32.52 ;
     RECT  41.605 32.52 43.164 32.592 ;
     RECT  41.605 32.592 43.116 32.616 ;
     RECT  41.605 32.616 43.164 32.688 ;
     RECT  41.605 32.688 43.116 32.712 ;
     RECT  41.605 32.712 43.164 32.784 ;
     RECT  41.605 32.784 43.116 32.808 ;
     RECT  41.605 32.808 43.164 32.88 ;
     RECT  41.605 32.88 43.116 32.904 ;
     RECT  41.605 32.904 43.164 32.976 ;
     RECT  41.605 32.976 43.116 33 ;
     RECT  41.605 33 43.164 33.072 ;
     RECT  41.605 33.072 43.116 33.096 ;
     RECT  41.605 33.096 43.164 33.168 ;
     RECT  41.605 33.168 43.116 33.192 ;
     RECT  41.605 33.192 43.164 33.264 ;
     RECT  41.605 33.264 43.116 33.288 ;
     RECT  41.605 33.288 43.164 33.36 ;
     RECT  41.605 33.36 43.116 33.384 ;
     RECT  41.605 33.384 43.164 33.456 ;
     RECT  41.605 33.456 43.116 33.48 ;
     RECT  41.605 33.48 43.164 33.552 ;
     RECT  41.605 33.552 43.116 33.576 ;
     RECT  41.605 33.576 43.164 33.648 ;
     RECT  41.605 33.648 43.116 33.672 ;
     RECT  41.605 33.672 43.164 33.744 ;
     RECT  41.605 33.744 43.116 33.768 ;
     RECT  41.605 33.768 43.164 33.84 ;
     RECT  41.605 33.84 43.116 33.864 ;
     RECT  41.605 33.864 43.164 33.936 ;
     RECT  41.605 33.936 43.116 33.96 ;
     RECT  41.605 33.96 43.164 34.032 ;
     RECT  41.605 34.032 43.116 34.056 ;
     RECT  41.605 34.056 43.164 34.128 ;
     RECT  41.605 34.128 43.116 34.152 ;
     RECT  41.605 34.152 43.164 34.224 ;
     RECT  41.605 34.224 43.116 34.248 ;
     RECT  41.605 34.248 43.164 34.32 ;
     RECT  41.605 34.32 43.116 34.344 ;
     RECT  41.605 34.344 43.164 34.416 ;
     RECT  41.605 34.416 43.116 34.44 ;
     RECT  41.605 34.44 43.164 34.512 ;
     RECT  41.605 34.512 43.116 34.536 ;
     RECT  41.605 34.536 43.164 34.608 ;
     RECT  41.605 34.608 43.116 34.632 ;
     RECT  41.605 34.632 43.164 34.704 ;
     RECT  41.605 34.704 43.116 34.728 ;
     RECT  41.605 34.728 43.164 34.8 ;
     RECT  41.605 34.8 43.116 34.824 ;
     RECT  41.605 34.824 43.164 34.896 ;
     RECT  41.605 34.896 43.116 34.92 ;
     RECT  41.605 34.92 43.164 34.992 ;
     RECT  41.605 34.992 43.116 35.016 ;
     RECT  41.605 35.016 43.164 35.088 ;
     RECT  41.605 35.088 43.116 35.112 ;
     RECT  41.605 35.112 43.164 35.184 ;
     RECT  41.605 35.184 43.116 35.208 ;
     RECT  41.605 35.208 43.164 35.28 ;
     RECT  41.605 35.28 43.116 35.304 ;
     RECT  41.605 35.304 43.164 35.376 ;
     RECT  41.605 35.376 43.116 35.4 ;
     RECT  41.605 35.4 43.164 35.472 ;
     RECT  41.605 35.472 43.116 35.496 ;
     RECT  41.605 35.496 43.164 35.568 ;
     RECT  41.605 35.568 43.116 35.592 ;
     RECT  41.605 35.592 43.164 35.664 ;
     RECT  41.605 35.664 43.116 35.688 ;
     RECT  41.605 35.688 43.164 35.76 ;
     RECT  41.605 35.76 43.116 35.784 ;
     RECT  41.605 35.784 43.164 35.856 ;
     RECT  41.605 35.856 43.116 35.88 ;
     RECT  41.605 35.88 43.164 35.952 ;
     RECT  41.605 35.952 43.116 35.976 ;
     RECT  41.605 35.976 43.164 36.048 ;
     RECT  41.605 36.048 43.116 36.072 ;
     RECT  41.605 36.072 43.164 36.144 ;
     RECT  41.605 36.144 43.116 36.168 ;
     RECT  41.605 36.168 43.164 36.24 ;
     RECT  41.605 36.24 43.116 36.264 ;
     RECT  41.605 36.264 43.164 36.336 ;
     RECT  41.605 36.336 43.116 36.36 ;
     RECT  41.605 36.36 43.164 36.432 ;
     RECT  41.605 36.432 43.116 36.456 ;
     RECT  41.605 36.456 43.164 36.528 ;
     RECT  41.605 36.528 43.116 36.552 ;
     RECT  41.605 36.552 43.164 36.624 ;
     RECT  41.605 36.624 43.116 36.648 ;
     RECT  41.605 36.648 43.164 36.72 ;
     RECT  41.605 36.72 43.116 36.744 ;
     RECT  41.605 36.744 43.164 36.816 ;
     RECT  41.605 36.816 43.116 36.84 ;
     RECT  41.605 36.84 43.164 36.912 ;
     RECT  41.605 36.912 43.116 36.936 ;
     RECT  41.605 36.936 43.164 37.008 ;
     RECT  41.605 37.008 43.116 37.032 ;
     RECT  41.605 37.032 43.164 37.104 ;
     RECT  41.605 37.104 43.116 37.128 ;
     RECT  41.605 37.128 43.164 37.2 ;
     RECT  41.605 37.2 43.116 37.224 ;
     RECT  41.605 37.224 43.164 37.296 ;
     RECT  41.605 37.296 43.116 37.32 ;
     RECT  41.605 37.32 43.164 37.392 ;
     RECT  41.605 37.392 43.116 37.416 ;
     RECT  41.605 37.416 43.164 37.488 ;
     RECT  41.605 37.488 43.116 37.512 ;
     RECT  41.605 37.512 43.164 37.584 ;
     RECT  41.605 37.584 43.116 37.608 ;
     RECT  41.605 37.608 43.164 37.68 ;
     RECT  41.605 37.68 43.116 37.704 ;
     RECT  41.605 37.704 43.164 37.776 ;
     RECT  41.605 37.776 43.116 37.8 ;
     RECT  41.605 37.8 43.164 37.872 ;
     RECT  41.605 37.872 43.116 37.896 ;
     RECT  41.605 37.896 43.164 37.968 ;
     RECT  41.605 37.968 43.116 37.992 ;
     RECT  41.605 37.992 43.164 38.064 ;
     RECT  41.605 38.064 43.116 38.088 ;
     RECT  41.605 38.088 43.164 38.16 ;
     RECT  41.605 38.16 43.116 38.184 ;
     RECT  41.605 38.184 43.164 38.256 ;
     RECT  41.605 38.256 43.116 38.28 ;
     RECT  41.605 38.28 43.164 39.12 ;
     RECT  41.605 39.12 43.116 39.144 ;
     RECT  41.605 39.144 43.164 39.216 ;
     RECT  41.605 39.216 43.116 39.24 ;
     RECT  41.605 39.24 43.164 39.312 ;
     RECT  41.605 39.312 43.116 39.336 ;
     RECT  41.605 39.336 43.164 39.408 ;
     RECT  41.605 39.408 43.116 39.432 ;
     RECT  41.605 39.432 43.164 39.504 ;
     RECT  41.605 39.504 43.116 39.528 ;
     RECT  41.605 39.528 43.164 39.6 ;
     RECT  41.605 39.6 43.116 39.624 ;
     RECT  41.605 39.624 43.164 39.696 ;
     RECT  41.605 39.696 43.116 39.72 ;
     RECT  41.605 39.72 43.164 39.792 ;
     RECT  41.605 39.792 43.116 39.816 ;
     RECT  41.605 39.816 43.164 39.888 ;
     RECT  41.605 39.888 43.116 39.912 ;
     RECT  41.605 39.912 43.164 39.984 ;
     RECT  41.605 39.984 43.116 40.008 ;
     RECT  41.605 40.008 43.164 40.08 ;
     RECT  41.605 40.08 43.116 40.104 ;
     RECT  41.605 40.104 43.164 40.176 ;
     RECT  41.605 40.176 43.116 40.2 ;
     RECT  41.605 40.2 43.164 40.272 ;
     RECT  41.605 40.272 43.116 40.296 ;
     RECT  41.605 40.296 43.164 40.368 ;
     RECT  41.605 40.368 43.116 40.392 ;
     RECT  41.605 40.392 43.164 40.464 ;
     RECT  41.605 40.464 43.116 40.488 ;
     RECT  41.605 40.488 43.164 40.56 ;
     RECT  41.605 40.56 43.116 40.584 ;
     RECT  41.605 40.584 43.164 40.656 ;
     RECT  41.605 40.656 43.116 40.68 ;
     RECT  41.605 40.68 43.164 40.752 ;
     RECT  41.605 40.752 43.116 40.776 ;
     RECT  41.605 40.776 43.164 40.848 ;
     RECT  41.605 40.848 43.116 40.872 ;
     RECT  41.605 40.872 43.164 40.944 ;
     RECT  41.605 40.944 43.116 40.968 ;
     RECT  41.605 40.968 43.164 41.04 ;
     RECT  41.605 41.04 43.116 41.064 ;
     RECT  41.605 41.064 43.164 41.136 ;
     RECT  41.605 41.136 43.116 41.16 ;
     RECT  41.605 41.16 43.164 41.232 ;
     RECT  41.605 41.232 43.116 41.256 ;
     RECT  41.605 41.256 43.164 41.328 ;
     RECT  41.605 41.328 43.116 41.352 ;
     RECT  41.605 41.352 43.164 41.424 ;
     RECT  41.605 41.424 43.116 41.448 ;
     RECT  41.605 41.448 43.164 41.52 ;
     RECT  41.605 41.52 43.116 41.544 ;
     RECT  41.605 41.544 43.164 41.616 ;
     RECT  41.605 41.616 43.116 41.64 ;
     RECT  41.605 41.64 43.164 41.712 ;
     RECT  41.605 41.712 43.116 41.736 ;
     RECT  41.605 41.736 43.164 41.808 ;
     RECT  41.605 41.808 43.116 41.832 ;
     RECT  41.605 41.832 43.164 41.904 ;
     RECT  41.605 41.904 43.116 41.928 ;
     RECT  41.605 41.928 43.164 42 ;
     RECT  41.605 42 43.116 42.024 ;
     RECT  41.605 42.024 43.164 42.096 ;
     RECT  41.605 42.096 43.116 42.12 ;
    LAYER M5 ;
     RECT  0.144 0.997 0.168 1.093 ;
     RECT  0.144 1.093 0.216 1.189 ;
     RECT  0.144 1.189 0.408 1.285 ;
     RECT  0.144 1.285 0.6 1.477 ;
     RECT  6.888 0.016 6.96 0.084 ;
     RECT  6.984 0.016 7.056 0.084 ;
     RECT  7.08 0.016 7.152 0.084 ;
     RECT  7.176 0.016 7.248 0.084 ;
     RECT  7.272 0.016 7.344 0.084 ;
     RECT  7.368 0.016 7.44 0.084 ;
     RECT  7.464 0.016 7.536 0.084 ;
     RECT  7.56 0.016 7.632 0.084 ;
     RECT  7.656 0.016 7.728 0.084 ;
     RECT  7.752 0.016 7.824 0.084 ;
     RECT  7.848 0.016 7.92 0.084 ;
     RECT  7.944 0.016 8.016 0.084 ;
     RECT  8.04 0.016 8.112 0.084 ;
     RECT  8.136 0.016 8.208 0.084 ;
     RECT  8.232 0.016 8.304 0.084 ;
     RECT  8.328 0.016 8.4 0.084 ;
     RECT  8.424 0.016 8.496 0.084 ;
     RECT  8.52 0.016 8.592 0.084 ;
     RECT  8.616 0.016 8.688 0.084 ;
     RECT  8.712 0.016 8.784 0.084 ;
     RECT  8.808 0.016 8.88 0.084 ;
     RECT  8.904 0.016 8.976 0.084 ;
     RECT  9 0.016 9.072 0.084 ;
     RECT  9.096 0.016 9.168 0.084 ;
     RECT  9.192 0.016 9.264 0.084 ;
     RECT  9.288 0.016 9.36 0.084 ;
     RECT  9.384 0.016 9.456 0.084 ;
     RECT  9.48 0.016 9.552 0.084 ;
     RECT  9.576 0.016 9.648 0.084 ;
     RECT  9.672 0.016 9.744 0.084 ;
     RECT  9.768 0.016 9.84 0.084 ;
     RECT  9.864 0.016 9.936 0.084 ;
     RECT  9.96 0.016 10.032 0.084 ;
     RECT  10.056 0.016 10.128 0.084 ;
     RECT  10.152 0.016 10.224 0.084 ;
     RECT  10.248 0.016 10.32 0.084 ;
     RECT  10.344 0.016 10.416 0.084 ;
     RECT  10.44 0.016 10.512 0.084 ;
     RECT  10.536 0.016 10.608 0.084 ;
     RECT  10.632 0.016 10.704 0.084 ;
     RECT  10.728 0.016 10.8 0.084 ;
     RECT  10.824 0.016 10.896 0.084 ;
     RECT  10.92 0.016 10.992 0.084 ;
     RECT  11.016 0.016 11.088 0.084 ;
     RECT  11.112 0.016 11.184 0.084 ;
     RECT  11.208 0.016 11.28 0.084 ;
     RECT  11.304 0.016 11.376 0.084 ;
     RECT  11.4 0.016 11.472 0.084 ;
     RECT  11.496 0.016 11.568 0.084 ;
     RECT  11.592 0.016 11.664 0.084 ;
     RECT  11.688 0.016 11.76 0.084 ;
     RECT  11.784 0.016 11.856 0.084 ;
     RECT  11.88 0.016 11.952 0.084 ;
     RECT  11.976 0.016 12.048 0.084 ;
     RECT  12.072 0.016 12.144 0.084 ;
     RECT  12.168 0.016 12.24 0.084 ;
     RECT  12.264 0.016 12.336 0.084 ;
     RECT  12.36 0.016 12.432 0.084 ;
     RECT  12.456 0.016 12.528 0.084 ;
     RECT  12.552 0.016 12.624 0.084 ;
     RECT  12.648 0.016 12.72 0.084 ;
     RECT  12.744 0.016 12.816 0.084 ;
     RECT  12.84 0.016 12.912 0.084 ;
     RECT  12.936 0.016 13.008 0.084 ;
     RECT  13.032 0.016 13.104 0.084 ;
     RECT  13.128 0.016 13.2 0.084 ;
     RECT  13.224 0.016 13.296 0.084 ;
     RECT  6.864 0.084 13.32 2.149 ;
     RECT  2.4 2.137 2.52 2.151 ;
     RECT  6.048 2.149 13.32 2.151 ;
     RECT  18.6 2.137 18.72 2.151 ;
     RECT  24 2.137 24.12 2.151 ;
     RECT  29.4 2.137 29.52 2.151 ;
     RECT  34.8 2.137 34.92 2.151 ;
     RECT  40.2 2.137 40.32 2.151 ;
     RECT  2.4 2.151 2.712 2.197 ;
     RECT  2.4 2.197 3.432 2.245 ;
     RECT  6.048 2.151 13.512 2.245 ;
     RECT  2.4 2.245 4.296 2.437 ;
     RECT  6.048 2.245 13.848 2.677 ;
     RECT  2.304 2.437 4.296 2.725 ;
     RECT  2.304 2.725 4.344 2.773 ;
     RECT  2.304 2.773 4.584 2.821 ;
     RECT  5.664 2.677 13.848 2.821 ;
     RECT  22.656 2.197 22.68 3.925 ;
     RECT  22.656 3.925 22.728 4.405 ;
     RECT  2.304 2.821 13.848 4.453 ;
     RECT  0.144 1.477 0.84 4.547 ;
     RECT  22.56 4.405 22.728 4.885 ;
     RECT  0.192 4.547 0.84 5.029 ;
     RECT  2.304 4.453 14.136 5.029 ;
     RECT  0.192 5.029 1.176 5.219 ;
     RECT  15.888 2.245 15.912 5.461 ;
     RECT  18.6 2.151 18.912 5.797 ;
     RECT  2.304 5.029 14.808 5.845 ;
     RECT  15.888 5.461 16.248 5.845 ;
     RECT  2.304 5.845 16.248 6.131 ;
     RECT  0.192 5.219 0.84 6.371 ;
     RECT  18.096 5.797 18.912 6.661 ;
     RECT  0.192 6.371 0.456 6.757 ;
     RECT  24 2.151 24.312 6.805 ;
     RECT  0.144 6.757 0.456 6.947 ;
     RECT  17.904 6.661 18.912 7.381 ;
     RECT  2.304 6.131 13.848 7.957 ;
     RECT  14.832 6.131 16.248 7.957 ;
     RECT  2.304 7.957 16.248 8.291 ;
     RECT  0.192 6.947 0.456 8.293 ;
     RECT  0.144 8.293 0.456 8.485 ;
     RECT  2.304 8.291 13.704 8.579 ;
     RECT  17.904 7.381 19.416 8.771 ;
     RECT  22.56 4.885 22.872 9.061 ;
     RECT  24 6.805 24.984 9.061 ;
     RECT  14.928 8.291 16.248 9.347 ;
     RECT  27.36 7.765 27.384 9.491 ;
     RECT  29.4 2.151 29.712 9.493 ;
     RECT  2.4 8.579 13.704 9.637 ;
     RECT  22.176 9.061 22.872 9.731 ;
     RECT  2.4 9.637 14.568 10.165 ;
     RECT  24 9.061 25.128 10.165 ;
     RECT  26.736 9.685 26.76 10.165 ;
     RECT  0.144 8.485 0.504 10.213 ;
     RECT  0.144 10.213 0.552 10.403 ;
     RECT  22.56 9.731 22.872 10.645 ;
     RECT  24 10.165 26.76 10.645 ;
     RECT  22.56 10.645 26.76 10.741 ;
     RECT  22.464 10.741 26.76 10.883 ;
     RECT  0.288 10.403 0.552 11.171 ;
     RECT  2.304 10.165 14.568 11.221 ;
     RECT  22.464 10.883 24.408 11.221 ;
     RECT  2.304 11.221 14.808 11.267 ;
     RECT  14.784 11.267 14.808 11.365 ;
     RECT  15.888 9.347 16.248 11.365 ;
     RECT  17.904 8.771 19.368 11.365 ;
     RECT  30.816 11.221 30.84 11.411 ;
     RECT  14.784 11.365 16.248 11.459 ;
     RECT  0.288 11.171 0.408 11.749 ;
     RECT  0.24 11.749 0.408 11.797 ;
     RECT  15.408 11.459 16.248 11.987 ;
     RECT  2.304 11.267 13.704 12.035 ;
     RECT  17.904 11.365 19.464 12.181 ;
     RECT  15.888 11.987 16.248 12.803 ;
     RECT  2.304 12.035 13.512 13.045 ;
     RECT  17.664 12.181 19.464 13.139 ;
     RECT  15.888 12.803 15.912 13.237 ;
     RECT  21.36 11.317 21.384 13.285 ;
     RECT  22.416 11.221 24.408 13.285 ;
     RECT  29.136 9.493 29.712 13.573 ;
     RECT  0.144 11.797 0.408 13.621 ;
     RECT  28.416 13.573 29.712 13.621 ;
     RECT  32.016 12.757 32.04 13.621 ;
     RECT  2.304 13.045 13.608 13.715 ;
     RECT  31.152 13.621 32.04 13.715 ;
     RECT  15.792 13.237 15.912 13.813 ;
     RECT  21.36 13.285 24.408 13.861 ;
     RECT  15.792 13.813 16.008 14.195 ;
     RECT  28.272 13.621 29.712 14.197 ;
     RECT  21.072 13.861 24.408 14.387 ;
     RECT  21.072 14.387 21.384 14.435 ;
     RECT  0.144 13.621 0.552 14.627 ;
     RECT  13.104 13.715 13.608 14.773 ;
     RECT  18.24 13.139 19.464 15.011 ;
     RECT  0.144 14.627 0.504 15.251 ;
     RECT  15.984 14.195 16.008 15.347 ;
     RECT  28.128 14.197 29.712 15.349 ;
     RECT  13.104 14.773 13.656 15.443 ;
     RECT  31.152 13.715 31.176 15.445 ;
     RECT  0.144 15.251 0.408 15.491 ;
     RECT  31.152 15.445 31.32 15.539 ;
     RECT  2.304 13.715 11.784 15.973 ;
     RECT  13.104 15.443 13.512 15.973 ;
     RECT  14.832 15.253 14.856 16.261 ;
     RECT  34.8 2.151 35.112 16.261 ;
     RECT  22.416 14.387 24.408 16.357 ;
     RECT  14.64 16.261 14.856 16.453 ;
     RECT  21.36 14.435 21.384 16.595 ;
     RECT  2.304 15.973 13.512 16.643 ;
     RECT  31.296 15.539 31.32 16.835 ;
     RECT  22.416 16.357 24.456 17.029 ;
     RECT  22.416 17.029 24.648 17.075 ;
     RECT  14.64 16.453 15.24 17.077 ;
     RECT  18.336 15.011 19.464 17.315 ;
     RECT  2.4 16.643 13.512 17.605 ;
     RECT  14.64 17.077 15.384 17.605 ;
     RECT  2.4 17.605 15.576 17.989 ;
     RECT  0.144 15.491 0.168 18.229 ;
     RECT  0.144 18.229 0.216 18.515 ;
     RECT  21.072 18.181 21.096 18.517 ;
     RECT  20.88 18.517 21.096 18.661 ;
     RECT  27.888 15.349 29.712 18.709 ;
     RECT  27.888 18.709 30.6 18.755 ;
     RECT  18.432 17.315 19.464 18.757 ;
     RECT  28.368 18.755 30.6 18.949 ;
     RECT  2.4 17.989 16.008 19.091 ;
     RECT  0.144 18.515 0.168 19.139 ;
     RECT  28.368 18.949 30.744 19.427 ;
     RECT  18.432 18.757 19.512 19.525 ;
     RECT  3.888 19.091 16.008 19.859 ;
     RECT  29.4 19.427 30.744 19.859 ;
     RECT  14.496 19.859 16.008 19.907 ;
     RECT  3.888 19.859 13.512 20.051 ;
     RECT  28.368 19.427 28.392 20.051 ;
     RECT  18.432 19.525 19.896 20.293 ;
     RECT  20.88 18.661 21.48 20.293 ;
     RECT  14.496 19.907 15.672 20.339 ;
     RECT  30.72 19.859 30.744 20.339 ;
     RECT  2.4 19.091 2.856 20.579 ;
     RECT  2.4 20.579 2.808 21.013 ;
     RECT  0.144 20.869 0.168 21.059 ;
     RECT  2.304 21.013 2.808 21.155 ;
     RECT  14.496 20.339 15.576 21.539 ;
     RECT  36.432 21.493 36.456 21.589 ;
     RECT  22.464 17.075 24.648 21.637 ;
     RECT  25.776 10.883 26.76 21.637 ;
     RECT  40.2 2.151 40.512 21.637 ;
     RECT  17.232 19.813 17.256 21.683 ;
     RECT  3.888 20.051 9.288 21.685 ;
     RECT  18.432 20.293 21.48 21.779 ;
     RECT  22.464 21.637 26.76 22.019 ;
     RECT  36.432 21.589 36.552 22.021 ;
     RECT  36.432 22.021 36.984 22.117 ;
     RECT  38.64 21.637 41.064 22.165 ;
     RECT  3.888 21.685 9.48 22.259 ;
     RECT  34.8 16.261 35.256 22.453 ;
     RECT  36.384 22.117 36.984 22.453 ;
     RECT  14.496 21.539 14.952 22.499 ;
     RECT  38.64 22.165 41.304 22.693 ;
     RECT  38.64 22.693 41.88 22.741 ;
     RECT  4.08 22.259 9.288 22.787 ;
     RECT  4.08 22.787 9.24 22.835 ;
     RECT  22.464 22.019 25.8 23.317 ;
     RECT  28.32 22.165 28.344 23.317 ;
     RECT  29.4 19.859 29.712 23.317 ;
     RECT  38.64 22.741 41.976 23.317 ;
     RECT  10.464 20.051 13.512 23.555 ;
     RECT  22.464 23.317 25.944 23.555 ;
     RECT  10.464 23.555 10.872 23.603 ;
     RECT  18.6 21.779 21.48 23.653 ;
     RECT  22.464 23.555 24.648 23.653 ;
     RECT  38.64 23.317 42.072 23.701 ;
     RECT  12.192 23.555 13.512 23.797 ;
     RECT  14.496 22.499 14.664 23.797 ;
     RECT  4.08 22.835 4.152 23.893 ;
     RECT  28.32 23.317 29.712 24.131 ;
     RECT  31.776 22.309 31.8 24.277 ;
     RECT  34.8 22.453 37.032 24.325 ;
     RECT  31.296 24.277 31.8 24.373 ;
     RECT  4.032 23.893 4.152 24.469 ;
     RECT  34.8 24.325 37.32 24.469 ;
     RECT  38.448 23.701 42.072 24.469 ;
     RECT  5.472 22.835 9.24 24.709 ;
     RECT  10.464 23.603 10.776 24.709 ;
     RECT  0.192 24.565 0.216 24.755 ;
     RECT  18.6 23.653 24.648 24.997 ;
     RECT  3.984 24.469 4.152 25.045 ;
     RECT  5.472 24.709 10.776 25.045 ;
     RECT  12.192 23.797 14.664 25.045 ;
     RECT  34.8 24.469 42.072 25.045 ;
     RECT  5.472 25.045 14.664 25.091 ;
     RECT  3.984 25.045 4.488 25.187 ;
     RECT  2.4 21.155 2.808 25.283 ;
     RECT  25.92 23.555 25.944 25.621 ;
     RECT  28.368 24.131 29.712 25.715 ;
     RECT  7.8 25.091 14.664 25.907 ;
     RECT  0.144 25.765 0.168 26.051 ;
     RECT  18.48 24.997 24.648 26.051 ;
     RECT  31.296 24.373 31.896 26.243 ;
     RECT  12 25.907 14.664 26.291 ;
     RECT  12 26.291 14.52 26.339 ;
     RECT  16.704 23.893 16.728 26.341 ;
     RECT  22.464 26.051 24.648 26.627 ;
     RECT  16.704 26.341 17.208 26.629 ;
     RECT  15.936 26.629 17.208 26.677 ;
     RECT  31.872 26.243 31.896 26.725 ;
     RECT  7.8 25.907 10.824 26.819 ;
     RECT  12.384 26.339 14.52 26.867 ;
     RECT  34.8 25.045 42.12 27.061 ;
     RECT  7.8 26.819 10.776 27.107 ;
     RECT  9.216 27.107 10.776 27.155 ;
     RECT  10.08 27.155 10.776 27.299 ;
     RECT  12.384 26.867 14.088 27.301 ;
     RECT  15.744 26.677 17.208 27.301 ;
     RECT  18.48 26.051 21.384 27.301 ;
     RECT  22.464 26.627 24.312 27.301 ;
     RECT  18.48 27.301 24.312 27.395 ;
     RECT  25.92 25.621 26.808 27.875 ;
     RECT  10.08 27.299 10.104 27.923 ;
     RECT  11.952 27.301 14.088 27.923 ;
     RECT  5.472 25.091 6.792 27.971 ;
     RECT  11.952 27.923 13.512 27.971 ;
     RECT  4.032 25.187 4.488 28.019 ;
     RECT  5.472 27.971 6.744 28.067 ;
     RECT  5.472 28.067 6.552 28.115 ;
     RECT  4.032 28.019 4.056 28.547 ;
     RECT  5.52 28.115 6.552 28.547 ;
     RECT  11.952 27.971 11.976 28.547 ;
     RECT  18.6 27.395 24.312 28.547 ;
     RECT  34.656 27.061 42.12 28.645 ;
     RECT  5.52 28.547 6.504 28.691 ;
     RECT  15.744 27.301 17.4 28.787 ;
     RECT  34.176 28.645 42.12 28.789 ;
     RECT  18.6 28.547 20.904 28.931 ;
     RECT  31.872 26.725 32.76 29.123 ;
     RECT  32.736 29.123 32.76 29.459 ;
     RECT  19.968 28.931 20.904 29.891 ;
     RECT  15.744 28.787 15.768 29.893 ;
     RECT  28.368 25.715 28.392 29.893 ;
     RECT  22.608 28.547 24.312 29.939 ;
     RECT  28.224 29.893 28.392 29.939 ;
     RECT  15.744 29.893 16.008 29.941 ;
     RECT  33.984 28.789 42.12 30.037 ;
     RECT  18.6 28.931 18.912 30.181 ;
     RECT  19.968 29.891 19.992 30.181 ;
     RECT  25.92 27.875 25.944 30.757 ;
     RECT  22.752 29.939 24.312 30.805 ;
     RECT  18.6 30.181 19.992 30.899 ;
     RECT  15.696 29.941 16.008 31.237 ;
     RECT  14.832 31.237 16.008 31.379 ;
     RECT  22.752 30.805 24.504 31.379 ;
     RECT  25.824 30.757 25.944 31.379 ;
     RECT  23.712 31.379 24.504 31.427 ;
     RECT  25.824 31.379 25.848 31.619 ;
     RECT  33.984 30.037 42.168 31.717 ;
     RECT  13.2 27.971 13.512 31.765 ;
     RECT  24 31.427 24.504 31.811 ;
     RECT  33.888 31.717 42.168 31.859 ;
     RECT  18.6 30.899 19.032 32.005 ;
     RECT  33.984 31.859 42.168 32.005 ;
     RECT  33.984 32.005 42.792 32.195 ;
     RECT  17.28 28.787 17.4 32.821 ;
     RECT  18.6 32.005 19.176 32.821 ;
     RECT  15.984 31.379 16.008 33.011 ;
     RECT  31.296 32.917 31.32 33.013 ;
     RECT  25.728 31.765 25.752 33.107 ;
     RECT  14.832 31.379 14.856 34.021 ;
     RECT  16.08 33.013 16.104 34.021 ;
     RECT  14.832 34.021 16.104 34.067 ;
     RECT  32.352 33.877 32.376 34.115 ;
     RECT  31.2 33.013 31.32 34.211 ;
     RECT  33.984 32.195 42.168 34.261 ;
     RECT  33.984 34.261 43.032 34.451 ;
     RECT  17.28 32.821 19.176 34.883 ;
     RECT  13.2 31.765 13.848 34.933 ;
     RECT  14.832 34.067 15.432 34.933 ;
     RECT  13.2 34.933 15.432 35.077 ;
     RECT  31.2 34.211 31.224 35.221 ;
     RECT  11.28 35.221 11.304 35.317 ;
     RECT  30.864 35.221 31.224 35.459 ;
     RECT  21.648 34.501 21.672 35.699 ;
     RECT  13.2 35.077 16.152 35.797 ;
     RECT  32.496 35.317 32.52 35.989 ;
     RECT  17.28 34.883 18.912 36.035 ;
     RECT  6.48 28.691 6.504 36.131 ;
     RECT  10.992 35.317 11.448 36.227 ;
     RECT  11.424 36.227 11.448 36.275 ;
     RECT  17.28 36.035 17.304 36.275 ;
     RECT  29.4 25.715 29.712 36.373 ;
     RECT  30.864 35.459 30.888 36.373 ;
     RECT  7.8 27.107 8.112 36.421 ;
     RECT  18.6 36.035 18.912 36.421 ;
     RECT  20.256 35.509 20.28 36.421 ;
     RECT  28.224 29.939 28.248 36.421 ;
     RECT  29.4 36.373 30.888 36.421 ;
     RECT  32.064 35.989 32.52 36.421 ;
     RECT  27.936 36.421 32.904 36.469 ;
     RECT  33.984 34.451 42.168 36.469 ;
     RECT  27.936 36.469 42.168 36.947 ;
     RECT  18.6 36.421 20.28 36.997 ;
     RECT  18.6 36.997 20.52 37.045 ;
     RECT  27.936 36.947 28.248 37.091 ;
     RECT  29.4 36.947 42.168 37.331 ;
     RECT  10.608 37.477 10.632 37.621 ;
     RECT  12.528 35.797 16.152 37.667 ;
     RECT  29.4 37.331 42.024 37.811 ;
     RECT  17.664 37.045 20.52 37.907 ;
     RECT  43.008 37.429 43.032 37.907 ;
     RECT  28.224 37.091 28.248 37.957 ;
     RECT  29.4 37.811 29.712 37.957 ;
     RECT  30.768 37.811 42.024 38.003 ;
     RECT  30.768 38.003 30.888 38.099 ;
     RECT  12.864 37.667 15.672 38.147 ;
     RECT  10.608 37.621 10.824 38.149 ;
     RECT  20.256 37.907 20.52 38.243 ;
     RECT  28.224 37.957 29.712 38.243 ;
     RECT  12.864 38.147 15.384 38.339 ;
     RECT  31.92 38.003 42.024 38.387 ;
     RECT  7.68 36.421 8.112 38.723 ;
     RECT  17.664 37.907 18.912 39.011 ;
     RECT  12.864 38.339 14.712 39.061 ;
     RECT  12.816 39.061 14.712 39.109 ;
     RECT  32.784 38.387 42.024 39.155 ;
     RECT  32.784 39.155 41.928 39.203 ;
     RECT  9.504 38.533 9.528 39.301 ;
     RECT  10.608 38.149 11.352 39.301 ;
     RECT  28.224 38.243 28.248 39.635 ;
     RECT  33.216 39.203 41.928 39.683 ;
     RECT  29.4 38.243 29.712 39.781 ;
     RECT  30.768 38.099 30.792 39.827 ;
     RECT  33.216 39.683 33.24 39.923 ;
     RECT  34.464 39.683 41.928 39.923 ;
     RECT  29.136 39.781 29.712 40.067 ;
     RECT  34.656 39.923 41.928 40.307 ;
     RECT  37.392 40.307 41.928 40.403 ;
     RECT  7.8 38.723 8.112 40.405 ;
     RECT  9.504 39.301 11.352 40.405 ;
     RECT  7.8 40.405 11.352 40.453 ;
     RECT  12.624 39.109 14.712 40.453 ;
     RECT  15.936 39.637 15.96 40.453 ;
     RECT  34.656 40.307 36.408 40.499 ;
     RECT  7.8 40.453 16.68 40.501 ;
     RECT  34.656 40.499 35.112 40.739 ;
     RECT  7.8 40.501 16.968 40.789 ;
     RECT  2.4 25.283 2.712 41.049 ;
     RECT  18.6 39.011 18.912 41.049 ;
     RECT  24 31.811 24.312 41.049 ;
     RECT  29.4 40.067 29.712 41.049 ;
     RECT  34.8 40.739 35.112 41.049 ;
     RECT  2.4 41.049 2.52 41.063 ;
     RECT  7.8 40.789 17.064 41.063 ;
     RECT  18.6 41.049 18.72 41.063 ;
     RECT  24 41.049 24.12 41.063 ;
     RECT  29.4 41.049 29.52 41.063 ;
     RECT  34.8 41.049 34.92 41.063 ;
     RECT  37.392 40.403 41.064 41.063 ;
     RECT  37.392 41.063 39.432 41.317 ;
     RECT  37.008 41.317 39.432 41.461 ;
     RECT  41.04 41.063 41.064 42.131 ;
     RECT  36.432 41.461 39.432 42.133 ;
     RECT  8.496 41.063 17.064 42.181 ;
     RECT  36.336 42.133 39.432 42.947 ;
     RECT  36.336 42.947 39.384 43.043 ;
     RECT  8.4 42.181 17.064 43.045 ;
     RECT  8.304 43.045 17.064 43.116 ;
     RECT  8.328 43.116 8.4 43.152 ;
     RECT  8.424 43.116 8.496 43.152 ;
     RECT  8.52 43.116 8.592 43.152 ;
     RECT  8.616 43.116 8.688 43.152 ;
     RECT  8.712 43.116 8.784 43.152 ;
     RECT  8.808 43.116 8.88 43.152 ;
     RECT  8.904 43.116 8.976 43.152 ;
     RECT  9 43.116 9.072 43.152 ;
     RECT  9.096 43.116 9.168 43.152 ;
     RECT  9.192 43.116 9.264 43.152 ;
     RECT  9.288 43.116 9.36 43.152 ;
     RECT  9.384 43.116 9.456 43.152 ;
     RECT  9.48 43.116 9.552 43.152 ;
     RECT  9.576 43.116 9.648 43.152 ;
     RECT  9.672 43.116 9.744 43.152 ;
     RECT  9.768 43.116 9.84 43.152 ;
     RECT  9.864 43.116 9.936 43.152 ;
     RECT  9.96 43.116 10.032 43.152 ;
     RECT  10.056 43.116 10.128 43.152 ;
     RECT  10.152 43.116 10.224 43.152 ;
     RECT  10.248 43.116 10.32 43.152 ;
     RECT  10.344 43.116 10.416 43.152 ;
     RECT  10.44 43.116 10.512 43.152 ;
     RECT  10.536 43.116 10.608 43.152 ;
     RECT  10.632 43.116 10.704 43.152 ;
     RECT  10.728 43.116 10.8 43.152 ;
     RECT  10.824 43.116 10.896 43.152 ;
     RECT  10.92 43.116 10.992 43.152 ;
     RECT  11.016 43.116 11.088 43.152 ;
     RECT  11.112 43.116 11.184 43.152 ;
     RECT  11.208 43.116 11.28 43.152 ;
     RECT  11.304 43.116 11.376 43.152 ;
     RECT  11.4 43.116 11.472 43.152 ;
     RECT  11.496 43.116 11.568 43.152 ;
     RECT  11.592 43.116 11.664 43.152 ;
     RECT  11.688 43.116 11.76 43.152 ;
     RECT  11.784 43.116 11.856 43.152 ;
     RECT  11.88 43.116 11.952 43.152 ;
     RECT  11.976 43.116 12.048 43.152 ;
     RECT  12.072 43.116 12.144 43.152 ;
     RECT  12.168 43.116 12.24 43.152 ;
     RECT  12.264 43.116 12.336 43.152 ;
     RECT  12.36 43.116 12.432 43.152 ;
     RECT  12.456 43.116 12.528 43.152 ;
     RECT  12.552 43.116 12.624 43.152 ;
     RECT  12.648 43.116 12.72 43.152 ;
     RECT  12.744 43.116 12.816 43.152 ;
     RECT  12.84 43.116 12.912 43.152 ;
     RECT  12.936 43.116 13.008 43.152 ;
     RECT  13.032 43.116 13.104 43.152 ;
     RECT  13.128 43.116 13.2 43.152 ;
     RECT  13.224 43.116 13.296 43.152 ;
     RECT  13.32 43.116 13.392 43.152 ;
     RECT  13.416 43.116 13.488 43.152 ;
     RECT  13.512 43.116 13.584 43.152 ;
     RECT  13.608 43.116 13.68 43.152 ;
     RECT  13.704 43.116 13.776 43.152 ;
     RECT  13.8 43.116 13.872 43.152 ;
     RECT  13.896 43.116 13.968 43.152 ;
     RECT  13.992 43.116 14.064 43.152 ;
     RECT  14.088 43.116 14.16 43.152 ;
     RECT  14.184 43.116 14.256 43.152 ;
     RECT  14.28 43.116 14.352 43.152 ;
     RECT  14.376 43.116 14.448 43.152 ;
     RECT  14.472 43.116 14.544 43.152 ;
     RECT  14.568 43.116 14.64 43.152 ;
     RECT  14.664 43.116 14.736 43.152 ;
     RECT  14.76 43.116 14.832 43.152 ;
     RECT  14.856 43.116 14.928 43.152 ;
     RECT  14.952 43.116 15.024 43.152 ;
     RECT  15.048 43.116 15.12 43.152 ;
     RECT  15.144 43.116 15.216 43.152 ;
     RECT  15.24 43.116 15.312 43.152 ;
     RECT  15.336 43.116 15.408 43.152 ;
     RECT  15.432 43.116 15.504 43.152 ;
     RECT  15.528 43.116 15.6 43.152 ;
     RECT  15.624 43.116 15.696 43.152 ;
     RECT  15.72 43.116 15.792 43.152 ;
     RECT  15.816 43.116 15.888 43.152 ;
     RECT  15.912 43.116 15.984 43.152 ;
     RECT  16.008 43.116 16.08 43.152 ;
     RECT  16.104 43.116 16.176 43.152 ;
     RECT  16.2 43.116 16.272 43.152 ;
     RECT  16.296 43.116 16.368 43.152 ;
     RECT  16.392 43.116 16.464 43.152 ;
     RECT  16.488 43.116 16.56 43.152 ;
     RECT  16.584 43.116 16.656 43.152 ;
     RECT  16.68 43.116 16.752 43.152 ;
     RECT  16.776 43.116 16.848 43.152 ;
     RECT  16.872 43.116 16.944 43.152 ;
     RECT  16.968 43.116 17.04 43.152 ;
     RECT  36.336 43.043 39.336 43.116 ;
     RECT  36.36 43.116 36.432 43.152 ;
     RECT  36.456 43.116 36.528 43.152 ;
     RECT  36.552 43.116 36.624 43.152 ;
     RECT  36.648 43.116 36.72 43.152 ;
     RECT  36.744 43.116 36.816 43.152 ;
     RECT  36.84 43.116 36.912 43.152 ;
     RECT  36.936 43.116 37.008 43.152 ;
     RECT  37.032 43.116 37.104 43.152 ;
     RECT  37.128 43.116 37.2 43.152 ;
     RECT  37.224 43.116 37.296 43.152 ;
     RECT  37.32 43.116 37.392 43.152 ;
     RECT  37.416 43.116 37.488 43.152 ;
     RECT  37.512 43.116 37.584 43.152 ;
     RECT  37.608 43.116 37.68 43.152 ;
     RECT  37.704 43.116 37.776 43.152 ;
     RECT  37.8 43.116 37.872 43.152 ;
     RECT  37.896 43.116 37.968 43.152 ;
     RECT  37.992 43.116 38.064 43.152 ;
     RECT  38.088 43.116 38.16 43.152 ;
     RECT  38.184 43.116 38.256 43.152 ;
     RECT  38.28 43.116 38.352 43.152 ;
     RECT  38.376 43.116 38.448 43.152 ;
     RECT  38.472 43.116 38.544 43.152 ;
     RECT  38.568 43.116 38.64 43.152 ;
     RECT  38.664 43.116 38.736 43.152 ;
     RECT  38.76 43.116 38.832 43.152 ;
     RECT  38.856 43.116 38.928 43.152 ;
     RECT  38.952 43.116 39.024 43.152 ;
     RECT  39.048 43.116 39.12 43.152 ;
     RECT  39.144 43.116 39.216 43.152 ;
     RECT  39.24 43.116 39.312 43.152 ;
     RECT  22.68 2.197 24 3.925 ;
     RECT  0.84 2.437 2.304 5.029 ;
     RECT  4.296 2.677 5.664 2.725 ;
     RECT  4.344 2.725 5.664 2.773 ;
     RECT  4.584 2.773 5.664 2.821 ;
     RECT  22.728 3.925 24 4.885 ;
     RECT  22.872 4.885 24 10.645 ;
     RECT  1.176 5.029 2.304 5.219 ;
     RECT  14.808 5.029 15.888 5.845 ;
     RECT  0.84 5.219 2.304 6.371 ;
     RECT  13.848 6.131 14.832 7.957 ;
     RECT  0.18 6.947 0.192 8.293 ;
     RECT  13.704 8.291 14.928 9.347 ;
     RECT  13.704 9.347 15.888 9.637 ;
     RECT  14.568 9.637 15.888 11.221 ;
     RECT  22.416 9.731 22.56 10.741 ;
     RECT  0.18 10.403 0.288 11.749 ;
     RECT  22.416 10.741 22.464 11.221 ;
     RECT  24.408 10.883 25.776 16.357 ;
     RECT  14.808 11.221 15.888 11.365 ;
     RECT  29.712 11.221 30.816 11.411 ;
     RECT  13.704 11.267 14.784 11.459 ;
     RECT  21.384 11.317 22.416 13.285 ;
     RECT  0.18 11.749 0.24 11.797 ;
     RECT  15.792 11.987 15.888 13.237 ;
     RECT  13.512 12.035 13.608 13.045 ;
     RECT  16.248 12.181 17.664 12.803 ;
     RECT  15.912 12.803 16.008 13.813 ;
     RECT  26.76 13.621 28.272 14.197 ;
     RECT  29.712 13.621 31.152 15.539 ;
     RECT  11.784 13.715 13.104 15.973 ;
     RECT  15.792 14.195 15.984 15.253 ;
     RECT  26.76 14.197 28.128 15.349 ;
     RECT  21.384 14.387 22.416 16.595 ;
     RECT  13.656 15.253 14.832 15.443 ;
     RECT  14.856 15.253 15.984 15.347 ;
     RECT  14.856 15.347 15.24 16.453 ;
     RECT  26.76 15.349 27.888 18.755 ;
     RECT  13.512 15.443 14.832 16.261 ;
     RECT  13.512 16.261 14.64 17.605 ;
     RECT  24.456 16.357 25.776 17.029 ;
     RECT  24.648 17.029 25.776 21.637 ;
     RECT  22.416 17.075 22.464 18.181 ;
     RECT  21.096 18.181 22.464 18.661 ;
     RECT  19.464 18.517 20.88 18.757 ;
     RECT  21.48 18.661 22.464 23.653 ;
     RECT  19.512 18.757 20.88 19.525 ;
     RECT  2.856 19.091 3.888 20.579 ;
     RECT  28.392 19.427 29.4 20.051 ;
     RECT  19.896 19.525 20.88 20.293 ;
     RECT  16.008 19.813 17.232 19.907 ;
     RECT  17.256 19.813 18.432 21.683 ;
     RECT  13.512 19.859 14.496 23.797 ;
     RECT  29.712 19.859 30.72 20.339 ;
     RECT  9.288 20.051 10.464 21.685 ;
     RECT  2.808 20.579 3.888 22.259 ;
     RECT  35.256 21.493 36.432 22.117 ;
     RECT  9.48 21.685 10.464 22.259 ;
     RECT  25.8 22.019 25.944 23.317 ;
     RECT  35.256 22.117 36.384 22.453 ;
     RECT  28.344 22.165 29.4 23.317 ;
     RECT  2.808 22.259 4.08 23.893 ;
     RECT  9.288 22.259 10.464 22.787 ;
     RECT  9.24 22.787 10.464 24.709 ;
     RECT  4.152 22.835 5.472 25.045 ;
     RECT  10.872 23.555 12.192 23.603 ;
     RECT  24.648 23.555 25.92 26.627 ;
     RECT  10.776 23.603 12.192 25.045 ;
     RECT  37.032 23.701 38.448 24.325 ;
     RECT  2.808 23.893 4.032 24.469 ;
     RECT  37.32 24.325 38.448 24.469 ;
     RECT  2.808 24.469 3.984 25.187 ;
     RECT  4.488 25.045 5.472 28.019 ;
     RECT  6.792 25.091 7.8 27.971 ;
     RECT  2.808 25.187 4.032 25.283 ;
     RECT  2.712 25.283 4.032 28.547 ;
     RECT  28.392 25.715 29.4 29.939 ;
     RECT  10.824 25.907 12 26.339 ;
     RECT  21.384 26.051 22.464 27.301 ;
     RECT  14.52 26.291 14.664 26.629 ;
     RECT  10.824 26.339 12.384 26.819 ;
     RECT  17.208 26.341 18.48 27.301 ;
     RECT  14.52 26.629 15.936 26.677 ;
     RECT  14.52 26.677 15.744 26.867 ;
     RECT  10.776 26.819 12.384 27.299 ;
     RECT  8.112 27.107 9.216 27.155 ;
     RECT  11.952 27.299 12.384 27.301 ;
     RECT  17.4 27.301 18.48 27.395 ;
     RECT  17.4 27.395 18.6 32.821 ;
     RECT  6.744 27.971 7.8 28.067 ;
     RECT  11.976 27.971 13.2 28.547 ;
     RECT  4.056 28.019 5.472 28.115 ;
     RECT  6.552 28.067 7.8 28.547 ;
     RECT  4.056 28.115 5.52 28.547 ;
     RECT  6.504 28.547 7.8 36.131 ;
     RECT  32.76 28.645 34.176 28.789 ;
     RECT  15.768 28.787 17.28 29.893 ;
     RECT  32.76 28.789 33.984 29.459 ;
     RECT  18.912 28.931 19.968 30.181 ;
     RECT  16.008 29.893 17.28 33.011 ;
     RECT  28.248 29.939 29.4 36.421 ;
     RECT  24.312 30.757 25.824 30.805 ;
     RECT  24.504 30.805 25.824 31.619 ;
     RECT  19.032 30.899 19.176 32.005 ;
     RECT  13.512 31.237 14.832 31.765 ;
     RECT  14.856 31.379 15.984 33.011 ;
     RECT  24.504 31.619 25.752 31.765 ;
     RECT  13.848 31.765 14.832 34.933 ;
     RECT  24.504 31.765 25.728 31.811 ;
     RECT  24.312 31.811 25.728 33.107 ;
     RECT  14.856 33.011 17.28 33.013 ;
     RECT  14.856 33.013 16.08 34.021 ;
     RECT  16.104 33.013 17.28 34.067 ;
     RECT  29.712 33.013 31.2 35.221 ;
     RECT  31.32 33.877 32.352 34.115 ;
     RECT  15.432 34.067 17.28 35.077 ;
     RECT  31.32 34.115 32.376 34.211 ;
     RECT  31.224 34.211 32.376 35.317 ;
     RECT  18.912 34.883 19.176 35.509 ;
     RECT  16.152 35.077 17.28 36.275 ;
     RECT  29.712 35.221 30.864 36.373 ;
     RECT  31.224 35.317 32.496 35.459 ;
     RECT  32.52 35.317 33.984 36.421 ;
     RECT  30.888 35.459 32.496 35.989 ;
     RECT  18.912 35.509 20.256 36.421 ;
     RECT  20.28 35.509 21.648 35.699 ;
     RECT  20.28 35.699 20.52 36.997 ;
     RECT  11.448 35.797 12.528 36.275 ;
     RECT  30.888 35.989 32.064 36.421 ;
     RECT  17.304 36.035 18.6 36.275 ;
     RECT  7.68 36.131 7.8 36.421 ;
     RECT  16.152 36.275 18.6 37.045 ;
     RECT  32.904 36.421 33.984 36.469 ;
     RECT  28.248 36.947 29.4 37.957 ;
     RECT  16.152 37.045 17.664 37.667 ;
     RECT  42.024 37.331 42.168 37.429 ;
     RECT  42.024 37.429 43.008 37.907 ;
     RECT  12.528 37.667 12.864 38.149 ;
     RECT  29.712 37.811 30.768 39.827 ;
     RECT  18.912 37.907 20.256 38.243 ;
     RECT  30.888 38.003 31.92 38.099 ;
     RECT  30.792 38.099 31.92 38.387 ;
     RECT  15.384 38.147 15.672 38.339 ;
     RECT  11.352 38.149 12.864 39.061 ;
     RECT  28.248 38.243 29.4 39.635 ;
     RECT  14.712 38.339 15.672 39.637 ;
     RECT  8.112 38.533 9.504 40.405 ;
     RECT  9.528 38.533 10.608 39.301 ;
     RECT  11.352 39.061 12.816 39.109 ;
     RECT  11.352 39.109 12.624 40.453 ;
     RECT  29.136 39.635 29.4 39.781 ;
     RECT  14.712 39.637 15.936 40.453 ;
     RECT  33.24 39.683 34.464 39.923 ;
     RECT  36.408 40.307 37.392 40.499 ;
     RECT  35.112 40.499 37.392 41.049 ;
     RECT  34.92 41.049 37.392 41.063 ;
     RECT  8.4 41.063 8.496 42.181 ;
     RECT  36.336 41.063 37.392 41.317 ;
     RECT  36.336 41.317 37.008 41.461 ;
     RECT  36.336 41.461 36.432 42.133 ;
  END
END ot_qwen_tp8_pv_wide_ctl_tbf
END LIBRARY
